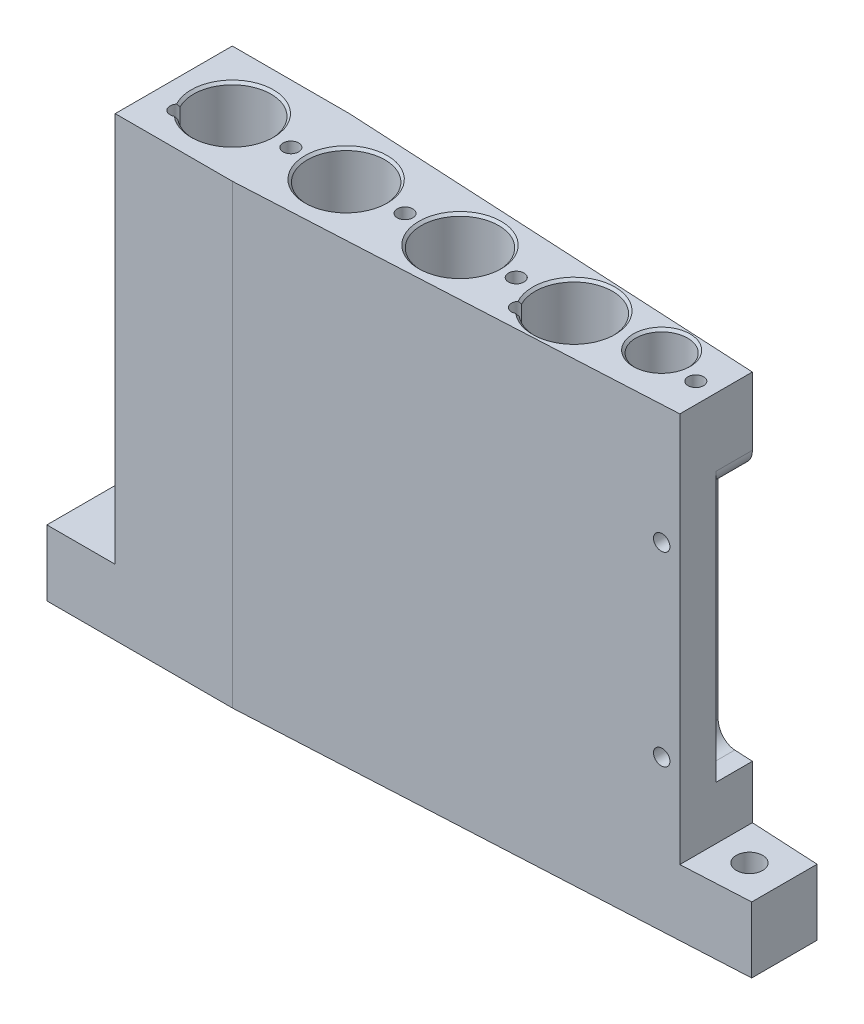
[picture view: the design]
ISO-10303-21;
HEADER;
FILE_DESCRIPTION(('STEP AP214'),'2;1');
FILE_NAME('part.step','',(''),(''),'','','');
FILE_SCHEMA(('AUTOMOTIVE_DESIGN { 1 0 10303 214 1 1 1 1 }'));
ENDSEC;
DATA;
#1=APPLICATION_CONTEXT('core data for automotive mechanical design processes');
#2=APPLICATION_PROTOCOL_DEFINITION('international standard','automotive_design',2000,#1);
#3=PRODUCT_CONTEXT('',#1,'mechanical');
#4=PRODUCT('Part','Part','',(#3));
#5=PRODUCT_RELATED_PRODUCT_CATEGORY('part','',(#4));
#6=PRODUCT_DEFINITION_FORMATION('','',#4);
#7=PRODUCT_DEFINITION_CONTEXT('part definition',#1,'design');
#8=PRODUCT_DEFINITION('design','',#6,#7);
#9=PRODUCT_DEFINITION_SHAPE('','',#8);
#10=(LENGTH_UNIT() NAMED_UNIT(*) SI_UNIT(.MILLI.,.METRE.));
#11=(NAMED_UNIT(*) PLANE_ANGLE_UNIT() SI_UNIT($,.RADIAN.));
#12=(NAMED_UNIT(*) SI_UNIT($,.STERADIAN.) SOLID_ANGLE_UNIT());
#13=UNCERTAINTY_MEASURE_WITH_UNIT(LENGTH_MEASURE(1.E-05),#10,'distance_accuracy_value','');
#14=(GEOMETRIC_REPRESENTATION_CONTEXT(3) GLOBAL_UNCERTAINTY_ASSIGNED_CONTEXT((#13)) GLOBAL_UNIT_ASSIGNED_CONTEXT((#10,
#11,#12)) REPRESENTATION_CONTEXT('',''));
#15=CARTESIAN_POINT('',(0.,0.,0.));
#16=DIRECTION('',(0.,0.,1.));
#17=DIRECTION('',(1.,0.,0.));
#18=AXIS2_PLACEMENT_3D('',#15,#16,#17);
#19=CARTESIAN_POINT('',(69.58,0.,-6.));
#20=DIRECTION('',(0.,-1.,0.));
#21=DIRECTION('',(0.,0.,-1.));
#22=AXIS2_PLACEMENT_3D('',#19,#20,#21);
#23=PLANE('',#22);
#24=CARTESIAN_POINT('',(26.67,0.,-1.5));
#25=DIRECTION('',(0.,-1.,0.));
#26=DIRECTION('',(0.,0.,-1.));
#27=AXIS2_PLACEMENT_3D('',#24,#25,#26);
#28=CIRCLE('',#27,1.3208);
#29=CARTESIAN_POINT('',(26.67,0.,-2.8208));
#30=VERTEX_POINT('',#29);
#31=EDGE_CURVE('E472',#30,#30,#28,.T.);
#32=ORIENTED_EDGE('',*,*,#31,.F.);
#33=EDGE_LOOP('',(#32));
#34=FACE_BOUND('',#33,.T.);
#35=CARTESIAN_POINT('',(26.67,0.,-1.5));
#36=DIRECTION('',(0.,-1.,0.));
#37=DIRECTION('',(0.,0.,-1.));
#38=AXIS2_PLACEMENT_3D('',#35,#36,#37);
#39=CIRCLE('',#38,1.55);
#40=CARTESIAN_POINT('',(26.67,0.,-3.04999999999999));
#41=VERTEX_POINT('',#40);
#42=EDGE_CURVE('E341',#41,#41,#39,.T.);
#43=ORIENTED_EDGE('',*,*,#42,.T.);
#44=EDGE_LOOP('',(#43));
#45=FACE_BOUND('',#44,.T.);
#46=ADVANCED_FACE('F38',(#34,#45),#23,.T.);
#47=CARTESIAN_POINT('',(38.33,0.,-1.5));
#48=DIRECTION('',(0.,-1.,0.));
#49=DIRECTION('',(0.,0.,-1.));
#50=AXIS2_PLACEMENT_3D('',#47,#48,#49);
#51=CIRCLE('',#50,1.3208);
#52=CARTESIAN_POINT('',(38.33,0.,-2.8208));
#53=VERTEX_POINT('',#52);
#54=EDGE_CURVE('E484',#53,#53,#51,.T.);
#55=ORIENTED_EDGE('',*,*,#54,.F.);
#56=EDGE_LOOP('',(#55));
#57=FACE_BOUND('',#56,.T.);
#58=CARTESIAN_POINT('',(34.33,0.,-1.5));
#59=DIRECTION('',(0.,-1.,0.));
#60=DIRECTION('',(0.,0.,-1.));
#61=AXIS2_PLACEMENT_3D('',#58,#59,#60);
#62=CIRCLE('',#61,1.3208);
#63=CARTESIAN_POINT('',(34.33,0.,-2.8208));
#64=VERTEX_POINT('',#63);
#65=EDGE_CURVE('E478',#64,#64,#62,.T.);
#66=ORIENTED_EDGE('',*,*,#65,.F.);
#67=EDGE_LOOP('',(#66));
#68=FACE_BOUND('',#67,.T.);
#69=DIRECTION('',(-1.,0.,0.));
#70=VECTOR('',#69,1.);
#71=CARTESIAN_POINT('',(34.33,0.,0.25));
#72=LINE('',#71,#70);
#73=CARTESIAN_POINT('',(38.33,0.,0.25));
#74=VERTEX_POINT('',#73);
#75=CARTESIAN_POINT('',(34.33,0.,0.25));
#76=VERTEX_POINT('',#75);
#77=EDGE_CURVE('E358',#74,#76,#72,.T.);
#78=ORIENTED_EDGE('',*,*,#77,.T.);
#79=CARTESIAN_POINT('',(34.33,0.,-1.5));
#80=DIRECTION('',(0.,-1.,0.));
#81=DIRECTION('',(0.,0.,-1.));
#82=AXIS2_PLACEMENT_3D('',#79,#80,#81);
#83=CIRCLE('',#82,1.75);
#84=CARTESIAN_POINT('',(34.33,0.,-3.25));
#85=VERTEX_POINT('',#84);
#86=EDGE_CURVE('E351',#76,#85,#83,.T.);
#87=ORIENTED_EDGE('',*,*,#86,.T.);
#88=DIRECTION('',(1.,0.,0.));
#89=VECTOR('',#88,1.);
#90=CARTESIAN_POINT('',(34.33,0.,-3.25));
#91=LINE('',#90,#89);
#92=CARTESIAN_POINT('',(38.33,0.,-3.25));
#93=VERTEX_POINT('',#92);
#94=EDGE_CURVE('E370',#85,#93,#91,.T.);
#95=ORIENTED_EDGE('',*,*,#94,.T.);
#96=CARTESIAN_POINT('',(38.33,0.,-1.5));
#97=DIRECTION('',(0.,-1.,0.));
#98=DIRECTION('',(0.,0.,-1.));
#99=AXIS2_PLACEMENT_3D('',#96,#97,#98);
#100=CIRCLE('',#99,1.75);
#101=EDGE_CURVE('E373',#93,#74,#100,.T.);
#102=ORIENTED_EDGE('',*,*,#101,.T.);
#103=EDGE_LOOP('',(#78,#87,#95,#102));
#104=FACE_BOUND('',#103,.T.);
#105=ADVANCED_FACE('F869',(#57,#68,#104),#23,.T.);
#106=CARTESIAN_POINT('',(13.,0.,0.));
#107=DIRECTION('',(0.,-1.,0.));
#108=DIRECTION('',(0.,0.,-1.));
#109=AXIS2_PLACEMENT_3D('',#106,#107,#108);
#110=CIRCLE('',#109,1.3208);
#111=CARTESIAN_POINT('',(13.,0.,-1.3208));
#112=VERTEX_POINT('',#111);
#113=EDGE_CURVE('E496',#112,#112,#110,.T.);
#114=ORIENTED_EDGE('',*,*,#113,.F.);
#115=EDGE_LOOP('',(#114));
#116=FACE_BOUND('',#115,.T.);
#117=CARTESIAN_POINT('',(13.,0.,0.));
#118=DIRECTION('',(0.,-1.,0.));
#119=DIRECTION('',(0.,0.,-1.));
#120=AXIS2_PLACEMENT_3D('',#117,#118,#119);
#121=CIRCLE('',#120,1.55);
#122=CARTESIAN_POINT('',(13.,0.,-1.55));
#123=VERTEX_POINT('',#122);
#124=EDGE_CURVE('E452',#123,#123,#121,.T.);
#125=ORIENTED_EDGE('',*,*,#124,.T.);
#126=EDGE_LOOP('',(#125));
#127=FACE_BOUND('',#126,.T.);
#128=ADVANCED_FACE('F876',(#116,#127),#23,.T.);
#129=CARTESIAN_POINT('',(69.58,46.75,-6.));
#130=DIRECTION('',(0.,-1.,0.));
#131=DIRECTION('',(0.,0.,-1.));
#132=AXIS2_PLACEMENT_3D('',#129,#130,#131);
#133=PLANE('',#132);
#134=CARTESIAN_POINT('',(56.,46.75,-1.));
#135=DIRECTION('',(0.,-1.,0.));
#136=DIRECTION('',(0.,0.,-1.));
#137=AXIS2_PLACEMENT_3D('',#134,#135,#136);
#138=CIRCLE('',#137,2.90429999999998);
#139=CARTESIAN_POINT('',(56.,46.75,-3.90429999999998));
#140=VERTEX_POINT('',#139);
#141=EDGE_CURVE('E1716',#140,#140,#138,.T.);
#142=ORIENTED_EDGE('',*,*,#141,.T.);
#143=EDGE_LOOP('',(#142));
#144=FACE_BOUND('',#143,.T.);
#145=CARTESIAN_POINT('',(36.3333333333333,46.75,0.));
#146=DIRECTION('',(0.,-1.,0.));
#147=DIRECTION('',(0.,0.,-1.));
#148=AXIS2_PLACEMENT_3D('',#145,#146,#147);
#149=CIRCLE('',#148,4.21874999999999);
#150=CARTESIAN_POINT('',(36.3333333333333,46.75,-4.21874999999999));
#151=VERTEX_POINT('',#150);
#152=EDGE_CURVE('E1717',#151,#151,#149,.T.);
#153=ORIENTED_EDGE('',*,*,#152,.T.);
#154=EDGE_LOOP('',(#153));
#155=FACE_BOUND('',#154,.T.);
#156=CARTESIAN_POINT('',(24.6666666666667,46.75,0.));
#157=DIRECTION('',(0.,-1.,0.));
#158=DIRECTION('',(0.,0.,-1.));
#159=AXIS2_PLACEMENT_3D('',#156,#157,#158);
#160=CIRCLE('',#159,4.21874999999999);
#161=CARTESIAN_POINT('',(24.6666666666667,46.75,-4.21874999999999));
#162=VERTEX_POINT('',#161);
#163=EDGE_CURVE('E1723',#162,#162,#160,.T.);
#164=ORIENTED_EDGE('',*,*,#163,.T.);
#165=EDGE_LOOP('',(#164));
#166=FACE_BOUND('',#165,.T.);
#167=CARTESIAN_POINT('',(19.,46.75,0.));
#168=DIRECTION('',(0.,1.,0.));
#169=DIRECTION('',(0.,0.,1.));
#170=AXIS2_PLACEMENT_3D('',#167,#168,#169);
#171=CIRCLE('',#170,0.799999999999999);
#172=CARTESIAN_POINT('',(19.,46.75,0.799999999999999));
#173=VERTEX_POINT('',#172);
#174=EDGE_CURVE('E503',#173,#173,#171,.T.);
#175=ORIENTED_EDGE('',*,*,#174,.F.);
#176=EDGE_LOOP('',(#175));
#177=FACE_BOUND('',#176,.T.);
#178=CARTESIAN_POINT('',(30.7,46.75,0.));
#179=DIRECTION('',(0.,1.,0.));
#180=DIRECTION('',(0.,0.,1.));
#181=AXIS2_PLACEMENT_3D('',#178,#179,#180);
#182=CIRCLE('',#181,0.800000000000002);
#183=CARTESIAN_POINT('',(30.7,46.75,0.800000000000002));
#184=VERTEX_POINT('',#183);
#185=EDGE_CURVE('E509',#184,#184,#182,.T.);
#186=ORIENTED_EDGE('',*,*,#185,.F.);
#187=EDGE_LOOP('',(#186));
#188=FACE_BOUND('',#187,.T.);
#189=CARTESIAN_POINT('',(42.1,46.75,0.));
#190=DIRECTION('',(0.,1.,0.));
#191=DIRECTION('',(0.,0.,1.));
#192=AXIS2_PLACEMENT_3D('',#189,#190,#191);
#193=CIRCLE('',#192,0.800000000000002);
#194=CARTESIAN_POINT('',(42.1,46.75,0.800000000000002));
#195=VERTEX_POINT('',#194);
#196=EDGE_CURVE('E515',#195,#195,#193,.T.);
#197=ORIENTED_EDGE('',*,*,#196,.F.);
#198=EDGE_LOOP('',(#197));
#199=FACE_BOUND('',#198,.T.);
#200=CARTESIAN_POINT('',(60.5,46.75,0.));
#201=DIRECTION('',(0.,1.,0.));
#202=DIRECTION('',(0.,0.,1.));
#203=AXIS2_PLACEMENT_3D('',#200,#201,#202);
#204=CIRCLE('',#203,0.800000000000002);
#205=CARTESIAN_POINT('',(60.5,46.75,0.800000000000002));
#206=VERTEX_POINT('',#205);
#207=EDGE_CURVE('E521',#206,#206,#204,.T.);
#208=ORIENTED_EDGE('',*,*,#207,.F.);
#209=EDGE_LOOP('',(#208));
#210=FACE_BOUND('',#209,.T.);
#211=DIRECTION('',(0.,0.,-1.));
#212=VECTOR('',#211,1.);
#213=CARTESIAN_POINT('',(62.58,46.75,-3.71685445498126));
#214=LINE('',#213,#212);
#215=CARTESIAN_POINT('',(62.58,46.75,3.71685445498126));
#216=VERTEX_POINT('',#215);
#217=CARTESIAN_POINT('',(62.58,46.75,-3.71685445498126));
#218=VERTEX_POINT('',#217);
#219=EDGE_CURVE('E563',#216,#218,#214,.T.);
#220=ORIENTED_EDGE('',*,*,#219,.T.);
#221=DIRECTION('',(-0.998629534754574,0.,-0.0523359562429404));
#222=VECTOR('',#221,1.);
#223=CARTESIAN_POINT('',(69.58,46.75,-3.35));
#224=LINE('',#223,#222);
#225=CARTESIAN_POINT('',(19.0149877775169,46.75,-6.));
#226=VERTEX_POINT('',#225);
#227=EDGE_CURVE('E614',#218,#226,#224,.T.);
#228=ORIENTED_EDGE('',*,*,#227,.T.);
#229=DIRECTION('',(-1.,0.,0.));
#230=VECTOR('',#229,1.);
#231=CARTESIAN_POINT('',(0.,46.75,-6.));
#232=LINE('',#231,#230);
#233=CARTESIAN_POINT('',(7.,46.75,-6.));
#234=VERTEX_POINT('',#233);
#235=EDGE_CURVE('E616',#226,#234,#232,.T.);
#236=ORIENTED_EDGE('',*,*,#235,.T.);
#237=DIRECTION('',(0.,0.,1.));
#238=VECTOR('',#237,1.);
#239=CARTESIAN_POINT('',(7.,46.75,-6.));
#240=LINE('',#239,#238);
#241=CARTESIAN_POINT('',(6.99999999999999,46.75,6.));
#242=VERTEX_POINT('',#241);
#243=EDGE_CURVE('E579',#234,#242,#240,.T.);
#244=ORIENTED_EDGE('',*,*,#243,.T.);
#245=DIRECTION('',(1.,0.,0.));
#246=VECTOR('',#245,1.);
#247=CARTESIAN_POINT('',(0.,46.75,6.));
#248=LINE('',#247,#246);
#249=CARTESIAN_POINT('',(19.0149877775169,46.75,6.));
#250=VERTEX_POINT('',#249);
#251=EDGE_CURVE('E620',#242,#250,#248,.T.);
#252=ORIENTED_EDGE('',*,*,#251,.T.);
#253=DIRECTION('',(0.998629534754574,0.,-0.0523359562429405));
#254=VECTOR('',#253,1.);
#255=CARTESIAN_POINT('',(19.0149877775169,46.75,6.));
#256=LINE('',#255,#254);
#257=EDGE_CURVE('E622',#250,#216,#256,.T.);
#258=ORIENTED_EDGE('',*,*,#257,.T.);
#259=EDGE_LOOP('',(#220,#228,#236,#244,#252,#258));
#260=FACE_BOUND('',#259,.T.);
#261=CARTESIAN_POINT('',(9.91763458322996,46.75,2.5));
#262=DIRECTION('',(0.,1.,0.));
#263=DIRECTION('',(0.,0.,1.));
#264=AXIS2_PLACEMENT_3D('',#261,#262,#263);
#265=CIRCLE('',#264,0.793749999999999);
#266=CARTESIAN_POINT('',(9.29180855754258,46.75,2.01175738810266));
#267=VERTEX_POINT('',#266);
#268=CARTESIAN_POINT('',(10.2661948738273,46.75,3.21312326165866));
#269=VERTEX_POINT('',#268);
#270=EDGE_CURVE('E527',#267,#269,#265,.T.);
#271=ORIENTED_EDGE('',*,*,#270,.F.);
#272=CARTESIAN_POINT('',(13.,46.75,0.));
#273=DIRECTION('',(0.,-1.,0.));
#274=DIRECTION('',(0.,0.,-1.));
#275=AXIS2_PLACEMENT_3D('',#272,#273,#274);
#276=CIRCLE('',#275,4.21875000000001);
#277=EDGE_CURVE('E820',#267,#269,#276,.T.);
#278=ORIENTED_EDGE('',*,*,#277,.T.);
#279=EDGE_LOOP('',(#271,#278));
#280=FACE_BOUND('',#279,.T.);
#281=CARTESIAN_POINT('',(44.91763458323,46.75,2.5));
#282=DIRECTION('',(0.,1.,0.));
#283=DIRECTION('',(0.,0.,1.));
#284=AXIS2_PLACEMENT_3D('',#281,#282,#283);
#285=CIRCLE('',#284,0.793749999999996);
#286=CARTESIAN_POINT('',(44.2918085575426,46.75,2.01175738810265));
#287=VERTEX_POINT('',#286);
#288=CARTESIAN_POINT('',(45.2661948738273,46.75,3.21312326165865));
#289=VERTEX_POINT('',#288);
#290=EDGE_CURVE('E533',#287,#289,#285,.T.);
#291=ORIENTED_EDGE('',*,*,#290,.F.);
#292=CARTESIAN_POINT('',(48.,46.75,0.));
#293=DIRECTION('',(0.,-1.,0.));
#294=DIRECTION('',(0.,0.,-1.));
#295=AXIS2_PLACEMENT_3D('',#292,#293,#294);
#296=CIRCLE('',#295,4.21874999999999);
#297=EDGE_CURVE('E1712',#287,#289,#296,.T.);
#298=ORIENTED_EDGE('',*,*,#297,.T.);
#299=EDGE_LOOP('',(#291,#298));
#300=FACE_BOUND('',#299,.T.);
#301=ADVANCED_FACE('F896',(#144,#155,#166,#177,#188,#199,#210,#260,#280,#300),#133,.F.);
#302=CARTESIAN_POINT('',(69.58,46.75,-3.35));
#303=DIRECTION('',(-0.0523359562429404,0.,0.998629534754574));
#304=DIRECTION('',(0.998629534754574,0.,0.0523359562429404));
#305=AXIS2_PLACEMENT_3D('',#302,#303,#304);
#306=PLANE('',#305);
#307=DIRECTION('',(0.,1.,0.));
#308=VECTOR('',#307,1.);
#309=CARTESIAN_POINT('',(62.58,6.75,-3.71685445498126));
#310=LINE('',#309,#308);
#311=CARTESIAN_POINT('',(62.58,39.8,-3.71685445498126));
#312=VERTEX_POINT('',#311);
#313=EDGE_CURVE('E569',#312,#218,#310,.T.);
#314=ORIENTED_EDGE('',*,*,#313,.F.);
#315=CARTESIAN_POINT('',(60.78,39.8,-3.81118845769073));
#316=DIRECTION('',(-0.0523359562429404,0.,0.998629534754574));
#317=DIRECTION('',(-0.998629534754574,0.,-0.0523359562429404));
#318=AXIS2_PLACEMENT_3D('',#315,#316,#317);
#319=ELLIPSE('',#318,1.80247022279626,1.8);
#320=CARTESIAN_POINT('',(60.78,38.,-3.81118845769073));
#321=VERTEX_POINT('',#320);
#322=EDGE_CURVE('E305',#312,#321,#319,.F.);
#323=ORIENTED_EDGE('',*,*,#322,.T.);
#324=DIRECTION('',(-0.998629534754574,0.,-0.0523359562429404));
#325=VECTOR('',#324,1.);
#326=CARTESIAN_POINT('',(69.58,38.,-3.35));
#327=LINE('',#326,#325);
#328=CARTESIAN_POINT('',(60.68,38.,-3.81642923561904));
#329=VERTEX_POINT('',#328);
#330=EDGE_CURVE('E266',#321,#329,#327,.T.);
#331=ORIENTED_EDGE('',*,*,#330,.T.);
#332=CARTESIAN_POINT('',(60.68,36.2,-3.81642923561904));
#333=DIRECTION('',(-0.0523359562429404,0.,0.998629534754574));
#334=DIRECTION('',(-0.998629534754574,0.,-0.0523359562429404));
#335=AXIS2_PLACEMENT_3D('',#332,#333,#334);
#336=ELLIPSE('',#335,1.80247022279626,1.8);
#337=CARTESIAN_POINT('',(58.88,36.2,-3.9107632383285));
#338=VERTEX_POINT('',#337);
#339=EDGE_CURVE('E46',#329,#338,#336,.T.);
#340=ORIENTED_EDGE('',*,*,#339,.T.);
#341=DIRECTION('',(0.,-1.,0.));
#342=VECTOR('',#341,1.);
#343=CARTESIAN_POINT('',(58.88,46.75,-3.9107632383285));
#344=LINE('',#343,#342);
#345=CARTESIAN_POINT('',(58.88,14.,-3.9107632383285));
#346=VERTEX_POINT('',#345);
#347=EDGE_CURVE('E283',#338,#346,#344,.T.);
#348=ORIENTED_EDGE('',*,*,#347,.T.);
#349=CARTESIAN_POINT('',(60.68,14.,-3.81642923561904));
#350=DIRECTION('',(-0.0523359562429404,0.,0.998629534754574));
#351=DIRECTION('',(-0.998629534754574,0.,-0.0523359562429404));
#352=AXIS2_PLACEMENT_3D('',#349,#350,#351);
#353=ELLIPSE('',#352,1.80247022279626,1.8);
#354=CARTESIAN_POINT('',(60.68,12.2,-3.81642923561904));
#355=VERTEX_POINT('',#354);
#356=EDGE_CURVE('E11',#346,#355,#353,.T.);
#357=ORIENTED_EDGE('',*,*,#356,.T.);
#358=DIRECTION('',(0.998629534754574,0.,0.0523359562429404));
#359=VECTOR('',#358,1.);
#360=CARTESIAN_POINT('',(69.58,12.2,-3.35));
#361=LINE('',#360,#359);
#362=CARTESIAN_POINT('',(62.58,12.2,-3.71685445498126));
#363=VERTEX_POINT('',#362);
#364=EDGE_CURVE('E339',#355,#363,#361,.T.);
#365=ORIENTED_EDGE('',*,*,#364,.T.);
#366=CARTESIAN_POINT('',(62.58,6.75,-3.71685445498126));
#367=VERTEX_POINT('',#366);
#368=EDGE_CURVE('E282',#367,#363,#310,.T.);
#369=ORIENTED_EDGE('',*,*,#368,.F.);
#370=DIRECTION('',(0.998629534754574,0.,0.0523359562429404));
#371=VECTOR('',#370,1.);
#372=CARTESIAN_POINT('',(69.58,6.75,-3.35));
#373=LINE('',#372,#371);
#374=CARTESIAN_POINT('',(69.58,6.75,-3.35));
#375=VERTEX_POINT('',#374);
#376=EDGE_CURVE('E576',#367,#375,#373,.T.);
#377=ORIENTED_EDGE('',*,*,#376,.T.);
#378=DIRECTION('',(0.,-1.,0.));
#379=VECTOR('',#378,1.);
#380=CARTESIAN_POINT('',(69.58,46.75,-3.35));
#381=LINE('',#380,#379);
#382=CARTESIAN_POINT('',(69.58,0.,-3.35));
#383=VERTEX_POINT('',#382);
#384=EDGE_CURVE('E651',#375,#383,#381,.T.);
#385=ORIENTED_EDGE('',*,*,#384,.T.);
#386=DIRECTION('',(-0.998629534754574,0.,-0.0523359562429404));
#387=VECTOR('',#386,1.);
#388=CARTESIAN_POINT('',(69.58,0.,-3.35));
#389=LINE('',#388,#387);
#390=CARTESIAN_POINT('',(19.0149877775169,0.,-6.));
#391=VERTEX_POINT('',#390);
#392=EDGE_CURVE('E628',#383,#391,#389,.T.);
#393=ORIENTED_EDGE('',*,*,#392,.T.);
#394=DIRECTION('',(0.,-1.,0.));
#395=VECTOR('',#394,1.);
#396=CARTESIAN_POINT('',(19.0149877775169,46.75,-6.));
#397=LINE('',#396,#395);
#398=EDGE_CURVE('E648',#226,#391,#397,.T.);
#399=ORIENTED_EDGE('',*,*,#398,.F.);
#400=ORIENTED_EDGE('',*,*,#227,.F.);
#401=EDGE_LOOP('',(#314,#323,#331,#340,#348,#357,#365,#369,#377,#385,#393,#399,#400));
#402=FACE_BOUND('',#401,.T.);
#403=ADVANCED_FACE('F321',(#402),#306,.F.);
#404=CARTESIAN_POINT('',(19.0149877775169,46.75,6.));
#405=DIRECTION('',(-0.0523359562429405,0.,-0.998629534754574));
#406=DIRECTION('',(-0.998629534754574,0.,0.0523359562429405));
#407=AXIS2_PLACEMENT_3D('',#404,#405,#406);
#408=PLANE('',#407);
#409=CARTESIAN_POINT('',(60.815,34.505,3.80935418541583));
#410=DIRECTION('',(-0.0523359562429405,0.,-0.998629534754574));
#411=DIRECTION('',(0.998629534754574,0.,-0.0523359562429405));
#412=AXIS2_PLACEMENT_3D('',#409,#410,#411);
#413=ELLIPSE('',#412,0.801097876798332,0.799999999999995);
#414=CARTESIAN_POINT('',(61.615,34.505,3.7674279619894));
#415=VERTEX_POINT('',#414);
#416=EDGE_CURVE('E1593',#415,#415,#413,.T.);
#417=ORIENTED_EDGE('',*,*,#416,.T.);
#418=EDGE_LOOP('',(#417));
#419=FACE_BOUND('',#418,.T.);
#420=CARTESIAN_POINT('',(60.815,15.455,3.80935418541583));
#421=DIRECTION('',(-0.0523359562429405,0.,-0.998629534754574));
#422=DIRECTION('',(0.998629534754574,0.,-0.0523359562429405));
#423=AXIS2_PLACEMENT_3D('',#420,#421,#422);
#424=ELLIPSE('',#423,0.801097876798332,0.799999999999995);
#425=CARTESIAN_POINT('',(61.615,15.455,3.7674279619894));
#426=VERTEX_POINT('',#425);
#427=EDGE_CURVE('E277',#426,#426,#424,.T.);
#428=ORIENTED_EDGE('',*,*,#427,.T.);
#429=EDGE_LOOP('',(#428));
#430=FACE_BOUND('',#429,.T.);
#431=DIRECTION('',(0.,1.,0.));
#432=VECTOR('',#431,1.);
#433=CARTESIAN_POINT('',(62.58,6.75,3.71685445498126));
#434=LINE('',#433,#432);
#435=CARTESIAN_POINT('',(62.58,6.75,3.71685445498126));
#436=VERTEX_POINT('',#435);
#437=EDGE_CURVE('E573',#436,#216,#434,.T.);
#438=ORIENTED_EDGE('',*,*,#437,.T.);
#439=ORIENTED_EDGE('',*,*,#257,.F.);
#440=DIRECTION('',(0.,-1.,0.));
#441=VECTOR('',#440,1.);
#442=CARTESIAN_POINT('',(19.0149877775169,46.75,6.));
#443=LINE('',#442,#441);
#444=CARTESIAN_POINT('',(19.0149877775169,0.,6.));
#445=VERTEX_POINT('',#444);
#446=EDGE_CURVE('E641',#250,#445,#443,.T.);
#447=ORIENTED_EDGE('',*,*,#446,.T.);
#448=DIRECTION('',(0.998629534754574,0.,-0.0523359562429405));
#449=VECTOR('',#448,1.);
#450=CARTESIAN_POINT('',(19.0149877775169,0.,6.));
#451=LINE('',#450,#449);
#452=CARTESIAN_POINT('',(69.58,0.,3.35));
#453=VERTEX_POINT('',#452);
#454=EDGE_CURVE('E617',#445,#453,#451,.T.);
#455=ORIENTED_EDGE('',*,*,#454,.T.);
#456=DIRECTION('',(0.,-1.,0.));
#457=VECTOR('',#456,1.);
#458=CARTESIAN_POINT('',(69.58,46.75,3.35));
#459=LINE('',#458,#457);
#460=CARTESIAN_POINT('',(69.58,6.75,3.35));
#461=VERTEX_POINT('',#460);
#462=EDGE_CURVE('E625',#461,#453,#459,.T.);
#463=ORIENTED_EDGE('',*,*,#462,.F.);
#464=DIRECTION('',(-0.998629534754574,0.,0.0523359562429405));
#465=VECTOR('',#464,1.);
#466=CARTESIAN_POINT('',(19.0149877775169,6.75,6.));
#467=LINE('',#466,#465);
#468=EDGE_CURVE('E653',#461,#436,#467,.T.);
#469=ORIENTED_EDGE('',*,*,#468,.T.);
#470=EDGE_LOOP('',(#438,#439,#447,#455,#463,#469));
#471=FACE_BOUND('',#470,.T.);
#472=ADVANCED_FACE('F1565',(#419,#430,#471),#408,.F.);
#473=CARTESIAN_POINT('',(0.,46.75,-6.));
#474=DIRECTION('',(0.,0.,1.));
#475=DIRECTION('',(1.,0.,0.));
#476=AXIS2_PLACEMENT_3D('',#473,#474,#475);
#477=PLANE('',#476);
#478=DIRECTION('',(0.,1.,0.));
#479=VECTOR('',#478,1.);
#480=CARTESIAN_POINT('',(7.,6.75,-6.));
#481=LINE('',#480,#479);
#482=CARTESIAN_POINT('',(7.,6.75,-6.));
#483=VERTEX_POINT('',#482);
#484=EDGE_CURVE('E595',#483,#234,#481,.T.);
#485=ORIENTED_EDGE('',*,*,#484,.T.);
#486=ORIENTED_EDGE('',*,*,#235,.F.);
#487=ORIENTED_EDGE('',*,*,#398,.T.);
#488=DIRECTION('',(-1.,0.,0.));
#489=VECTOR('',#488,1.);
#490=CARTESIAN_POINT('',(0.,0.,-6.));
#491=LINE('',#490,#489);
#492=CARTESIAN_POINT('',(0.,0.,-6.));
#493=VERTEX_POINT('',#492);
#494=EDGE_CURVE('E630',#391,#493,#491,.T.);
#495=ORIENTED_EDGE('',*,*,#494,.T.);
#496=DIRECTION('',(0.,-1.,0.));
#497=VECTOR('',#496,1.);
#498=CARTESIAN_POINT('',(0.,46.75,-6.));
#499=LINE('',#498,#497);
#500=CARTESIAN_POINT('',(0.,6.75,-6.));
#501=VERTEX_POINT('',#500);
#502=EDGE_CURVE('E646',#501,#493,#499,.T.);
#503=ORIENTED_EDGE('',*,*,#502,.F.);
#504=DIRECTION('',(1.,0.,0.));
#505=VECTOR('',#504,1.);
#506=CARTESIAN_POINT('',(0.,6.75,-6.));
#507=LINE('',#506,#505);
#508=EDGE_CURVE('E580',#501,#483,#507,.T.);
#509=ORIENTED_EDGE('',*,*,#508,.T.);
#510=EDGE_LOOP('',(#485,#486,#487,#495,#503,#509));
#511=FACE_BOUND('',#510,.T.);
#512=ADVANCED_FACE('F1556',(#511),#477,.F.);
#513=CARTESIAN_POINT('',(0.,46.75,6.));
#514=DIRECTION('',(0.,0.,-1.));
#515=DIRECTION('',(-1.,0.,0.));
#516=AXIS2_PLACEMENT_3D('',#513,#514,#515);
#517=PLANE('',#516);
#518=DIRECTION('',(0.,1.,0.));
#519=VECTOR('',#518,1.);
#520=CARTESIAN_POINT('',(7.,6.75,6.));
#521=LINE('',#520,#519);
#522=CARTESIAN_POINT('',(7.,6.75,6.));
#523=VERTEX_POINT('',#522);
#524=EDGE_CURVE('E591',#523,#242,#521,.T.);
#525=ORIENTED_EDGE('',*,*,#524,.F.);
#526=DIRECTION('',(-1.,0.,0.));
#527=VECTOR('',#526,1.);
#528=CARTESIAN_POINT('',(0.,6.75,6.));
#529=LINE('',#528,#527);
#530=CARTESIAN_POINT('',(0.,6.75,6.));
#531=VERTEX_POINT('',#530);
#532=EDGE_CURVE('E585',#523,#531,#529,.T.);
#533=ORIENTED_EDGE('',*,*,#532,.T.);
#534=DIRECTION('',(0.,-1.,0.));
#535=VECTOR('',#534,1.);
#536=CARTESIAN_POINT('',(0.,46.75,6.));
#537=LINE('',#536,#535);
#538=CARTESIAN_POINT('',(0.,0.,6.));
#539=VERTEX_POINT('',#538);
#540=EDGE_CURVE('E644',#531,#539,#537,.T.);
#541=ORIENTED_EDGE('',*,*,#540,.T.);
#542=DIRECTION('',(1.,0.,0.));
#543=VECTOR('',#542,1.);
#544=CARTESIAN_POINT('',(0.,0.,6.));
#545=LINE('',#544,#543);
#546=EDGE_CURVE('E636',#539,#445,#545,.T.);
#547=ORIENTED_EDGE('',*,*,#546,.T.);
#548=ORIENTED_EDGE('',*,*,#446,.F.);
#549=ORIENTED_EDGE('',*,*,#251,.F.);
#550=EDGE_LOOP('',(#525,#533,#541,#547,#548,#549));
#551=FACE_BOUND('',#550,.T.);
#552=ADVANCED_FACE('F1548',(#551),#517,.F.);
#553=CARTESIAN_POINT('',(69.58,46.75,3.35));
#554=DIRECTION('',(-1.,0.,0.));
#555=DIRECTION('',(0.,0.,1.));
#556=AXIS2_PLACEMENT_3D('',#553,#554,#555);
#557=PLANE('',#556);
#558=ORIENTED_EDGE('',*,*,#384,.F.);
#559=DIRECTION('',(0.,0.,1.));
#560=VECTOR('',#559,1.);
#561=CARTESIAN_POINT('',(69.58,6.75,-3.71685445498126));
#562=LINE('',#561,#560);
#563=EDGE_CURVE('E564',#375,#461,#562,.T.);
#564=ORIENTED_EDGE('',*,*,#563,.T.);
#565=ORIENTED_EDGE('',*,*,#462,.T.);
#566=DIRECTION('',(0.,0.,-1.));
#567=VECTOR('',#566,1.);
#568=CARTESIAN_POINT('',(69.58,0.,3.35));
#569=LINE('',#568,#567);
#570=EDGE_CURVE('E613',#453,#383,#569,.T.);
#571=ORIENTED_EDGE('',*,*,#570,.T.);
#572=EDGE_LOOP('',(#558,#564,#565,#571));
#573=FACE_BOUND('',#572,.T.);
#574=ADVANCED_FACE('F890',(#573),#557,.F.);
#575=CARTESIAN_POINT('',(0.,46.75,-6.));
#576=DIRECTION('',(1.,0.,0.));
#577=DIRECTION('',(0.,0.,-1.));
#578=AXIS2_PLACEMENT_3D('',#575,#576,#577);
#579=PLANE('',#578);
#580=ORIENTED_EDGE('',*,*,#540,.F.);
#581=DIRECTION('',(0.,0.,-1.));
#582=VECTOR('',#581,1.);
#583=CARTESIAN_POINT('',(0.,6.75,-6.));
#584=LINE('',#583,#582);
#585=EDGE_CURVE('E588',#531,#501,#584,.T.);
#586=ORIENTED_EDGE('',*,*,#585,.T.);
#587=ORIENTED_EDGE('',*,*,#502,.T.);
#588=DIRECTION('',(0.,0.,1.));
#589=VECTOR('',#588,1.);
#590=CARTESIAN_POINT('',(0.,0.,-6.));
#591=LINE('',#590,#589);
#592=EDGE_CURVE('E633',#493,#539,#591,.T.);
#593=ORIENTED_EDGE('',*,*,#592,.T.);
#594=EDGE_LOOP('',(#580,#586,#587,#593));
#595=FACE_BOUND('',#594,.T.);
#596=ADVANCED_FACE('F883',(#595),#579,.F.);
#597=CARTESIAN_POINT('',(26.67,0.,-1.5));
#598=DIRECTION('',(0.,-1.,0.));
#599=DIRECTION('',(0.,0.,-1.));
#600=AXIS2_PLACEMENT_3D('',#597,#598,#599);
#601=CIRCLE('',#600,2.95);
#602=CARTESIAN_POINT('',(26.67,0.,-4.45));
#603=VERTEX_POINT('',#602);
#604=EDGE_CURVE('E345',#603,#603,#601,.T.);
#605=ORIENTED_EDGE('',*,*,#604,.F.);
#606=EDGE_LOOP('',(#605));
#607=FACE_BOUND('',#606,.T.);
#608=CARTESIAN_POINT('',(34.33,0.,-1.5));
#609=DIRECTION('',(0.,-1.,0.));
#610=DIRECTION('',(0.,0.,-1.));
#611=AXIS2_PLACEMENT_3D('',#608,#609,#610);
#612=CIRCLE('',#611,3.05);
#613=CARTESIAN_POINT('',(34.33,0.,1.55));
#614=VERTEX_POINT('',#613);
#615=CARTESIAN_POINT('',(34.33,0.,-4.55));
#616=VERTEX_POINT('',#615);
#617=EDGE_CURVE('E380',#614,#616,#612,.T.);
#618=ORIENTED_EDGE('',*,*,#617,.F.);
#619=DIRECTION('',(-1.,0.,0.));
#620=VECTOR('',#619,1.);
#621=CARTESIAN_POINT('',(34.33,0.,1.55));
#622=LINE('',#621,#620);
#623=CARTESIAN_POINT('',(38.33,0.,1.55));
#624=VERTEX_POINT('',#623);
#625=EDGE_CURVE('E391',#624,#614,#622,.T.);
#626=ORIENTED_EDGE('',*,*,#625,.F.);
#627=CARTESIAN_POINT('',(38.33,0.,-1.5));
#628=DIRECTION('',(0.,-1.,0.));
#629=DIRECTION('',(0.,0.,-1.));
#630=AXIS2_PLACEMENT_3D('',#627,#628,#629);
#631=CIRCLE('',#630,3.05);
#632=CARTESIAN_POINT('',(38.33,0.,-4.55));
#633=VERTEX_POINT('',#632);
#634=EDGE_CURVE('E405',#633,#624,#631,.T.);
#635=ORIENTED_EDGE('',*,*,#634,.F.);
#636=DIRECTION('',(1.,0.,0.));
#637=VECTOR('',#636,1.);
#638=CARTESIAN_POINT('',(34.33,0.,-4.55));
#639=LINE('',#638,#637);
#640=EDGE_CURVE('E402',#616,#633,#639,.T.);
#641=ORIENTED_EDGE('',*,*,#640,.F.);
#642=EDGE_LOOP('',(#618,#626,#635,#641));
#643=FACE_BOUND('',#642,.T.);
#644=CARTESIAN_POINT('',(48.7,0.,-0.8));
#645=DIRECTION('',(0.,-1.,0.));
#646=DIRECTION('',(0.,0.,-1.));
#647=AXIS2_PLACEMENT_3D('',#644,#645,#646);
#648=CIRCLE('',#647,2.95);
#649=CARTESIAN_POINT('',(48.7,0.,-3.75));
#650=VERTEX_POINT('',#649);
#651=EDGE_CURVE('E446',#650,#650,#648,.T.);
#652=ORIENTED_EDGE('',*,*,#651,.F.);
#653=EDGE_LOOP('',(#652));
#654=FACE_BOUND('',#653,.T.);
#655=CARTESIAN_POINT('',(13.,0.,0.));
#656=DIRECTION('',(0.,-1.,0.));
#657=DIRECTION('',(0.,0.,-1.));
#658=AXIS2_PLACEMENT_3D('',#655,#656,#657);
#659=CIRCLE('',#658,2.95);
#660=CARTESIAN_POINT('',(13.,0.,-2.95));
#661=VERTEX_POINT('',#660);
#662=EDGE_CURVE('E458',#661,#661,#659,.T.);
#663=ORIENTED_EDGE('',*,*,#662,.F.);
#664=EDGE_LOOP('',(#663));
#665=FACE_BOUND('',#664,.T.);
#666=CARTESIAN_POINT('',(8.,0.,0.));
#667=DIRECTION('',(0.,-1.,0.));
#668=DIRECTION('',(0.,0.,-1.));
#669=AXIS2_PLACEMENT_3D('',#666,#667,#668);
#670=CIRCLE('',#669,0.793749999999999);
#671=CARTESIAN_POINT('',(8.,0.,-0.793749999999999));
#672=VERTEX_POINT('',#671);
#673=EDGE_CURVE('E539',#672,#672,#670,.T.);
#674=ORIENTED_EDGE('',*,*,#673,.F.);
#675=EDGE_LOOP('',(#674));
#676=FACE_BOUND('',#675,.T.);
#677=CARTESIAN_POINT('',(62.,0.,0.));
#678=DIRECTION('',(0.,-1.,0.));
#679=DIRECTION('',(0.,0.,-1.));
#680=AXIS2_PLACEMENT_3D('',#677,#678,#679);
#681=CIRCLE('',#680,0.793749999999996);
#682=CARTESIAN_POINT('',(62.,0.,-0.793749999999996));
#683=VERTEX_POINT('',#682);
#684=EDGE_CURVE('E545',#683,#683,#681,.T.);
#685=ORIENTED_EDGE('',*,*,#684,.F.);
#686=EDGE_LOOP('',(#685));
#687=FACE_BOUND('',#686,.T.);
#688=CARTESIAN_POINT('',(3.5,0.,0.));
#689=DIRECTION('',(0.,1.,0.));
#690=DIRECTION('',(0.,0.,1.));
#691=AXIS2_PLACEMENT_3D('',#688,#689,#690);
#692=CIRCLE('',#691,1.35);
#693=CARTESIAN_POINT('',(3.5,0.,1.35));
#694=VERTEX_POINT('',#693);
#695=EDGE_CURVE('E554',#694,#694,#692,.T.);
#696=ORIENTED_EDGE('',*,*,#695,.T.);
#697=EDGE_LOOP('',(#696));
#698=FACE_BOUND('',#697,.T.);
#699=CARTESIAN_POINT('',(66.,0.,0.));
#700=DIRECTION('',(0.,1.,0.));
#701=DIRECTION('',(0.,0.,1.));
#702=AXIS2_PLACEMENT_3D('',#699,#700,#701);
#703=CIRCLE('',#702,1.35);
#704=CARTESIAN_POINT('',(66.,0.,1.35000000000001));
#705=VERTEX_POINT('',#704);
#706=EDGE_CURVE('E560',#705,#705,#703,.T.);
#707=ORIENTED_EDGE('',*,*,#706,.T.);
#708=EDGE_LOOP('',(#707));
#709=FACE_BOUND('',#708,.T.);
#710=CARTESIAN_POINT('',(56.,0.,-1.));
#711=DIRECTION('',(0.,1.,0.));
#712=DIRECTION('',(0.,0.,1.));
#713=AXIS2_PLACEMENT_3D('',#710,#711,#712);
#714=CIRCLE('',#713,2.65429999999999);
#715=CARTESIAN_POINT('',(56.,0.,1.65429999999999));
#716=VERTEX_POINT('',#715);
#717=EDGE_CURVE('E598',#716,#716,#714,.T.);
#718=ORIENTED_EDGE('',*,*,#717,.T.);
#719=EDGE_LOOP('',(#718));
#720=FACE_BOUND('',#719,.T.);
#721=ORIENTED_EDGE('',*,*,#570,.F.);
#722=ORIENTED_EDGE('',*,*,#454,.F.);
#723=ORIENTED_EDGE('',*,*,#546,.F.);
#724=ORIENTED_EDGE('',*,*,#592,.F.);
#725=ORIENTED_EDGE('',*,*,#494,.F.);
#726=ORIENTED_EDGE('',*,*,#392,.F.);
#727=EDGE_LOOP('',(#721,#722,#723,#724,#725,#726));
#728=FACE_BOUND('',#727,.T.);
#729=ADVANCED_FACE('F872',(#607,#643,#654,#665,#676,#687,#698,#709,#720,#728),#23,.T.);
#730=CARTESIAN_POINT('',(13.,5.75,0.));
#731=DIRECTION('',(0.,-1.,0.));
#732=DIRECTION('',(0.,0.,-1.));
#733=AXIS2_PLACEMENT_3D('',#730,#731,#732);
#734=PLANE('',#733);
#735=CARTESIAN_POINT('',(13.,5.75,0.));
#736=DIRECTION('',(0.,-1.,0.));
#737=DIRECTION('',(0.,0.,-1.));
#738=AXIS2_PLACEMENT_3D('',#735,#736,#737);
#739=CIRCLE('',#738,0.793749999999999);
#740=CARTESIAN_POINT('',(13.,5.75,-0.793749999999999));
#741=VERTEX_POINT('',#740);
#742=EDGE_CURVE('E464',#741,#741,#739,.T.);
#743=ORIENTED_EDGE('',*,*,#742,.T.);
#744=EDGE_LOOP('',(#743));
#745=FACE_BOUND('',#744,.T.);
#746=CARTESIAN_POINT('',(13.,5.75,0.));
#747=DIRECTION('',(0.,1.,0.));
#748=DIRECTION('',(0.,0.,1.));
#749=AXIS2_PLACEMENT_3D('',#746,#747,#748);
#750=CIRCLE('',#749,3.96874999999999);
#751=CARTESIAN_POINT('',(13.,5.75,3.96874999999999));
#752=VERTEX_POINT('',#751);
#753=EDGE_CURVE('E610',#752,#752,#750,.T.);
#754=ORIENTED_EDGE('',*,*,#753,.T.);
#755=EDGE_LOOP('',(#754));
#756=FACE_BOUND('',#755,.T.);
#757=ADVANCED_FACE('F708',(#745,#756),#734,.F.);
#758=CARTESIAN_POINT('',(13.,46.75,0.));
#759=DIRECTION('',(0.,1.,0.));
#760=DIRECTION('',(0.,0.,1.));
#761=AXIS2_PLACEMENT_3D('',#758,#759,#760);
#762=CYLINDRICAL_SURFACE('',#761,3.96874999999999);
#763=CARTESIAN_POINT('',(9.39720394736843,8.2,1.66458318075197));
#764=CARTESIAN_POINT('',(9.39720015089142,8.25151575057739,1.66457766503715));
#765=CARTESIAN_POINT('',(9.3950788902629,8.30306918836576,1.66000721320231));
#766=CARTESIAN_POINT('',(9.38689600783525,8.40432438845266,1.64211632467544));
#767=CARTESIAN_POINT('',(9.3808289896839,8.4540235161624,1.62878390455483));
#768=CARTESIAN_POINT('',(9.3656158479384,8.54973081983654,1.5945441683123));
#769=CARTESIAN_POINT('',(9.35649439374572,8.59576502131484,1.57369744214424));
#770=CARTESIAN_POINT('',(9.33611399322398,8.68382366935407,1.52564669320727));
#771=CARTESIAN_POINT('',(9.32485412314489,8.72584637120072,1.49843992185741));
#772=CARTESIAN_POINT('',(9.29592501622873,8.82301668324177,1.42580194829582));
#773=CARTESIAN_POINT('',(9.27760225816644,8.8758949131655,1.37759760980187));
#774=CARTESIAN_POINT('',(9.24060805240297,8.9729327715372,1.27320026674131));
#775=CARTESIAN_POINT('',(9.22193591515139,9.01707259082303,1.21698959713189));
#776=CARTESIAN_POINT('',(9.17966040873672,9.11080587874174,1.07835317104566));
#777=CARTESIAN_POINT('',(9.15655709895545,9.15709360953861,0.993540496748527));
#778=CARTESIAN_POINT('',(9.11514381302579,9.23603785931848,0.816790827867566));
#779=CARTESIAN_POINT('',(9.09683703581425,9.26868528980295,0.724849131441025));
#780=CARTESIAN_POINT('',(9.06623219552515,9.32178817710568,0.534684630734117));
#781=CARTESIAN_POINT('',(9.05405211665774,9.34200579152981,0.436376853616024));
#782=CARTESIAN_POINT('',(9.03709875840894,9.36986647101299,0.237427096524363));
#783=CARTESIAN_POINT('',(9.03232405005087,9.37751196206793,0.13678557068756));
#784=CARTESIAN_POINT('',(9.03037198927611,9.38066814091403,-0.0792286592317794));
#785=CARTESIAN_POINT('',(9.03438036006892,9.37428455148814,-0.194647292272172));
#786=CARTESIAN_POINT('',(9.05217122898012,9.34513518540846,-0.422799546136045));
#787=CARTESIAN_POINT('',(9.06596912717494,9.32234359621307,-0.535528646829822));
#788=CARTESIAN_POINT('',(9.10225905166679,9.25916192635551,-0.755694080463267));
#789=CARTESIAN_POINT('',(9.12482059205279,9.21863079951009,-0.863080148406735));
#790=CARTESIAN_POINT('',(9.16307756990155,9.14354831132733,-1.01577012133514));
#791=CARTESIAN_POINT('',(9.17655438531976,9.11616469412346,-1.06523598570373));
#792=CARTESIAN_POINT('',(9.20445302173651,9.05635997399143,-1.16071507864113));
#793=CARTESIAN_POINT('',(9.21887401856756,9.02394323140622,-1.20673124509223));
#794=CARTESIAN_POINT('',(9.24976278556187,8.94954927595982,-1.29976143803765));
#795=CARTESIAN_POINT('',(9.26626744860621,8.9068903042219,-1.34622509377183));
#796=CARTESIAN_POINT('',(9.29833968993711,8.81465642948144,-1.43205481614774));
#797=CARTESIAN_POINT('',(9.313908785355,8.765093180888,-1.47143259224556));
#798=CARTESIAN_POINT('',(9.33963113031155,8.66965708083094,-1.53414262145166));
#799=CARTESIAN_POINT('',(9.35024664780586,8.62499015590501,-1.55910793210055));
#800=CARTESIAN_POINT('',(9.36880331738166,8.53179268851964,-1.60185281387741));
#801=CARTESIAN_POINT('',(9.37674617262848,8.48326463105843,-1.61963696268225));
#802=CARTESIAN_POINT('',(9.38905485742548,8.3830102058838,-1.64690120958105));
#803=CARTESIAN_POINT('',(9.39339081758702,8.33126087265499,-1.65631201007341));
#804=CARTESIAN_POINT('',(9.39773227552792,8.22674071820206,-1.66573554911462));
#805=CARTESIAN_POINT('',(9.39774078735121,8.17397063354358,-1.66575482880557));
#806=CARTESIAN_POINT('',(9.39372431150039,8.07633282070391,-1.65703515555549));
#807=CARTESIAN_POINT('',(9.39022685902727,8.03133443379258,-1.64944166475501));
#808=CARTESIAN_POINT('',(9.38037237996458,7.94328833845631,-1.62770204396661));
#809=CARTESIAN_POINT('',(9.37401426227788,7.90024138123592,-1.61355341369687));
#810=CARTESIAN_POINT('',(9.35701049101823,7.8056113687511,-1.57485187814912));
#811=CARTESIAN_POINT('',(9.34566940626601,7.75488449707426,-1.54851702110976));
#812=CARTESIAN_POINT('',(9.32072722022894,7.65876582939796,-1.48828521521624));
#813=CARTESIAN_POINT('',(9.30712225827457,7.61338337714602,-1.45437531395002));
#814=CARTESIAN_POINT('',(9.27388589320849,7.51301047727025,-1.36744187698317));
#815=CARTESIAN_POINT('',(9.25383159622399,7.46034050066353,-1.31190913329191));
#816=CARTESIAN_POINT('',(9.21423270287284,7.36479083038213,-1.19285651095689));
#817=CARTESIAN_POINT('',(9.19468901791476,7.32192770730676,-1.12932339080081));
#818=CARTESIAN_POINT('',(9.15191662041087,7.23322770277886,-0.97541357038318));
#819=CARTESIAN_POINT('',(9.12947302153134,7.19072576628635,-0.882895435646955));
#820=CARTESIAN_POINT('',(9.09070596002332,7.12022188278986,-0.691363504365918));
#821=CARTESIAN_POINT('',(9.07438571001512,7.0922275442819,-0.592346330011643));
#822=CARTESIAN_POINT('',(9.0490320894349,7.04955971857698,-0.389163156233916));
#823=CARTESIAN_POINT('',(9.04010124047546,7.03507330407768,-0.284945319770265));
#824=CARTESIAN_POINT('',(9.03057042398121,7.01963452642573,-0.0751357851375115));
#825=CARTESIAN_POINT('',(9.02997230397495,7.01868516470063,0.0304562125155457));
#826=CARTESIAN_POINT('',(9.03754816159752,7.03092192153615,0.252035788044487));
#827=CARTESIAN_POINT('',(9.04667978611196,7.04565103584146,0.367909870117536));
#828=CARTESIAN_POINT('',(9.07444728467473,7.09228480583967,0.595037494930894));
#829=CARTESIAN_POINT('',(9.09308123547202,7.12418598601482,0.706291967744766));
#830=CARTESIAN_POINT('',(9.13279794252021,7.19713342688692,0.89606114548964));
#831=CARTESIAN_POINT('',(9.15238604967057,7.23450634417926,0.97630952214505));
#832=CARTESIAN_POINT('',(9.19447351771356,7.32121405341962,1.12924216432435));
#833=CARTESIAN_POINT('',(9.21696809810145,7.37052931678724,1.20193850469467));
#834=CARTESIAN_POINT('',(9.25605616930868,7.46653586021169,1.31776693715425));
#835=CARTESIAN_POINT('',(9.27254891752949,7.51013491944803,1.36349506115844));
#836=CARTESIAN_POINT('',(9.30440780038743,7.60431890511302,1.44761409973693));
#837=CARTESIAN_POINT('',(9.31977537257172,7.65489467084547,1.48601448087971));
#838=CARTESIAN_POINT('',(9.34469428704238,7.75129289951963,1.54613929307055));
#839=CARTESIAN_POINT('',(9.35478762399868,7.79584134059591,1.56967335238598));
#840=CARTESIAN_POINT('',(9.37223403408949,7.88852226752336,1.60958635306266));
#841=CARTESIAN_POINT('',(9.37959209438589,7.93664803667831,1.62597832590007));
#842=CARTESIAN_POINT('',(9.38907517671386,8.02081811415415,1.64690259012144));
#843=CARTESIAN_POINT('',(9.39210273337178,8.05625416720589,1.65350482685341));
#844=CARTESIAN_POINT('',(9.39616856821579,8.12778725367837,1.66234731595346));
#845=CARTESIAN_POINT('',(9.39720660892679,8.16388436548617,1.66458704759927));
#846=CARTESIAN_POINT('',(9.39720394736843,8.2,1.66458318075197));
#847=B_SPLINE_CURVE_WITH_KNOTS('',3,(#763,#764,#765,#766,#767,#768,#769,#770,#771,#772,#773,
#774,#775,#776,#777,#778,#779,#780,#781,#782,#783,#784,#785,#786,#787,#788,#789,#790,#791,#792,
#793,#794,#795,#796,#797,#798,#799,#800,#801,#802,#803,#804,#805,#806,#807,#808,#809,#810,#811,
#812,#813,#814,#815,#816,#817,#818,#819,#820,#821,#822,#823,#824,#825,#826,#827,#828,#829,#830,
#831,#832,#833,#834,#835,#836,#837,#838,#839,#840,#841,#842,#843,#844,#845,#846),.UNSPECIFIED.,
.T.,.F.,(4,2,2,2,2,2,2,2,2,2,2,2,2,2,2,2,2,2,2,2,2,2,2,2,2,2,2,2,2,2,2,2,2,2,2,2,2,2,2,2,2,4),
(0.,0.154380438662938,0.308972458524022,0.462344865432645,0.615783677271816,0.836144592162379,
1.05699946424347,1.35345911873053,1.6501159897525,1.95228574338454,2.25439718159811,
2.59976661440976,2.94568056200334,3.29439628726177,3.46850360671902,3.64246092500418,
3.83742222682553,4.03205833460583,4.18823539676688,4.34431274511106,4.50167008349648,
4.65891782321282,4.79559369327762,4.93232173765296,5.10617739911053,5.28033263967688,
5.5164051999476,5.75287375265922,6.06401253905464,6.37531433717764,6.69086600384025,
7.0064876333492,7.35631283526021,7.70606726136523,7.9771164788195,8.2477254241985,
8.44299159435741,8.63800377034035,8.79157251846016,8.94485987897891,9.05307692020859,
9.16130687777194),.UNSPECIFIED.);
#848=CARTESIAN_POINT('',(9.39720394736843,8.2,1.66458318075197));
#849=VERTEX_POINT('',#848);
#850=EDGE_CURVE('E502',#849,#849,#847,.T.);
#851=ORIENTED_EDGE('',*,*,#850,.T.);
#852=EDGE_LOOP('',(#851));
#853=FACE_BOUND('',#852,.T.);
#854=ORIENTED_EDGE('',*,*,#753,.F.);
#855=EDGE_LOOP('',(#854));
#856=FACE_BOUND('',#855,.T.);
#857=DIRECTION('',(0.,1.,0.));
#858=VECTOR('',#857,1.);
#859=CARTESIAN_POINT('',(10.4767756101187,43.5,3.06338297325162));
#860=LINE('',#859,#858);
#861=CARTESIAN_POINT('',(10.4767756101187,40.25,3.06338297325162));
#862=VERTEX_POINT('',#861);
#863=CARTESIAN_POINT('',(10.4767756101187,46.5,3.06338297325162));
#864=VERTEX_POINT('',#863);
#865=EDGE_CURVE('E813',#862,#864,#860,.T.);
#866=ORIENTED_EDGE('',*,*,#865,.T.);
#867=CARTESIAN_POINT('',(13.,46.5,0.));
#868=DIRECTION('',(0.,-1.,0.));
#869=DIRECTION('',(0.,0.,-1.));
#870=AXIS2_PLACEMENT_3D('',#867,#868,#869);
#871=CIRCLE('',#870,3.96874999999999);
#872=CARTESIAN_POINT('',(9.48178817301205,46.5,1.83661702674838));
#873=VERTEX_POINT('',#872);
#874=EDGE_CURVE('E792',#864,#873,#871,.F.);
#875=ORIENTED_EDGE('',*,*,#874,.T.);
#876=DIRECTION('',(0.,1.,0.));
#877=VECTOR('',#876,1.);
#878=CARTESIAN_POINT('',(9.48178817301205,43.5,1.83661702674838));
#879=LINE('',#878,#877);
#880=CARTESIAN_POINT('',(9.48178817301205,40.25,1.83661702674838));
#881=VERTEX_POINT('',#880);
#882=EDGE_CURVE('E730',#873,#881,#879,.F.);
#883=ORIENTED_EDGE('',*,*,#882,.T.);
#884=CARTESIAN_POINT('',(9.91763458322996,39.7730668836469,2.5));
#885=CARTESIAN_POINT('',(9.91763064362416,39.7730706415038,2.49999514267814));
#886=CARTESIAN_POINT('',(9.91762670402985,39.7730743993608,2.49999028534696));
#887=CARTESIAN_POINT('',(9.91758676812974,39.7731124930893,2.49994104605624));
#888=CARTESIAN_POINT('',(9.91755077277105,39.773146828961,2.49989666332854));
#889=CARTESIAN_POINT('',(9.91737080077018,39.7733185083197,2.49967474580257));
#890=CARTESIAN_POINT('',(9.91722683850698,39.773455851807,2.49949719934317));
#891=CARTESIAN_POINT('',(9.91650710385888,39.774142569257,2.49860940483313));
#892=CARTESIAN_POINT('',(9.9159315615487,39.7746919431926,2.49789897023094));
#893=CARTESIAN_POINT('',(9.91305507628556,39.777438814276,2.49434580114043));
#894=CARTESIAN_POINT('',(9.9107578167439,39.7796363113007,2.49150008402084));
#895=CARTESIAN_POINT('',(9.89929110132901,39.7906238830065,2.4772555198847));
#896=CARTESIAN_POINT('',(9.89018068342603,39.7994139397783,2.46580909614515));
#897=CARTESIAN_POINT('',(9.84493988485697,39.8433697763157,2.40831835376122));
#898=CARTESIAN_POINT('',(9.80976202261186,39.8785344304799,2.36152115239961));
#899=CARTESIAN_POINT('',(9.63872683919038,40.0547175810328,2.12319684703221));
#900=CARTESIAN_POINT('',(9.51864161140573,40.1956633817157,1.9201462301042));
#901=CARTESIAN_POINT('',(9.41726955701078,40.3362982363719,1.70734271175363));
#902=B_SPLINE_CURVE_WITH_KNOTS('',3,(#884,#885,#886,#887,#888,#889,#890,#891,#892,#893,#894,
#895,#896,#897,#898,#899,#900,#901),.UNSPECIFIED.,.F.,.F.,(4,2,2,2,2,2,2,2,4),(0.,
2.18888104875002E-05,0.000221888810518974,0.00102188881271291,0.00422188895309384,
0.0170218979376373,0.0682224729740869,0.273059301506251,1.09464358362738),.UNSPECIFIED.);
#903=CARTESIAN_POINT('',(9.91763458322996,39.7730668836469,2.5));
#904=VERTEX_POINT('',#903);
#905=EDGE_CURVE('E714',#881,#904,#902,.F.);
#906=ORIENTED_EDGE('',*,*,#905,.T.);
#907=CARTESIAN_POINT('',(9.91763458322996,39.7730668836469,2.5));
#908=CARTESIAN_POINT('',(9.91763852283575,39.7730706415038,2.50000485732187));
#909=CARTESIAN_POINT('',(9.91764246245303,39.7730743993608,2.50000971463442));
#910=CARTESIAN_POINT('',(9.91768239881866,39.7731124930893,2.50005895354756));
#911=CARTESIAN_POINT('',(9.91771839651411,39.773146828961,2.50010333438));
#912=CARTESIAN_POINT('',(9.91789838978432,39.7733185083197,2.50032523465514));
#913=CARTESIAN_POINT('',(9.91804239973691,39.773455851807,2.50050274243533));
#914=CARTESIAN_POINT('',(9.91876252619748,39.7741425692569,2.50139021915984));
#915=CARTESIAN_POINT('',(9.91933887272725,39.7746919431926,2.50210000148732));
#916=CARTESIAN_POINT('',(9.92222183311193,39.777438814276,2.50564791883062));
#917=CARTESIAN_POINT('',(9.92453212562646,39.7796363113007,2.50848306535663));
#918=CARTESIAN_POINT('',(9.93610326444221,39.7906238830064,2.52264293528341));
#919=CARTESIAN_POINT('',(9.94542284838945,39.7994139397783,2.53391971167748));
#920=CARTESIAN_POINT('',(9.99233807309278,39.8433697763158,2.59005238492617));
#921=CARTESIAN_POINT('',(10.0308669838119,39.87853443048,2.63413166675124));
#922=CARTESIAN_POINT('',(10.2287583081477,40.0547175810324,2.85067388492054));
#923=CARTESIAN_POINT('',(10.4026514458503,40.1956633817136,3.01008276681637));
#924=CARTESIAN_POINT('',(10.5899498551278,40.3362982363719,3.15319439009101));
#925=B_SPLINE_CURVE_WITH_KNOTS('',3,(#907,#908,#909,#910,#911,#912,#913,#914,#915,#916,#917,
#918,#919,#920,#921,#922,#923,#924),.UNSPECIFIED.,.F.,.F.,(4,2,2,2,2,2,2,2,4),(0.,
2.18888104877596E-05,0.000221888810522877,0.00102188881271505,0.00422188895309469,
0.0170218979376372,0.06822247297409,0.273059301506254,1.09464358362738),.UNSPECIFIED.);
#926=EDGE_CURVE('E723',#904,#862,#925,.T.);
#927=ORIENTED_EDGE('',*,*,#926,.T.);
#928=EDGE_LOOP('',(#866,#875,#883,#906,#927));
#929=FACE_BOUND('',#928,.T.);
#930=ADVANCED_FACE('F703',(#853,#856,#929),#762,.F.);
#931=CARTESIAN_POINT('',(24.6666666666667,5.75,0.));
#932=DIRECTION('',(0.,-1.,0.));
#933=DIRECTION('',(0.,0.,-1.));
#934=AXIS2_PLACEMENT_3D('',#931,#932,#933);
#935=PLANE('',#934);
#936=CARTESIAN_POINT('',(26.67,5.75,-1.5));
#937=DIRECTION('',(0.,-1.,0.));
#938=DIRECTION('',(0.,0.,-1.));
#939=AXIS2_PLACEMENT_3D('',#936,#937,#938);
#940=CIRCLE('',#939,0.396874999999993);
#941=CARTESIAN_POINT('',(26.67,5.75,-1.89687499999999));
#942=VERTEX_POINT('',#941);
#943=EDGE_CURVE('E430',#942,#942,#940,.T.);
#944=ORIENTED_EDGE('',*,*,#943,.T.);
#945=EDGE_LOOP('',(#944));
#946=FACE_BOUND('',#945,.T.);
#947=CARTESIAN_POINT('',(24.6666666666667,5.75,0.));
#948=DIRECTION('',(0.,1.,0.));
#949=DIRECTION('',(0.,0.,1.));
#950=AXIS2_PLACEMENT_3D('',#947,#948,#949);
#951=CIRCLE('',#950,3.96874999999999);
#952=CARTESIAN_POINT('',(24.6666666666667,5.75,3.96874999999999));
#953=VERTEX_POINT('',#952);
#954=EDGE_CURVE('E607',#953,#953,#951,.T.);
#955=ORIENTED_EDGE('',*,*,#954,.T.);
#956=EDGE_LOOP('',(#955));
#957=FACE_BOUND('',#956,.T.);
#958=ADVANCED_FACE('F699',(#946,#957),#935,.F.);
#959=CARTESIAN_POINT('',(24.6666666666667,46.75,0.));
#960=DIRECTION('',(0.,1.,0.));
#961=DIRECTION('',(0.,0.,1.));
#962=AXIS2_PLACEMENT_3D('',#959,#960,#961);
#963=CYLINDRICAL_SURFACE('',#962,3.96874999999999);
#964=CARTESIAN_POINT('',(24.6666666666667,46.5,0.));
#965=DIRECTION('',(0.,-1.,0.));
#966=DIRECTION('',(0.,0.,-1.));
#967=AXIS2_PLACEMENT_3D('',#964,#965,#966);
#968=CIRCLE('',#967,3.96874999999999);
#969=CARTESIAN_POINT('',(24.6666666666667,46.5,-3.96874999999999));
#970=VERTEX_POINT('',#969);
#971=EDGE_CURVE('E794',#970,#970,#968,.F.);
#972=ORIENTED_EDGE('',*,*,#971,.T.);
#973=EDGE_LOOP('',(#972));
#974=FACE_BOUND('',#973,.T.);
#975=ORIENTED_EDGE('',*,*,#954,.F.);
#976=EDGE_LOOP('',(#975));
#977=FACE_BOUND('',#976,.T.);
#978=ADVANCED_FACE('F695',(#974,#977),#963,.F.);
#979=CARTESIAN_POINT('',(36.3333333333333,5.75,0.));
#980=DIRECTION('',(0.,-1.,0.));
#981=DIRECTION('',(0.,0.,-1.));
#982=AXIS2_PLACEMENT_3D('',#979,#980,#981);
#983=PLANE('',#982);
#984=CARTESIAN_POINT('',(38.33,5.75,-1.5));
#985=DIRECTION('',(0.,-1.,0.));
#986=DIRECTION('',(0.,0.,-1.));
#987=AXIS2_PLACEMENT_3D('',#984,#985,#986);
#988=CIRCLE('',#987,0.396874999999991);
#989=CARTESIAN_POINT('',(38.33,5.75,-1.89687499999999));
#990=VERTEX_POINT('',#989);
#991=EDGE_CURVE('E412',#990,#990,#988,.T.);
#992=ORIENTED_EDGE('',*,*,#991,.T.);
#993=EDGE_LOOP('',(#992));
#994=FACE_BOUND('',#993,.T.);
#995=CARTESIAN_POINT('',(34.33,5.75,-1.5));
#996=DIRECTION('',(0.,-1.,0.));
#997=DIRECTION('',(0.,0.,-1.));
#998=AXIS2_PLACEMENT_3D('',#995,#996,#997);
#999=CIRCLE('',#998,0.396874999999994);
#1000=CARTESIAN_POINT('',(34.33,5.75,-1.89687499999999));
#1001=VERTEX_POINT('',#1000);
#1002=EDGE_CURVE('E424',#1001,#1001,#999,.T.);
#1003=ORIENTED_EDGE('',*,*,#1002,.T.);
#1004=EDGE_LOOP('',(#1003));
#1005=FACE_BOUND('',#1004,.T.);
#1006=CARTESIAN_POINT('',(36.3333333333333,5.75,0.));
#1007=DIRECTION('',(0.,1.,0.));
#1008=DIRECTION('',(0.,0.,1.));
#1009=AXIS2_PLACEMENT_3D('',#1006,#1007,#1008);
#1010=CIRCLE('',#1009,3.96874999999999);
#1011=CARTESIAN_POINT('',(36.3333333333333,5.75,3.96874999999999));
#1012=VERTEX_POINT('',#1011);
#1013=EDGE_CURVE('E604',#1012,#1012,#1010,.T.);
#1014=ORIENTED_EDGE('',*,*,#1013,.T.);
#1015=EDGE_LOOP('',(#1014));
#1016=FACE_BOUND('',#1015,.T.);
#1017=ADVANCED_FACE('F691',(#994,#1005,#1016),#983,.F.);
#1018=CARTESIAN_POINT('',(36.3333333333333,46.75,0.));
#1019=DIRECTION('',(0.,1.,0.));
#1020=DIRECTION('',(0.,0.,1.));
#1021=AXIS2_PLACEMENT_3D('',#1018,#1019,#1020);
#1022=CYLINDRICAL_SURFACE('',#1021,3.96874999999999);
#1023=CARTESIAN_POINT('',(36.3333333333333,46.5,0.));
#1024=DIRECTION('',(0.,-1.,0.));
#1025=DIRECTION('',(0.,0.,-1.));
#1026=AXIS2_PLACEMENT_3D('',#1023,#1024,#1025);
#1027=CIRCLE('',#1026,3.96874999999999);
#1028=CARTESIAN_POINT('',(36.3333333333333,46.5,-3.96874999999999));
#1029=VERTEX_POINT('',#1028);
#1030=EDGE_CURVE('E762',#1029,#1029,#1027,.F.);
#1031=ORIENTED_EDGE('',*,*,#1030,.T.);
#1032=EDGE_LOOP('',(#1031));
#1033=FACE_BOUND('',#1032,.T.);
#1034=ORIENTED_EDGE('',*,*,#1013,.F.);
#1035=EDGE_LOOP('',(#1034));
#1036=FACE_BOUND('',#1035,.T.);
#1037=ADVANCED_FACE('F687',(#1033,#1036),#1022,.F.);
#1038=CARTESIAN_POINT('',(48.,5.75,0.));
#1039=DIRECTION('',(0.,-1.,0.));
#1040=DIRECTION('',(0.,0.,-1.));
#1041=AXIS2_PLACEMENT_3D('',#1038,#1039,#1040);
#1042=PLANE('',#1041);
#1043=CARTESIAN_POINT('',(48.7,5.75,-0.8));
#1044=DIRECTION('',(0.,-1.,0.));
#1045=DIRECTION('',(0.,0.,-1.));
#1046=AXIS2_PLACEMENT_3D('',#1043,#1044,#1045);
#1047=CIRCLE('',#1046,0.396874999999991);
#1048=CARTESIAN_POINT('',(48.7,5.75,-1.19687499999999));
#1049=VERTEX_POINT('',#1048);
#1050=EDGE_CURVE('E436',#1049,#1049,#1047,.T.);
#1051=ORIENTED_EDGE('',*,*,#1050,.T.);
#1052=EDGE_LOOP('',(#1051));
#1053=FACE_BOUND('',#1052,.T.);
#1054=CARTESIAN_POINT('',(48.,5.75,0.));
#1055=DIRECTION('',(0.,1.,0.));
#1056=DIRECTION('',(0.,0.,1.));
#1057=AXIS2_PLACEMENT_3D('',#1054,#1055,#1056);
#1058=CIRCLE('',#1057,3.96874999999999);
#1059=CARTESIAN_POINT('',(48.,5.75,3.96874999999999));
#1060=VERTEX_POINT('',#1059);
#1061=EDGE_CURVE('E601',#1060,#1060,#1058,.T.);
#1062=ORIENTED_EDGE('',*,*,#1061,.T.);
#1063=EDGE_LOOP('',(#1062));
#1064=FACE_BOUND('',#1063,.T.);
#1065=ADVANCED_FACE('F681',(#1053,#1064),#1042,.F.);
#1066=CARTESIAN_POINT('',(48.,46.75,0.));
#1067=DIRECTION('',(0.,1.,0.));
#1068=DIRECTION('',(0.,0.,1.));
#1069=AXIS2_PLACEMENT_3D('',#1066,#1067,#1068);
#1070=CYLINDRICAL_SURFACE('',#1069,3.96874999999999);
#1071=ORIENTED_EDGE('',*,*,#1061,.F.);
#1072=EDGE_LOOP('',(#1071));
#1073=FACE_BOUND('',#1072,.T.);
#1074=DIRECTION('',(0.,1.,0.));
#1075=VECTOR('',#1074,1.);
#1076=CARTESIAN_POINT('',(45.4767756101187,43.5,3.06338297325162));
#1077=LINE('',#1076,#1075);
#1078=CARTESIAN_POINT('',(45.4767756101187,40.25,3.06338297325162));
#1079=VERTEX_POINT('',#1078);
#1080=CARTESIAN_POINT('',(45.4767756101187,46.5,3.06338297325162));
#1081=VERTEX_POINT('',#1080);
#1082=EDGE_CURVE('E1730',#1079,#1081,#1077,.T.);
#1083=ORIENTED_EDGE('',*,*,#1082,.T.);
#1084=CARTESIAN_POINT('',(48.,46.5,0.));
#1085=DIRECTION('',(0.,-1.,0.));
#1086=DIRECTION('',(0.,0.,-1.));
#1087=AXIS2_PLACEMENT_3D('',#1084,#1085,#1086);
#1088=CIRCLE('',#1087,3.96874999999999);
#1089=CARTESIAN_POINT('',(44.481788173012,46.5,1.83661702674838));
#1090=VERTEX_POINT('',#1089);
#1091=EDGE_CURVE('E1720',#1081,#1090,#1088,.F.);
#1092=ORIENTED_EDGE('',*,*,#1091,.T.);
#1093=DIRECTION('',(0.,1.,0.));
#1094=VECTOR('',#1093,1.);
#1095=CARTESIAN_POINT('',(44.481788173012,43.5,1.83661702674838));
#1096=LINE('',#1095,#1094);
#1097=CARTESIAN_POINT('',(44.481788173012,40.25,1.83661702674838));
#1098=VERTEX_POINT('',#1097);
#1099=EDGE_CURVE('E1732',#1090,#1098,#1096,.F.);
#1100=ORIENTED_EDGE('',*,*,#1099,.T.);
#1101=CARTESIAN_POINT('',(44.91763458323,39.7730668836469,2.5));
#1102=CARTESIAN_POINT('',(44.9176306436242,39.7730706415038,2.49999514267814));
#1103=CARTESIAN_POINT('',(44.9176267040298,39.7730743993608,2.49999028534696));
#1104=CARTESIAN_POINT('',(44.9175867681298,39.7731124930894,2.49994104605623));
#1105=CARTESIAN_POINT('',(44.9175507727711,39.773146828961,2.49989666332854));
#1106=CARTESIAN_POINT('',(44.9173708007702,39.7733185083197,2.49967474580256));
#1107=CARTESIAN_POINT('',(44.917226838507,39.773455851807,2.49949719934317));
#1108=CARTESIAN_POINT('',(44.9165071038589,39.774142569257,2.49860940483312));
#1109=CARTESIAN_POINT('',(44.9159315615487,39.7746919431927,2.49789897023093));
#1110=CARTESIAN_POINT('',(44.9130550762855,39.7774388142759,2.49434580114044));
#1111=CARTESIAN_POINT('',(44.9107578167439,39.7796363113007,2.49150008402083));
#1112=CARTESIAN_POINT('',(44.8992911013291,39.7906238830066,2.47725551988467));
#1113=CARTESIAN_POINT('',(44.8901806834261,39.7994139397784,2.46580909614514));
#1114=CARTESIAN_POINT('',(44.8449398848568,39.8433697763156,2.40831835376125));
#1115=CARTESIAN_POINT('',(44.8097620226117,39.8785344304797,2.36152115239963));
#1116=CARTESIAN_POINT('',(44.638726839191,40.0547175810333,2.12319684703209));
#1117=CARTESIAN_POINT('',(44.5186416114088,40.1956633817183,1.92014623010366));
#1118=CARTESIAN_POINT('',(44.4172695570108,40.3362982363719,1.70734271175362));
#1119=B_SPLINE_CURVE_WITH_KNOTS('',3,(#1101,#1102,#1103,#1104,#1105,#1106,#1107,#1108,#1109,
#1110,#1111,#1112,#1113,#1114,#1115,#1116,#1117,#1118),.UNSPECIFIED.,.F.,.F.,(4,2,2,2,2,2,2,2,
4),(0.,2.18888104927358E-05,0.000221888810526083,0.0010218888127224,0.00422188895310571,
0.0170218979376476,0.068222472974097,0.273059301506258,1.09464358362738),.UNSPECIFIED.);
#1120=CARTESIAN_POINT('',(44.91763458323,39.7730668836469,2.5));
#1121=VERTEX_POINT('',#1120);
#1122=EDGE_CURVE('E656',#1098,#1121,#1119,.F.);
#1123=ORIENTED_EDGE('',*,*,#1122,.T.);
#1124=CARTESIAN_POINT('',(44.91763458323,39.7730668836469,2.5));
#1125=CARTESIAN_POINT('',(44.9176385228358,39.7730706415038,2.50000485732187));
#1126=CARTESIAN_POINT('',(44.917642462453,39.7730743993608,2.50000971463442));
#1127=CARTESIAN_POINT('',(44.9176823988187,39.7731124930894,2.50005895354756));
#1128=CARTESIAN_POINT('',(44.9177183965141,39.773146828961,2.50010333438));
#1129=CARTESIAN_POINT('',(44.9178983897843,39.7733185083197,2.50032523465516));
#1130=CARTESIAN_POINT('',(44.9180423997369,39.773455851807,2.50050274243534));
#1131=CARTESIAN_POINT('',(44.9187625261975,39.774142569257,2.50139021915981));
#1132=CARTESIAN_POINT('',(44.9193388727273,39.7746919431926,2.50210000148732));
#1133=CARTESIAN_POINT('',(44.9222218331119,39.777438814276,2.50564791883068));
#1134=CARTESIAN_POINT('',(44.9245321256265,39.7796363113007,2.50848306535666));
#1135=CARTESIAN_POINT('',(44.9361032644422,39.7906238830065,2.52264293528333));
#1136=CARTESIAN_POINT('',(44.9454228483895,39.7994139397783,2.53391971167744));
#1137=CARTESIAN_POINT('',(44.9923380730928,39.8433697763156,2.59005238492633));
#1138=CARTESIAN_POINT('',(45.0308669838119,39.8785344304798,2.63413166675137));
#1139=CARTESIAN_POINT('',(45.2287583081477,40.054717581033,2.85067388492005));
#1140=CARTESIAN_POINT('',(45.4026514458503,40.1956633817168,3.01008276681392));
#1141=CARTESIAN_POINT('',(45.5899498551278,40.3362982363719,3.15319439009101));
#1142=B_SPLINE_CURVE_WITH_KNOTS('',3,(#1124,#1125,#1126,#1127,#1128,#1129,#1130,#1131,#1132,
#1133,#1134,#1135,#1136,#1137,#1138,#1139,#1140,#1141),.UNSPECIFIED.,.F.,.F.,(4,2,2,2,2,2,2,2,
4),(0.,2.18888104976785E-05,0.000221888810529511,0.00102188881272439,0.00422188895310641,
0.0170218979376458,0.0682224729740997,0.273059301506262,1.09464358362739),.UNSPECIFIED.);
#1143=EDGE_CURVE('E665',#1121,#1079,#1142,.T.);
#1144=ORIENTED_EDGE('',*,*,#1143,.T.);
#1145=EDGE_LOOP('',(#1083,#1092,#1100,#1123,#1144));
#1146=FACE_BOUND('',#1145,.T.);
#1147=ADVANCED_FACE('F675',(#1073,#1146),#1070,.F.);
#1148=CARTESIAN_POINT('',(56.,46.75,-1.));
#1149=DIRECTION('',(0.,1.,0.));
#1150=DIRECTION('',(0.,0.,1.));
#1151=AXIS2_PLACEMENT_3D('',#1148,#1149,#1150);
#1152=CYLINDRICAL_SURFACE('',#1151,2.65429999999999);
#1153=CARTESIAN_POINT('',(56.,46.5,-1.));
#1154=DIRECTION('',(0.,-1.,0.));
#1155=DIRECTION('',(0.,0.,-1.));
#1156=AXIS2_PLACEMENT_3D('',#1153,#1154,#1155);
#1157=CIRCLE('',#1156,2.65429999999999);
#1158=CARTESIAN_POINT('',(56.,46.5,-3.65429999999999));
#1159=VERTEX_POINT('',#1158);
#1160=EDGE_CURVE('E818',#1159,#1159,#1157,.F.);
#1161=ORIENTED_EDGE('',*,*,#1160,.T.);
#1162=EDGE_LOOP('',(#1161));
#1163=FACE_BOUND('',#1162,.T.);
#1164=ORIENTED_EDGE('',*,*,#717,.F.);
#1165=EDGE_LOOP('',(#1164));
#1166=FACE_BOUND('',#1165,.T.);
#1167=ADVANCED_FACE('F680',(#1163,#1166),#1152,.F.);
#1168=CARTESIAN_POINT('',(7.,6.75,-6.));
#1169=DIRECTION('',(-1.,0.,0.));
#1170=DIRECTION('',(0.,0.,1.));
#1171=AXIS2_PLACEMENT_3D('',#1168,#1169,#1170);
#1172=PLANE('',#1171);
#1173=ORIENTED_EDGE('',*,*,#243,.F.);
#1174=ORIENTED_EDGE('',*,*,#484,.F.);
#1175=DIRECTION('',(0.,0.,1.));
#1176=VECTOR('',#1175,1.);
#1177=CARTESIAN_POINT('',(7.,6.75,-6.));
#1178=LINE('',#1177,#1176);
#1179=EDGE_CURVE('E583',#483,#523,#1178,.T.);
#1180=ORIENTED_EDGE('',*,*,#1179,.T.);
#1181=ORIENTED_EDGE('',*,*,#524,.T.);
#1182=EDGE_LOOP('',(#1173,#1174,#1180,#1181));
#1183=FACE_BOUND('',#1182,.T.);
#1184=ADVANCED_FACE('F1381',(#1183),#1172,.T.);
#1185=CARTESIAN_POINT('',(7.,6.75,-6.));
#1186=DIRECTION('',(0.,-1.,0.));
#1187=DIRECTION('',(0.,0.,-1.));
#1188=AXIS2_PLACEMENT_3D('',#1185,#1186,#1187);
#1189=PLANE('',#1188);
#1190=CARTESIAN_POINT('',(3.5,6.75,0.));
#1191=DIRECTION('',(0.,1.,0.));
#1192=DIRECTION('',(0.,0.,1.));
#1193=AXIS2_PLACEMENT_3D('',#1190,#1191,#1192);
#1194=CIRCLE('',#1193,1.35);
#1195=CARTESIAN_POINT('',(3.5,6.75,1.35));
#1196=VERTEX_POINT('',#1195);
#1197=EDGE_CURVE('E551',#1196,#1196,#1194,.T.);
#1198=ORIENTED_EDGE('',*,*,#1197,.F.);
#1199=EDGE_LOOP('',(#1198));
#1200=FACE_BOUND('',#1199,.T.);
#1201=ORIENTED_EDGE('',*,*,#508,.F.);
#1202=ORIENTED_EDGE('',*,*,#585,.F.);
#1203=ORIENTED_EDGE('',*,*,#532,.F.);
#1204=ORIENTED_EDGE('',*,*,#1179,.F.);
#1205=EDGE_LOOP('',(#1201,#1202,#1203,#1204));
#1206=FACE_BOUND('',#1205,.T.);
#1207=ADVANCED_FACE('F1515',(#1200,#1206),#1189,.F.);
#1208=CARTESIAN_POINT('',(69.58,6.75,-3.71685445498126));
#1209=DIRECTION('',(0.,-1.,0.));
#1210=DIRECTION('',(0.,0.,-1.));
#1211=AXIS2_PLACEMENT_3D('',#1208,#1209,#1210);
#1212=PLANE('',#1211);
#1213=CARTESIAN_POINT('',(66.,6.75,0.));
#1214=DIRECTION('',(0.,1.,0.));
#1215=DIRECTION('',(0.,0.,1.));
#1216=AXIS2_PLACEMENT_3D('',#1213,#1214,#1215);
#1217=CIRCLE('',#1216,1.35);
#1218=CARTESIAN_POINT('',(66.,6.75,1.35000000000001));
#1219=VERTEX_POINT('',#1218);
#1220=EDGE_CURVE('E557',#1219,#1219,#1217,.T.);
#1221=ORIENTED_EDGE('',*,*,#1220,.F.);
#1222=EDGE_LOOP('',(#1221));
#1223=FACE_BOUND('',#1222,.T.);
#1224=DIRECTION('',(0.,0.,-1.));
#1225=VECTOR('',#1224,1.);
#1226=CARTESIAN_POINT('',(62.58,6.75,-3.71685445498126));
#1227=LINE('',#1226,#1225);
#1228=EDGE_CURVE('E567',#436,#367,#1227,.T.);
#1229=ORIENTED_EDGE('',*,*,#1228,.F.);
#1230=ORIENTED_EDGE('',*,*,#468,.F.);
#1231=ORIENTED_EDGE('',*,*,#563,.F.);
#1232=ORIENTED_EDGE('',*,*,#376,.F.);
#1233=EDGE_LOOP('',(#1229,#1230,#1231,#1232));
#1234=FACE_BOUND('',#1233,.T.);
#1235=ADVANCED_FACE('F1510',(#1223,#1234),#1212,.F.);
#1236=CARTESIAN_POINT('',(62.58,6.75,-3.71685445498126));
#1237=DIRECTION('',(1.,0.,0.));
#1238=DIRECTION('',(0.,0.,-1.));
#1239=AXIS2_PLACEMENT_3D('',#1236,#1237,#1238);
#1240=PLANE('',#1239);
#1241=DIRECTION('',(0.,1.,0.));
#1242=VECTOR('',#1241,1.);
#1243=CARTESIAN_POINT('',(62.58,38.,0.));
#1244=LINE('',#1243,#1242);
#1245=CARTESIAN_POINT('',(62.58,12.2,0.));
#1246=VERTEX_POINT('',#1245);
#1247=CARTESIAN_POINT('',(62.58,39.8,0.));
#1248=VERTEX_POINT('',#1247);
#1249=EDGE_CURVE('E270',#1246,#1248,#1244,.T.);
#1250=ORIENTED_EDGE('',*,*,#1249,.T.);
#1251=DIRECTION('',(0.,0.,1.));
#1252=VECTOR('',#1251,1.);
#1253=CARTESIAN_POINT('',(62.58,39.8,-3.71685445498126));
#1254=LINE('',#1253,#1252);
#1255=EDGE_CURVE('E303',#1248,#312,#1254,.F.);
#1256=ORIENTED_EDGE('',*,*,#1255,.T.);
#1257=ORIENTED_EDGE('',*,*,#313,.T.);
#1258=ORIENTED_EDGE('',*,*,#219,.F.);
#1259=ORIENTED_EDGE('',*,*,#437,.F.);
#1260=ORIENTED_EDGE('',*,*,#1228,.T.);
#1261=ORIENTED_EDGE('',*,*,#368,.T.);
#1262=DIRECTION('',(0.,0.,-1.));
#1263=VECTOR('',#1262,1.);
#1264=CARTESIAN_POINT('',(62.58,12.2,-3.71685445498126));
#1265=LINE('',#1264,#1263);
#1266=EDGE_CURVE('E263',#1246,#363,#1265,.T.);
#1267=ORIENTED_EDGE('',*,*,#1266,.F.);
#1268=EDGE_LOOP('',(#1250,#1256,#1257,#1258,#1259,#1260,#1261,#1267));
#1269=FACE_BOUND('',#1268,.T.);
#1270=ADVANCED_FACE('F279',(#1269),#1240,.T.);
#1271=CARTESIAN_POINT('',(66.,6.75,0.));
#1272=DIRECTION('',(0.,1.,0.));
#1273=DIRECTION('',(0.,0.,1.));
#1274=AXIS2_PLACEMENT_3D('',#1271,#1272,#1273);
#1275=CYLINDRICAL_SURFACE('',#1274,1.35);
#1276=ORIENTED_EDGE('',*,*,#706,.F.);
#1277=EDGE_LOOP('',(#1276));
#1278=FACE_BOUND('',#1277,.T.);
#1279=ORIENTED_EDGE('',*,*,#1220,.T.);
#1280=EDGE_LOOP('',(#1279));
#1281=FACE_BOUND('',#1280,.T.);
#1282=ADVANCED_FACE('F1493',(#1278,#1281),#1275,.F.);
#1283=CARTESIAN_POINT('',(3.5,6.75,0.));
#1284=DIRECTION('',(0.,1.,0.));
#1285=DIRECTION('',(0.,0.,1.));
#1286=AXIS2_PLACEMENT_3D('',#1283,#1284,#1285);
#1287=CYLINDRICAL_SURFACE('',#1286,1.35);
#1288=ORIENTED_EDGE('',*,*,#695,.F.);
#1289=EDGE_LOOP('',(#1288));
#1290=FACE_BOUND('',#1289,.T.);
#1291=ORIENTED_EDGE('',*,*,#1197,.T.);
#1292=EDGE_LOOP('',(#1291));
#1293=FACE_BOUND('',#1292,.T.);
#1294=ADVANCED_FACE('F1483',(#1290,#1293),#1287,.F.);
#1295=CARTESIAN_POINT('',(62.,4.5,0.));
#1296=DIRECTION('',(0.,1.,0.));
#1297=DIRECTION('',(0.,0.,1.));
#1298=AXIS2_PLACEMENT_3D('',#1295,#1296,#1297);
#1299=PLANE('',#1298);
#1300=CARTESIAN_POINT('',(62.,4.5,0.));
#1301=DIRECTION('',(0.,-1.,0.));
#1302=DIRECTION('',(0.,0.,-1.));
#1303=AXIS2_PLACEMENT_3D('',#1300,#1301,#1302);
#1304=CIRCLE('',#1303,0.793749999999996);
#1305=CARTESIAN_POINT('',(62.,4.5,-0.793749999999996));
#1306=VERTEX_POINT('',#1305);
#1307=EDGE_CURVE('E548',#1306,#1306,#1304,.T.);
#1308=ORIENTED_EDGE('',*,*,#1307,.T.);
#1309=EDGE_LOOP('',(#1308));
#1310=FACE_BOUND('',#1309,.T.);
#1311=ADVANCED_FACE('F1473',(#1310),#1299,.F.);
#1312=CARTESIAN_POINT('',(62.,0.,0.));
#1313=DIRECTION('',(0.,-1.,0.));
#1314=DIRECTION('',(0.,0.,-1.));
#1315=AXIS2_PLACEMENT_3D('',#1312,#1313,#1314);
#1316=CYLINDRICAL_SURFACE('',#1315,0.793749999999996);
#1317=ORIENTED_EDGE('',*,*,#1307,.F.);
#1318=EDGE_LOOP('',(#1317));
#1319=FACE_BOUND('',#1318,.T.);
#1320=ORIENTED_EDGE('',*,*,#684,.T.);
#1321=EDGE_LOOP('',(#1320));
#1322=FACE_BOUND('',#1321,.T.);
#1323=ADVANCED_FACE('F1463',(#1319,#1322),#1316,.F.);
#1324=CARTESIAN_POINT('',(8.,4.5,0.));
#1325=DIRECTION('',(0.,1.,0.));
#1326=DIRECTION('',(0.,0.,1.));
#1327=AXIS2_PLACEMENT_3D('',#1324,#1325,#1326);
#1328=PLANE('',#1327);
#1329=CARTESIAN_POINT('',(8.,4.5,0.));
#1330=DIRECTION('',(0.,-1.,0.));
#1331=DIRECTION('',(0.,0.,-1.));
#1332=AXIS2_PLACEMENT_3D('',#1329,#1330,#1331);
#1333=CIRCLE('',#1332,0.793749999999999);
#1334=CARTESIAN_POINT('',(8.,4.5,-0.793749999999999));
#1335=VERTEX_POINT('',#1334);
#1336=EDGE_CURVE('E542',#1335,#1335,#1333,.T.);
#1337=ORIENTED_EDGE('',*,*,#1336,.T.);
#1338=EDGE_LOOP('',(#1337));
#1339=FACE_BOUND('',#1338,.T.);
#1340=ADVANCED_FACE('F1454',(#1339),#1328,.F.);
#1341=CARTESIAN_POINT('',(8.,0.,0.));
#1342=DIRECTION('',(0.,-1.,0.));
#1343=DIRECTION('',(0.,0.,-1.));
#1344=AXIS2_PLACEMENT_3D('',#1341,#1342,#1343);
#1345=CYLINDRICAL_SURFACE('',#1344,0.793749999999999);
#1346=ORIENTED_EDGE('',*,*,#1336,.F.);
#1347=EDGE_LOOP('',(#1346));
#1348=FACE_BOUND('',#1347,.T.);
#1349=ORIENTED_EDGE('',*,*,#673,.T.);
#1350=EDGE_LOOP('',(#1349));
#1351=FACE_BOUND('',#1350,.T.);
#1352=ADVANCED_FACE('F744',(#1348,#1351),#1345,.F.);
#1353=CARTESIAN_POINT('',(44.91763458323,46.75,2.5));
#1354=DIRECTION('',(0.,1.,0.));
#1355=DIRECTION('',(0.,0.,1.));
#1356=AXIS2_PLACEMENT_3D('',#1353,#1354,#1355);
#1357=CYLINDRICAL_SURFACE('',#1356,0.793749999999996);
#1358=ORIENTED_EDGE('',*,*,#1099,.F.);
#1359=CARTESIAN_POINT('',(44.481788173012,46.5,1.83661702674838));
#1360=CARTESIAN_POINT('',(44.4639660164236,46.5212195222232,1.84832814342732));
#1361=CARTESIAN_POINT('',(44.4465770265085,46.5423972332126,1.86077936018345));
#1362=CARTESIAN_POINT('',(44.4128107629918,46.5845262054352,1.88709772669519));
#1363=CARTESIAN_POINT('',(44.3964301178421,46.6054780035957,1.90095969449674));
#1364=CARTESIAN_POINT('',(44.364697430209,46.647164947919,1.93011942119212));
#1365=CARTESIAN_POINT('',(44.3493454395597,46.6679000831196,1.94541725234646));
#1366=CARTESIAN_POINT('',(44.3197215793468,46.7091521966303,1.97748999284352));
#1367=CARTESIAN_POINT('',(44.3054537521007,46.7296681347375,1.99426996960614));
#1368=CARTESIAN_POINT('',(44.2918085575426,46.75,2.01175738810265));
#1369=B_SPLINE_CURVE_WITH_KNOTS('',3,(#1359,#1360,#1361,#1362,#1363,#1364,#1365,#1366,#1367,
#1368),.UNSPECIFIED.,.F.,.F.,(4,2,2,2,4),(0.,0.0902426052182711,0.180164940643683,
0.270091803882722,0.360338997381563),.UNSPECIFIED.);
#1370=EDGE_CURVE('E756',#1090,#287,#1369,.T.);
#1371=ORIENTED_EDGE('',*,*,#1370,.T.);
#1372=ORIENTED_EDGE('',*,*,#290,.T.);
#1373=CARTESIAN_POINT('',(45.2661948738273,46.75,3.21312326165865));
#1374=CARTESIAN_POINT('',(45.286122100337,46.7296681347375,3.20338125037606));
#1375=CARTESIAN_POINT('',(45.3054856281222,46.7091521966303,3.1928839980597));
#1376=CARTESIAN_POINT('',(45.342982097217,46.6679000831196,3.17051776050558));
#1377=CARTESIAN_POINT('',(45.3611191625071,46.647164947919,3.15865377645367));
#1378=CARTESIAN_POINT('',(45.3962005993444,46.6054780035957,3.13362287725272));
#1379=CARTESIAN_POINT('',(45.4131450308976,46.5845262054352,3.1204560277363));
#1380=CARTESIAN_POINT('',(45.4458660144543,46.5423972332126,3.09284888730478));
#1381=CARTESIAN_POINT('',(45.4616381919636,46.5212195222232,3.07840422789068));
#1382=CARTESIAN_POINT('',(45.4767756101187,46.5,3.06338297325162));
#1383=B_SPLINE_CURVE_WITH_KNOTS('',3,(#1373,#1374,#1375,#1376,#1377,#1378,#1379,#1380,#1381,
#1382),.UNSPECIFIED.,.F.,.F.,(4,2,2,2,4),(0.,0.0902471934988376,0.180174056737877,
0.270096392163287,0.360338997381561),.UNSPECIFIED.);
#1384=EDGE_CURVE('E748',#289,#1081,#1383,.T.);
#1385=ORIENTED_EDGE('',*,*,#1384,.T.);
#1386=ORIENTED_EDGE('',*,*,#1082,.F.);
#1387=CARTESIAN_POINT('',(44.91763458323,40.25,2.5));
#1388=DIRECTION('',(0.,1.,0.));
#1389=DIRECTION('',(0.,0.,1.));
#1390=AXIS2_PLACEMENT_3D('',#1387,#1388,#1389);
#1391=CIRCLE('',#1390,0.793749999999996);
#1392=EDGE_CURVE('E536',#1098,#1079,#1391,.T.);
#1393=ORIENTED_EDGE('',*,*,#1392,.F.);
#1394=EDGE_LOOP('',(#1358,#1371,#1372,#1385,#1386,#1393));
#1395=FACE_BOUND('',#1394,.T.);
#1396=ADVANCED_FACE('F740',(#1395),#1357,.F.);
#1397=CARTESIAN_POINT('',(44.91763458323,40.25,2.5));
#1398=DIRECTION('',(0.,1.,0.));
#1399=DIRECTION('',(0.,0.,1.));
#1400=AXIS2_PLACEMENT_3D('',#1397,#1398,#1399);
#1401=CONICAL_SURFACE('',#1400,0.793749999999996,1.02974425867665);
#1402=ORIENTED_EDGE('',*,*,#1122,.F.);
#1403=ORIENTED_EDGE('',*,*,#1392,.T.);
#1404=ORIENTED_EDGE('',*,*,#1143,.F.);
#1405=EDGE_LOOP('',(#1402,#1403,#1404));
#1406=FACE_BOUND('',#1405,.T.);
#1407=ADVANCED_FACE('F671',(#1406),#1401,.F.);
#1408=CARTESIAN_POINT('',(9.91763458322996,46.75,2.5));
#1409=DIRECTION('',(0.,1.,0.));
#1410=DIRECTION('',(0.,0.,1.));
#1411=AXIS2_PLACEMENT_3D('',#1408,#1409,#1410);
#1412=CYLINDRICAL_SURFACE('',#1411,0.793749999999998);
#1413=ORIENTED_EDGE('',*,*,#882,.F.);
#1414=CARTESIAN_POINT('',(9.48178817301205,46.5,1.83661702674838));
#1415=CARTESIAN_POINT('',(9.46396601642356,46.5212195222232,1.84832814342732));
#1416=CARTESIAN_POINT('',(9.44657702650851,46.5423972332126,1.86077936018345));
#1417=CARTESIAN_POINT('',(9.41281076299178,46.5845262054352,1.88709772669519));
#1418=CARTESIAN_POINT('',(9.39643011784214,46.6054780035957,1.90095969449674));
#1419=CARTESIAN_POINT('',(9.36469743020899,46.647164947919,1.93011942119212));
#1420=CARTESIAN_POINT('',(9.34934543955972,46.6679000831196,1.94541725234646));
#1421=CARTESIAN_POINT('',(9.31972157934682,46.7091521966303,1.97748999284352));
#1422=CARTESIAN_POINT('',(9.30545375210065,46.7296681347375,1.99426996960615));
#1423=CARTESIAN_POINT('',(9.29180855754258,46.75,2.01175738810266));
#1424=B_SPLINE_CURVE_WITH_KNOTS('',3,(#1414,#1415,#1416,#1417,#1418,#1419,#1420,#1421,#1422,
#1423),.UNSPECIFIED.,.F.,.F.,(4,2,2,2,4),(0.,0.0902426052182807,0.180164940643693,
0.270091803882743,0.360338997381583),.UNSPECIFIED.);
#1425=EDGE_CURVE('E284',#873,#267,#1424,.T.);
#1426=ORIENTED_EDGE('',*,*,#1425,.T.);
#1427=ORIENTED_EDGE('',*,*,#270,.T.);
#1428=CARTESIAN_POINT('',(10.2661948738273,46.75,3.21312326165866));
#1429=CARTESIAN_POINT('',(10.286122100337,46.7296681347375,3.20338125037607));
#1430=CARTESIAN_POINT('',(10.3054856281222,46.7091521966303,3.19288399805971));
#1431=CARTESIAN_POINT('',(10.342982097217,46.6679000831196,3.17051776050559));
#1432=CARTESIAN_POINT('',(10.3611191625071,46.647164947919,3.15865377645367));
#1433=CARTESIAN_POINT('',(10.3962005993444,46.6054780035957,3.13362287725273));
#1434=CARTESIAN_POINT('',(10.4131450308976,46.5845262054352,3.12045602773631));
#1435=CARTESIAN_POINT('',(10.4458660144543,46.5423972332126,3.09284888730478));
#1436=CARTESIAN_POINT('',(10.4616381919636,46.5212195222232,3.07840422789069));
#1437=CARTESIAN_POINT('',(10.4767756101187,46.5,3.06338297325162));
#1438=B_SPLINE_CURVE_WITH_KNOTS('',3,(#1428,#1429,#1430,#1431,#1432,#1433,#1434,#1435,#1436,
#1437),.UNSPECIFIED.,.F.,.F.,(4,2,2,2,4),(0.,0.0902471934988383,0.180174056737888,
0.270096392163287,0.360338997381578),.UNSPECIFIED.);
#1439=EDGE_CURVE('E289',#269,#864,#1438,.T.);
#1440=ORIENTED_EDGE('',*,*,#1439,.T.);
#1441=ORIENTED_EDGE('',*,*,#865,.F.);
#1442=CARTESIAN_POINT('',(9.91763458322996,40.25,2.5));
#1443=DIRECTION('',(0.,1.,0.));
#1444=DIRECTION('',(0.,0.,1.));
#1445=AXIS2_PLACEMENT_3D('',#1442,#1443,#1444);
#1446=CIRCLE('',#1445,0.793749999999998);
#1447=EDGE_CURVE('E530',#881,#862,#1446,.T.);
#1448=ORIENTED_EDGE('',*,*,#1447,.F.);
#1449=EDGE_LOOP('',(#1413,#1426,#1427,#1440,#1441,#1448));
#1450=FACE_BOUND('',#1449,.T.);
#1451=ADVANCED_FACE('F736',(#1450),#1412,.F.);
#1452=CARTESIAN_POINT('',(9.91763458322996,40.25,2.5));
#1453=DIRECTION('',(0.,1.,0.));
#1454=DIRECTION('',(0.,0.,1.));
#1455=AXIS2_PLACEMENT_3D('',#1452,#1453,#1454);
#1456=CONICAL_SURFACE('',#1455,0.793749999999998,1.02974425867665);
#1457=ORIENTED_EDGE('',*,*,#905,.F.);
#1458=ORIENTED_EDGE('',*,*,#1447,.T.);
#1459=ORIENTED_EDGE('',*,*,#926,.F.);
#1460=EDGE_LOOP('',(#1457,#1458,#1459));
#1461=FACE_BOUND('',#1460,.T.);
#1462=ADVANCED_FACE('F732',(#1461),#1456,.F.);
#1463=CARTESIAN_POINT('',(60.5,41.55,0.));
#1464=DIRECTION('',(0.,1.,0.));
#1465=DIRECTION('',(0.,0.,1.));
#1466=AXIS2_PLACEMENT_3D('',#1463,#1464,#1465);
#1467=CONICAL_SURFACE('',#1466,0.799999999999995,1.02974425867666);
#1468=CARTESIAN_POINT('',(60.5,41.069311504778,0.));
#1469=VERTEX_POINT('',#1468);
#1470=VERTEX_LOOP('',#1469);
#1471=FACE_BOUND('',#1470,.T.);
#1472=CARTESIAN_POINT('',(60.5,41.55,0.));
#1473=DIRECTION('',(0.,1.,0.));
#1474=DIRECTION('',(0.,0.,1.));
#1475=AXIS2_PLACEMENT_3D('',#1472,#1473,#1474);
#1476=CIRCLE('',#1475,0.799999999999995);
#1477=CARTESIAN_POINT('',(60.5,41.55,0.799999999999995));
#1478=VERTEX_POINT('',#1477);
#1479=EDGE_CURVE('E524',#1478,#1478,#1476,.T.);
#1480=ORIENTED_EDGE('',*,*,#1479,.T.);
#1481=EDGE_LOOP('',(#1480));
#1482=FACE_BOUND('',#1481,.T.);
#1483=ADVANCED_FACE('F735',(#1471,#1482),#1467,.F.);
#1484=CARTESIAN_POINT('',(60.5,46.75,0.));
#1485=DIRECTION('',(0.,1.,0.));
#1486=DIRECTION('',(0.,0.,1.));
#1487=AXIS2_PLACEMENT_3D('',#1484,#1485,#1486);
#1488=CYLINDRICAL_SURFACE('',#1487,0.799999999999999);
#1489=ORIENTED_EDGE('',*,*,#1479,.F.);
#1490=EDGE_LOOP('',(#1489));
#1491=FACE_BOUND('',#1490,.T.);
#1492=ORIENTED_EDGE('',*,*,#207,.T.);
#1493=EDGE_LOOP('',(#1492));
#1494=FACE_BOUND('',#1493,.T.);
#1495=ADVANCED_FACE('F859',(#1491,#1494),#1488,.F.);
#1496=CARTESIAN_POINT('',(42.1,41.55,0.));
#1497=DIRECTION('',(0.,1.,0.));
#1498=DIRECTION('',(0.,0.,1.));
#1499=AXIS2_PLACEMENT_3D('',#1496,#1497,#1498);
#1500=CONICAL_SURFACE('',#1499,0.799999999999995,1.02974425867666);
#1501=CARTESIAN_POINT('',(42.1,41.069311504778,0.));
#1502=VERTEX_POINT('',#1501);
#1503=VERTEX_LOOP('',#1502);
#1504=FACE_BOUND('',#1503,.T.);
#1505=CARTESIAN_POINT('',(42.1,41.55,0.));
#1506=DIRECTION('',(0.,1.,0.));
#1507=DIRECTION('',(0.,0.,1.));
#1508=AXIS2_PLACEMENT_3D('',#1505,#1506,#1507);
#1509=CIRCLE('',#1508,0.799999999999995);
#1510=CARTESIAN_POINT('',(42.1,41.55,0.799999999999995));
#1511=VERTEX_POINT('',#1510);
#1512=EDGE_CURVE('E518',#1511,#1511,#1509,.T.);
#1513=ORIENTED_EDGE('',*,*,#1512,.T.);
#1514=EDGE_LOOP('',(#1513));
#1515=FACE_BOUND('',#1514,.T.);
#1516=ADVANCED_FACE('F855',(#1504,#1515),#1500,.F.);
#1517=CARTESIAN_POINT('',(42.1,46.75,0.));
#1518=DIRECTION('',(0.,1.,0.));
#1519=DIRECTION('',(0.,0.,1.));
#1520=AXIS2_PLACEMENT_3D('',#1517,#1518,#1519);
#1521=CYLINDRICAL_SURFACE('',#1520,0.799999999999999);
#1522=ORIENTED_EDGE('',*,*,#1512,.F.);
#1523=EDGE_LOOP('',(#1522));
#1524=FACE_BOUND('',#1523,.T.);
#1525=ORIENTED_EDGE('',*,*,#196,.T.);
#1526=EDGE_LOOP('',(#1525));
#1527=FACE_BOUND('',#1526,.T.);
#1528=ADVANCED_FACE('F851',(#1524,#1527),#1521,.F.);
#1529=CARTESIAN_POINT('',(30.7,41.55,0.));
#1530=DIRECTION('',(0.,1.,0.));
#1531=DIRECTION('',(0.,0.,1.));
#1532=AXIS2_PLACEMENT_3D('',#1529,#1530,#1531);
#1533=CONICAL_SURFACE('',#1532,0.800000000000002,1.02974425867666);
#1534=CARTESIAN_POINT('',(30.7,41.069311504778,0.));
#1535=VERTEX_POINT('',#1534);
#1536=VERTEX_LOOP('',#1535);
#1537=FACE_BOUND('',#1536,.T.);
#1538=CARTESIAN_POINT('',(30.7,41.55,0.));
#1539=DIRECTION('',(0.,1.,0.));
#1540=DIRECTION('',(0.,0.,1.));
#1541=AXIS2_PLACEMENT_3D('',#1538,#1539,#1540);
#1542=CIRCLE('',#1541,0.800000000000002);
#1543=CARTESIAN_POINT('',(30.7,41.55,0.800000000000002));
#1544=VERTEX_POINT('',#1543);
#1545=EDGE_CURVE('E512',#1544,#1544,#1542,.T.);
#1546=ORIENTED_EDGE('',*,*,#1545,.T.);
#1547=EDGE_LOOP('',(#1546));
#1548=FACE_BOUND('',#1547,.T.);
#1549=ADVANCED_FACE('F847',(#1537,#1548),#1533,.F.);
#1550=CARTESIAN_POINT('',(30.7,46.75,0.));
#1551=DIRECTION('',(0.,1.,0.));
#1552=DIRECTION('',(0.,0.,1.));
#1553=AXIS2_PLACEMENT_3D('',#1550,#1551,#1552);
#1554=CYLINDRICAL_SURFACE('',#1553,0.800000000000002);
#1555=ORIENTED_EDGE('',*,*,#1545,.F.);
#1556=EDGE_LOOP('',(#1555));
#1557=FACE_BOUND('',#1556,.T.);
#1558=ORIENTED_EDGE('',*,*,#185,.T.);
#1559=EDGE_LOOP('',(#1558));
#1560=FACE_BOUND('',#1559,.T.);
#1561=ADVANCED_FACE('F843',(#1557,#1560),#1554,.F.);
#1562=CARTESIAN_POINT('',(19.,41.55,0.));
#1563=DIRECTION('',(0.,1.,0.));
#1564=DIRECTION('',(0.,0.,1.));
#1565=AXIS2_PLACEMENT_3D('',#1562,#1563,#1564);
#1566=CONICAL_SURFACE('',#1565,0.799999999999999,1.02974425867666);
#1567=CARTESIAN_POINT('',(19.,41.069311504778,0.));
#1568=VERTEX_POINT('',#1567);
#1569=VERTEX_LOOP('',#1568);
#1570=FACE_BOUND('',#1569,.T.);
#1571=CARTESIAN_POINT('',(19.,41.55,0.));
#1572=DIRECTION('',(0.,1.,0.));
#1573=DIRECTION('',(0.,0.,1.));
#1574=AXIS2_PLACEMENT_3D('',#1571,#1572,#1573);
#1575=CIRCLE('',#1574,0.799999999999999);
#1576=CARTESIAN_POINT('',(19.,41.55,0.799999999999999));
#1577=VERTEX_POINT('',#1576);
#1578=EDGE_CURVE('E506',#1577,#1577,#1575,.T.);
#1579=ORIENTED_EDGE('',*,*,#1578,.T.);
#1580=EDGE_LOOP('',(#1579));
#1581=FACE_BOUND('',#1580,.T.);
#1582=ADVANCED_FACE('F839',(#1570,#1581),#1566,.F.);
#1583=CARTESIAN_POINT('',(19.,46.75,0.));
#1584=DIRECTION('',(0.,1.,0.));
#1585=DIRECTION('',(0.,0.,1.));
#1586=AXIS2_PLACEMENT_3D('',#1583,#1584,#1585);
#1587=CYLINDRICAL_SURFACE('',#1586,0.799999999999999);
#1588=ORIENTED_EDGE('',*,*,#1578,.F.);
#1589=EDGE_LOOP('',(#1588));
#1590=FACE_BOUND('',#1589,.T.);
#1591=ORIENTED_EDGE('',*,*,#174,.T.);
#1592=EDGE_LOOP('',(#1591));
#1593=FACE_BOUND('',#1592,.T.);
#1594=ADVANCED_FACE('F834',(#1590,#1593),#1587,.F.);
#1595=CARTESIAN_POINT('',(11.1,8.2,0.));
#1596=DIRECTION('',(0.,1.,0.));
#1597=DIRECTION('',(-1.,0.,0.));
#1598=AXIS2_PLACEMENT_3D('',#1595,#1596,#1597);
#1599=SPHERICAL_SURFACE('',#1598,2.38125);
#1600=ORIENTED_EDGE('',*,*,#850,.F.);
#1601=EDGE_LOOP('',(#1600));
#1602=FACE_BOUND('',#1601,.T.);
#1603=ADVANCED_FACE('F828',(#1602),#1599,.F.);
#1604=CARTESIAN_POINT('',(13.,4.,0.));
#1605=DIRECTION('',(0.,-1.,0.));
#1606=DIRECTION('',(0.,0.,-1.));
#1607=AXIS2_PLACEMENT_3D('',#1604,#1605,#1606);
#1608=CONICAL_SURFACE('',#1607,1.3208,1.0471975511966);
#1609=CARTESIAN_POINT('',(13.,4.30429245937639,0.));
#1610=DIRECTION('',(0.,-1.,0.));
#1611=DIRECTION('',(0.,0.,-1.));
#1612=AXIS2_PLACEMENT_3D('',#1609,#1610,#1611);
#1613=CIRCLE('',#1612,0.793749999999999);
#1614=CARTESIAN_POINT('',(13.,4.30429245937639,-0.793749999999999));
#1615=VERTEX_POINT('',#1614);
#1616=EDGE_CURVE('E469',#1615,#1615,#1613,.F.);
#1617=ORIENTED_EDGE('',*,*,#1616,.T.);
#1618=EDGE_LOOP('',(#1617));
#1619=FACE_BOUND('',#1618,.T.);
#1620=CARTESIAN_POINT('',(13.,4.,0.));
#1621=DIRECTION('',(0.,-1.,0.));
#1622=DIRECTION('',(0.,0.,-1.));
#1623=AXIS2_PLACEMENT_3D('',#1620,#1621,#1622);
#1624=CIRCLE('',#1623,1.3208);
#1625=CARTESIAN_POINT('',(13.,4.,-1.3208));
#1626=VERTEX_POINT('',#1625);
#1627=EDGE_CURVE('E499',#1626,#1626,#1624,.T.);
#1628=ORIENTED_EDGE('',*,*,#1627,.T.);
#1629=EDGE_LOOP('',(#1628));
#1630=FACE_BOUND('',#1629,.T.);
#1631=ADVANCED_FACE('F833',(#1619,#1630),#1608,.F.);
#1632=CARTESIAN_POINT('',(13.,0.,0.));
#1633=DIRECTION('',(0.,-1.,0.));
#1634=DIRECTION('',(0.,0.,-1.));
#1635=AXIS2_PLACEMENT_3D('',#1632,#1633,#1634);
#1636=CYLINDRICAL_SURFACE('',#1635,1.3208);
#1637=ORIENTED_EDGE('',*,*,#1627,.F.);
#1638=EDGE_LOOP('',(#1637));
#1639=FACE_BOUND('',#1638,.T.);
#1640=ORIENTED_EDGE('',*,*,#113,.T.);
#1641=EDGE_LOOP('',(#1640));
#1642=FACE_BOUND('',#1641,.T.);
#1643=ADVANCED_FACE('F979',(#1639,#1642),#1636,.F.);
#1644=CARTESIAN_POINT('',(38.33,4.,-1.5));
#1645=DIRECTION('',(0.,-1.,0.));
#1646=DIRECTION('',(0.,0.,-1.));
#1647=AXIS2_PLACEMENT_3D('',#1644,#1645,#1646);
#1648=CONICAL_SURFACE('',#1647,1.3208,1.0471975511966);
#1649=CARTESIAN_POINT('',(38.33,4.53342834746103,-1.5));
#1650=DIRECTION('',(0.,-1.,0.));
#1651=DIRECTION('',(0.,0.,-1.));
#1652=AXIS2_PLACEMENT_3D('',#1649,#1650,#1651);
#1653=CIRCLE('',#1652,0.396874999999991);
#1654=CARTESIAN_POINT('',(38.33,4.53342834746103,-1.89687499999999));
#1655=VERTEX_POINT('',#1654);
#1656=EDGE_CURVE('E421',#1655,#1655,#1653,.F.);
#1657=CARTESIAN_POINT('',(38.33,4.,-1.5));
#1658=DIRECTION('',(0.,-1.,0.));
#1659=DIRECTION('',(0.,0.,-1.));
#1660=AXIS2_PLACEMENT_3D('',#1657,#1658,#1659);
#1661=CIRCLE('',#1660,1.3208);
#1662=CARTESIAN_POINT('',(38.33,4.,-2.8208));
#1663=VERTEX_POINT('',#1662);
#1664=EDGE_CURVE('E487',#1663,#1663,#1661,.T.);
#1665=CARTESIAN_POINT('',(38.33,4.53342834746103,-1.89687499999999));
#1666=CARTESIAN_POINT('',(38.33,4.52787180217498,-1.90649921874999));
#1667=CARTESIAN_POINT('',(38.33,4.52231525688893,-1.91612343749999));
#1668=CARTESIAN_POINT('',(38.33,4.51120216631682,-1.93537187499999));
#1669=CARTESIAN_POINT('',(38.33,4.50564562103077,-1.94499609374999));
#1670=CARTESIAN_POINT('',(38.33,4.49453253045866,-1.96424453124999));
#1671=CARTESIAN_POINT('',(38.33,4.48897598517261,-1.97386874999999));
#1672=CARTESIAN_POINT('',(38.33,4.47786289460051,-1.99311718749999));
#1673=CARTESIAN_POINT('',(38.33,4.47230634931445,-2.00274140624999));
#1674=CARTESIAN_POINT('',(38.33,4.46119325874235,-2.02198984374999));
#1675=CARTESIAN_POINT('',(38.33,4.4556367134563,-2.03161406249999));
#1676=CARTESIAN_POINT('',(38.33,4.44452362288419,-2.05086249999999));
#1677=CARTESIAN_POINT('',(38.33,4.43896707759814,-2.06048671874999));
#1678=CARTESIAN_POINT('',(38.33,4.42785398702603,-2.07973515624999));
#1679=CARTESIAN_POINT('',(38.33,4.42229744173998,-2.08935937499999));
#1680=CARTESIAN_POINT('',(38.33,4.41118435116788,-2.10860781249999));
#1681=CARTESIAN_POINT('',(38.33,4.40562780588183,-2.11823203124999));
#1682=CARTESIAN_POINT('',(38.33,4.39451471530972,-2.13748046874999));
#1683=CARTESIAN_POINT('',(38.33,4.38895817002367,-2.14710468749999));
#1684=CARTESIAN_POINT('',(38.33,4.37784507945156,-2.16635312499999));
#1685=CARTESIAN_POINT('',(38.33,4.37228853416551,-2.17597734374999));
#1686=CARTESIAN_POINT('',(38.33,4.36117544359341,-2.19522578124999));
#1687=CARTESIAN_POINT('',(38.33,4.35561889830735,-2.20484999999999));
#1688=CARTESIAN_POINT('',(38.33,4.34450580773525,-2.22409843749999));
#1689=CARTESIAN_POINT('',(38.33,4.3389492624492,-2.23372265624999));
#1690=CARTESIAN_POINT('',(38.33,4.32783617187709,-2.25297109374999));
#1691=CARTESIAN_POINT('',(38.33,4.32227962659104,-2.26259531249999));
#1692=CARTESIAN_POINT('',(38.33,4.31116653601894,-2.28184374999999));
#1693=CARTESIAN_POINT('',(38.33,4.30560999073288,-2.29146796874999));
#1694=CARTESIAN_POINT('',(38.33,4.29449690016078,-2.31071640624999));
#1695=CARTESIAN_POINT('',(38.33,4.28894035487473,-2.32034062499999));
#1696=CARTESIAN_POINT('',(38.33,4.27782726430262,-2.33958906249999));
#1697=CARTESIAN_POINT('',(38.33,4.27227071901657,-2.34921328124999));
#1698=CARTESIAN_POINT('',(38.33,4.26115762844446,-2.36846171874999));
#1699=CARTESIAN_POINT('',(38.33,4.25560108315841,-2.37808593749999));
#1700=CARTESIAN_POINT('',(38.33,4.24448799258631,-2.39733437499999));
#1701=CARTESIAN_POINT('',(38.33,4.23893144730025,-2.40695859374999));
#1702=CARTESIAN_POINT('',(38.33,4.22781835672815,-2.42620703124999));
#1703=CARTESIAN_POINT('',(38.33,4.2222618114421,-2.43583124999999));
#1704=CARTESIAN_POINT('',(38.33,4.21114872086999,-2.45507968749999));
#1705=CARTESIAN_POINT('',(38.33,4.20559217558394,-2.46470390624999));
#1706=CARTESIAN_POINT('',(38.33,4.19447908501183,-2.48395234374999));
#1707=CARTESIAN_POINT('',(38.33,4.18892253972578,-2.49357656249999));
#1708=CARTESIAN_POINT('',(38.33,4.17780944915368,-2.51282499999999));
#1709=CARTESIAN_POINT('',(38.33,4.17225290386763,-2.52244921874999));
#1710=CARTESIAN_POINT('',(38.33,4.16113981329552,-2.54169765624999));
#1711=CARTESIAN_POINT('',(38.33,4.15558326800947,-2.55132187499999));
#1712=CARTESIAN_POINT('',(38.33,4.14447017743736,-2.57057031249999));
#1713=CARTESIAN_POINT('',(38.33,4.13891363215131,-2.58019453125));
#1714=CARTESIAN_POINT('',(38.33,4.12780054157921,-2.59944296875));
#1715=CARTESIAN_POINT('',(38.33,4.12224399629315,-2.60906718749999));
#1716=CARTESIAN_POINT('',(38.33,4.11113090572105,-2.628315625));
#1717=CARTESIAN_POINT('',(38.33,4.105574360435,-2.63793984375));
#1718=CARTESIAN_POINT('',(38.33,4.09446126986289,-2.65718828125));
#1719=CARTESIAN_POINT('',(38.33,4.08890472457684,-2.66681249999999));
#1720=CARTESIAN_POINT('',(38.33,4.07779163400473,-2.6860609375));
#1721=CARTESIAN_POINT('',(38.33,4.07223508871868,-2.69568515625));
#1722=CARTESIAN_POINT('',(38.33,4.06112199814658,-2.71493359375));
#1723=CARTESIAN_POINT('',(38.33,4.05556545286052,-2.7245578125));
#1724=CARTESIAN_POINT('',(38.33,4.04445236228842,-2.74380625));
#1725=CARTESIAN_POINT('',(38.33,4.03889581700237,-2.75343046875));
#1726=CARTESIAN_POINT('',(38.33,4.02778272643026,-2.77267890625));
#1727=CARTESIAN_POINT('',(38.33,4.02222618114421,-2.782303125));
#1728=CARTESIAN_POINT('',(38.33,4.0111130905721,-2.8015515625));
#1729=CARTESIAN_POINT('',(38.33,4.00555654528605,-2.81117578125));
#1730=CARTESIAN_POINT('',(38.33,4.,-2.8208));
#1731=B_SPLINE_CURVE_WITH_KNOTS('',3,(#1665,#1666,#1667,#1668,#1669,#1670,#1671,#1672,#1673,
#1674,#1675,#1676,#1677,#1678,#1679,#1680,#1681,#1682,#1683,#1684,#1685,#1686,#1687,#1688,#1689,
#1690,#1691,#1692,#1693,#1694,#1695,#1696,#1697,#1698,#1699,#1700,#1701,#1702,#1703,#1704,#1705,
#1706,#1707,#1708,#1709,#1710,#1711,#1712,#1713,#1714,#1715,#1716,#1717,#1718,#1719,#1720,#1721,
#1722,#1723,#1724,#1725,#1726,#1727,#1728,#1729,#1730),.UNSPECIFIED.,.F.,.F.,(4,2,2,2,2,2,2,2,2,
2,2,2,2,2,2,2,2,2,2,2,2,2,2,2,2,2,2,2,2,2,2,2,4),(0.,0.0333392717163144,0.0666785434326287,
0.100017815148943,0.133357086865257,0.166696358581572,0.200035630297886,0.2333749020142,
0.266714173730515,0.300053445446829,0.333392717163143,0.366731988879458,0.400071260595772,
0.433410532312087,0.4667498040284,0.500089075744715,0.533428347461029,0.566767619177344,
0.600106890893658,0.633446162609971,0.666785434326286,0.700124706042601,0.733463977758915,
0.766803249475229,0.800142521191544,0.833481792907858,0.866821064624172,0.900160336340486,
0.933499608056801,0.966838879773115,1.00017815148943,1.03351742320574,1.06685669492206),.UNSPECIFIED.);
#1732=EDGE_CURVE('BSEAM976',#1655,#1663,#1731,.T.);
#1733=ORIENTED_EDGE('',*,*,#1656,.T.);
#1734=ORIENTED_EDGE('',*,*,#1664,.T.);
#1735=ORIENTED_EDGE('',*,*,#1732,.T.);
#1736=ORIENTED_EDGE('',*,*,#1732,.F.);
#1737=EDGE_LOOP('',(#1733,#1735,#1734,#1736));
#1738=FACE_BOUND('',#1737,.T.);
#1739=ADVANCED_FACE('F976',(#1738),#1648,.F.);
#1740=CARTESIAN_POINT('',(38.33,0.,-1.5));
#1741=DIRECTION('',(0.,-1.,0.));
#1742=DIRECTION('',(0.,0.,-1.));
#1743=AXIS2_PLACEMENT_3D('',#1740,#1741,#1742);
#1744=CYLINDRICAL_SURFACE('',#1743,1.3208);
#1745=ORIENTED_EDGE('',*,*,#1664,.F.);
#1746=EDGE_LOOP('',(#1745));
#1747=FACE_BOUND('',#1746,.T.);
#1748=ORIENTED_EDGE('',*,*,#54,.T.);
#1749=EDGE_LOOP('',(#1748));
#1750=FACE_BOUND('',#1749,.T.);
#1751=ADVANCED_FACE('F972',(#1747,#1750),#1744,.F.);
#1752=CARTESIAN_POINT('',(34.33,4.,-1.5));
#1753=DIRECTION('',(0.,-1.,0.));
#1754=DIRECTION('',(0.,0.,-1.));
#1755=AXIS2_PLACEMENT_3D('',#1752,#1753,#1754);
#1756=CONICAL_SURFACE('',#1755,1.3208,1.0471975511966);
#1757=CARTESIAN_POINT('',(34.33,4.53342834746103,-1.5));
#1758=DIRECTION('',(0.,-1.,0.));
#1759=DIRECTION('',(0.,0.,-1.));
#1760=AXIS2_PLACEMENT_3D('',#1757,#1758,#1759);
#1761=CIRCLE('',#1760,0.396874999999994);
#1762=CARTESIAN_POINT('',(34.33,4.53342834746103,-1.89687499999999));
#1763=VERTEX_POINT('',#1762);
#1764=EDGE_CURVE('E427',#1763,#1763,#1761,.F.);
#1765=CARTESIAN_POINT('',(34.33,4.,-1.5));
#1766=DIRECTION('',(0.,-1.,0.));
#1767=DIRECTION('',(0.,0.,-1.));
#1768=AXIS2_PLACEMENT_3D('',#1765,#1766,#1767);
#1769=CIRCLE('',#1768,1.3208);
#1770=CARTESIAN_POINT('',(34.33,4.,-2.8208));
#1771=VERTEX_POINT('',#1770);
#1772=EDGE_CURVE('E481',#1771,#1771,#1769,.T.);
#1773=CARTESIAN_POINT('',(34.33,4.53342834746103,-1.89687499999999));
#1774=CARTESIAN_POINT('',(34.33,4.52787180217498,-1.90649921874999));
#1775=CARTESIAN_POINT('',(34.33,4.52231525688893,-1.91612343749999));
#1776=CARTESIAN_POINT('',(34.33,4.51120216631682,-1.93537187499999));
#1777=CARTESIAN_POINT('',(34.33,4.50564562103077,-1.94499609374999));
#1778=CARTESIAN_POINT('',(34.33,4.49453253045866,-1.96424453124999));
#1779=CARTESIAN_POINT('',(34.33,4.48897598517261,-1.97386874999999));
#1780=CARTESIAN_POINT('',(34.33,4.4778628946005,-1.99311718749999));
#1781=CARTESIAN_POINT('',(34.33,4.47230634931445,-2.00274140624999));
#1782=CARTESIAN_POINT('',(34.33,4.46119325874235,-2.02198984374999));
#1783=CARTESIAN_POINT('',(34.33,4.4556367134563,-2.03161406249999));
#1784=CARTESIAN_POINT('',(34.33,4.44452362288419,-2.05086249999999));
#1785=CARTESIAN_POINT('',(34.33,4.43896707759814,-2.06048671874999));
#1786=CARTESIAN_POINT('',(34.33,4.42785398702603,-2.07973515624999));
#1787=CARTESIAN_POINT('',(34.33,4.42229744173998,-2.08935937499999));
#1788=CARTESIAN_POINT('',(34.33,4.41118435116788,-2.10860781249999));
#1789=CARTESIAN_POINT('',(34.33,4.40562780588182,-2.11823203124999));
#1790=CARTESIAN_POINT('',(34.33,4.39451471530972,-2.13748046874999));
#1791=CARTESIAN_POINT('',(34.33,4.38895817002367,-2.14710468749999));
#1792=CARTESIAN_POINT('',(34.33,4.37784507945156,-2.16635312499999));
#1793=CARTESIAN_POINT('',(34.33,4.37228853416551,-2.17597734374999));
#1794=CARTESIAN_POINT('',(34.33,4.3611754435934,-2.19522578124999));
#1795=CARTESIAN_POINT('',(34.33,4.35561889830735,-2.20484999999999));
#1796=CARTESIAN_POINT('',(34.33,4.34450580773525,-2.22409843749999));
#1797=CARTESIAN_POINT('',(34.33,4.3389492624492,-2.23372265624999));
#1798=CARTESIAN_POINT('',(34.33,4.32783617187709,-2.25297109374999));
#1799=CARTESIAN_POINT('',(34.33,4.32227962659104,-2.26259531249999));
#1800=CARTESIAN_POINT('',(34.33,4.31116653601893,-2.28184374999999));
#1801=CARTESIAN_POINT('',(34.33,4.30560999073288,-2.29146796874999));
#1802=CARTESIAN_POINT('',(34.33,4.29449690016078,-2.31071640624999));
#1803=CARTESIAN_POINT('',(34.33,4.28894035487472,-2.32034062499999));
#1804=CARTESIAN_POINT('',(34.33,4.27782726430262,-2.33958906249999));
#1805=CARTESIAN_POINT('',(34.33,4.27227071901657,-2.34921328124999));
#1806=CARTESIAN_POINT('',(34.33,4.26115762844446,-2.36846171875));
#1807=CARTESIAN_POINT('',(34.33,4.25560108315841,-2.37808593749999));
#1808=CARTESIAN_POINT('',(34.33,4.24448799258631,-2.39733437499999));
#1809=CARTESIAN_POINT('',(34.33,4.23893144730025,-2.40695859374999));
#1810=CARTESIAN_POINT('',(34.33,4.22781835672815,-2.42620703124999));
#1811=CARTESIAN_POINT('',(34.33,4.2222618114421,-2.43583124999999));
#1812=CARTESIAN_POINT('',(34.33,4.21114872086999,-2.4550796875));
#1813=CARTESIAN_POINT('',(34.33,4.20559217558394,-2.46470390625));
#1814=CARTESIAN_POINT('',(34.33,4.19447908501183,-2.48395234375));
#1815=CARTESIAN_POINT('',(34.33,4.18892253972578,-2.4935765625));
#1816=CARTESIAN_POINT('',(34.33,4.17780944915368,-2.51282499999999));
#1817=CARTESIAN_POINT('',(34.33,4.17225290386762,-2.52244921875));
#1818=CARTESIAN_POINT('',(34.33,4.16113981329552,-2.54169765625));
#1819=CARTESIAN_POINT('',(34.33,4.15558326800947,-2.551321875));
#1820=CARTESIAN_POINT('',(34.33,4.14447017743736,-2.5705703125));
#1821=CARTESIAN_POINT('',(34.33,4.13891363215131,-2.58019453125));
#1822=CARTESIAN_POINT('',(34.33,4.12780054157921,-2.59944296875));
#1823=CARTESIAN_POINT('',(34.33,4.12224399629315,-2.6090671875));
#1824=CARTESIAN_POINT('',(34.33,4.11113090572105,-2.628315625));
#1825=CARTESIAN_POINT('',(34.33,4.105574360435,-2.63793984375));
#1826=CARTESIAN_POINT('',(34.33,4.09446126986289,-2.65718828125));
#1827=CARTESIAN_POINT('',(34.33,4.08890472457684,-2.6668125));
#1828=CARTESIAN_POINT('',(34.33,4.07779163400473,-2.6860609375));
#1829=CARTESIAN_POINT('',(34.33,4.07223508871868,-2.69568515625));
#1830=CARTESIAN_POINT('',(34.33,4.06112199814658,-2.71493359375));
#1831=CARTESIAN_POINT('',(34.33,4.05556545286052,-2.7245578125));
#1832=CARTESIAN_POINT('',(34.33,4.04445236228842,-2.74380625));
#1833=CARTESIAN_POINT('',(34.33,4.03889581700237,-2.75343046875));
#1834=CARTESIAN_POINT('',(34.33,4.02778272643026,-2.77267890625));
#1835=CARTESIAN_POINT('',(34.33,4.02222618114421,-2.782303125));
#1836=CARTESIAN_POINT('',(34.33,4.0111130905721,-2.8015515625));
#1837=CARTESIAN_POINT('',(34.33,4.00555654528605,-2.81117578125));
#1838=CARTESIAN_POINT('',(34.33,4.,-2.8208));
#1839=B_SPLINE_CURVE_WITH_KNOTS('',3,(#1773,#1774,#1775,#1776,#1777,#1778,#1779,#1780,#1781,
#1782,#1783,#1784,#1785,#1786,#1787,#1788,#1789,#1790,#1791,#1792,#1793,#1794,#1795,#1796,#1797,
#1798,#1799,#1800,#1801,#1802,#1803,#1804,#1805,#1806,#1807,#1808,#1809,#1810,#1811,#1812,#1813,
#1814,#1815,#1816,#1817,#1818,#1819,#1820,#1821,#1822,#1823,#1824,#1825,#1826,#1827,#1828,#1829,
#1830,#1831,#1832,#1833,#1834,#1835,#1836,#1837,#1838),.UNSPECIFIED.,.F.,.F.,(4,2,2,2,2,2,2,2,2,
2,2,2,2,2,2,2,2,2,2,2,2,2,2,2,2,2,2,2,2,2,2,2,4),(0.,0.033339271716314,0.0666785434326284,
0.100017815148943,0.133357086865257,0.166696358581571,0.200035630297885,0.233374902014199,
0.266714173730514,0.300053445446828,0.333392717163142,0.366731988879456,0.400071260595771,
0.433410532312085,0.466749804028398,0.500089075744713,0.533428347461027,0.566767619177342,
0.600106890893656,0.63344616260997,0.666785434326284,0.700124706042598,0.733463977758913,
0.766803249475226,0.80014252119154,0.833481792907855,0.866821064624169,0.900160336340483,
0.933499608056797,0.966838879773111,1.00017815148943,1.03351742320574,1.06685669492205),.UNSPECIFIED.);
#1840=EDGE_CURVE('BSEAM968',#1763,#1771,#1839,.T.);
#1841=ORIENTED_EDGE('',*,*,#1764,.T.);
#1842=ORIENTED_EDGE('',*,*,#1772,.T.);
#1843=ORIENTED_EDGE('',*,*,#1840,.T.);
#1844=ORIENTED_EDGE('',*,*,#1840,.F.);
#1845=EDGE_LOOP('',(#1841,#1843,#1842,#1844));
#1846=FACE_BOUND('',#1845,.T.);
#1847=ADVANCED_FACE('F968',(#1846),#1756,.F.);
#1848=CARTESIAN_POINT('',(34.33,0.,-1.5));
#1849=DIRECTION('',(0.,-1.,0.));
#1850=DIRECTION('',(0.,0.,-1.));
#1851=AXIS2_PLACEMENT_3D('',#1848,#1849,#1850);
#1852=CYLINDRICAL_SURFACE('',#1851,1.3208);
#1853=ORIENTED_EDGE('',*,*,#1772,.F.);
#1854=EDGE_LOOP('',(#1853));
#1855=FACE_BOUND('',#1854,.T.);
#1856=ORIENTED_EDGE('',*,*,#65,.T.);
#1857=EDGE_LOOP('',(#1856));
#1858=FACE_BOUND('',#1857,.T.);
#1859=ADVANCED_FACE('F964',(#1855,#1858),#1852,.F.);
#1860=CARTESIAN_POINT('',(26.67,4.,-1.5));
#1861=DIRECTION('',(0.,-1.,0.));
#1862=DIRECTION('',(0.,0.,-1.));
#1863=AXIS2_PLACEMENT_3D('',#1860,#1861,#1862);
#1864=CONICAL_SURFACE('',#1863,1.3208,1.0471975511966);
#1865=CARTESIAN_POINT('',(26.67,4.53342834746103,-1.5));
#1866=DIRECTION('',(0.,-1.,0.));
#1867=DIRECTION('',(0.,0.,-1.));
#1868=AXIS2_PLACEMENT_3D('',#1865,#1866,#1867);
#1869=CIRCLE('',#1868,0.396874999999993);
#1870=CARTESIAN_POINT('',(26.67,4.53342834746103,-1.89687499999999));
#1871=VERTEX_POINT('',#1870);
#1872=EDGE_CURVE('E433',#1871,#1871,#1869,.F.);
#1873=CARTESIAN_POINT('',(26.67,4.,-1.5));
#1874=DIRECTION('',(0.,-1.,0.));
#1875=DIRECTION('',(0.,0.,-1.));
#1876=AXIS2_PLACEMENT_3D('',#1873,#1874,#1875);
#1877=CIRCLE('',#1876,1.3208);
#1878=CARTESIAN_POINT('',(26.67,4.,-2.8208));
#1879=VERTEX_POINT('',#1878);
#1880=EDGE_CURVE('E475',#1879,#1879,#1877,.T.);
#1881=CARTESIAN_POINT('',(26.67,4.53342834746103,-1.89687499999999));
#1882=CARTESIAN_POINT('',(26.67,4.52787180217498,-1.90649921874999));
#1883=CARTESIAN_POINT('',(26.67,4.52231525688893,-1.91612343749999));
#1884=CARTESIAN_POINT('',(26.67,4.51120216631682,-1.93537187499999));
#1885=CARTESIAN_POINT('',(26.67,4.50564562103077,-1.94499609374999));
#1886=CARTESIAN_POINT('',(26.67,4.49453253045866,-1.96424453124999));
#1887=CARTESIAN_POINT('',(26.67,4.48897598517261,-1.97386874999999));
#1888=CARTESIAN_POINT('',(26.67,4.47786289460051,-1.99311718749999));
#1889=CARTESIAN_POINT('',(26.67,4.47230634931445,-2.00274140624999));
#1890=CARTESIAN_POINT('',(26.67,4.46119325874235,-2.02198984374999));
#1891=CARTESIAN_POINT('',(26.67,4.4556367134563,-2.03161406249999));
#1892=CARTESIAN_POINT('',(26.67,4.44452362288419,-2.05086249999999));
#1893=CARTESIAN_POINT('',(26.67,4.43896707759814,-2.06048671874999));
#1894=CARTESIAN_POINT('',(26.67,4.42785398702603,-2.07973515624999));
#1895=CARTESIAN_POINT('',(26.67,4.42229744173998,-2.08935937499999));
#1896=CARTESIAN_POINT('',(26.67,4.41118435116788,-2.10860781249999));
#1897=CARTESIAN_POINT('',(26.67,4.40562780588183,-2.11823203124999));
#1898=CARTESIAN_POINT('',(26.67,4.39451471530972,-2.13748046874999));
#1899=CARTESIAN_POINT('',(26.67,4.38895817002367,-2.14710468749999));
#1900=CARTESIAN_POINT('',(26.67,4.37784507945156,-2.16635312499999));
#1901=CARTESIAN_POINT('',(26.67,4.37228853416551,-2.17597734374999));
#1902=CARTESIAN_POINT('',(26.67,4.36117544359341,-2.19522578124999));
#1903=CARTESIAN_POINT('',(26.67,4.35561889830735,-2.20484999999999));
#1904=CARTESIAN_POINT('',(26.67,4.34450580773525,-2.22409843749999));
#1905=CARTESIAN_POINT('',(26.67,4.3389492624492,-2.23372265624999));
#1906=CARTESIAN_POINT('',(26.67,4.32783617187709,-2.25297109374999));
#1907=CARTESIAN_POINT('',(26.67,4.32227962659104,-2.26259531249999));
#1908=CARTESIAN_POINT('',(26.67,4.31116653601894,-2.28184374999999));
#1909=CARTESIAN_POINT('',(26.67,4.30560999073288,-2.29146796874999));
#1910=CARTESIAN_POINT('',(26.67,4.29449690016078,-2.31071640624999));
#1911=CARTESIAN_POINT('',(26.67,4.28894035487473,-2.32034062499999));
#1912=CARTESIAN_POINT('',(26.67,4.27782726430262,-2.33958906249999));
#1913=CARTESIAN_POINT('',(26.67,4.27227071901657,-2.34921328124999));
#1914=CARTESIAN_POINT('',(26.67,4.26115762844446,-2.36846171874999));
#1915=CARTESIAN_POINT('',(26.67,4.25560108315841,-2.37808593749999));
#1916=CARTESIAN_POINT('',(26.67,4.24448799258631,-2.39733437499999));
#1917=CARTESIAN_POINT('',(26.67,4.23893144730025,-2.40695859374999));
#1918=CARTESIAN_POINT('',(26.67,4.22781835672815,-2.42620703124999));
#1919=CARTESIAN_POINT('',(26.67,4.2222618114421,-2.43583124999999));
#1920=CARTESIAN_POINT('',(26.67,4.21114872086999,-2.45507968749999));
#1921=CARTESIAN_POINT('',(26.67,4.20559217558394,-2.46470390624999));
#1922=CARTESIAN_POINT('',(26.67,4.19447908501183,-2.48395234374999));
#1923=CARTESIAN_POINT('',(26.67,4.18892253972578,-2.49357656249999));
#1924=CARTESIAN_POINT('',(26.67,4.17780944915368,-2.51282499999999));
#1925=CARTESIAN_POINT('',(26.67,4.17225290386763,-2.52244921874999));
#1926=CARTESIAN_POINT('',(26.67,4.16113981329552,-2.54169765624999));
#1927=CARTESIAN_POINT('',(26.67,4.15558326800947,-2.55132187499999));
#1928=CARTESIAN_POINT('',(26.67,4.14447017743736,-2.57057031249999));
#1929=CARTESIAN_POINT('',(26.67,4.13891363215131,-2.58019453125));
#1930=CARTESIAN_POINT('',(26.67,4.12780054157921,-2.59944296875));
#1931=CARTESIAN_POINT('',(26.67,4.12224399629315,-2.6090671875));
#1932=CARTESIAN_POINT('',(26.67,4.11113090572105,-2.628315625));
#1933=CARTESIAN_POINT('',(26.67,4.105574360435,-2.63793984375));
#1934=CARTESIAN_POINT('',(26.67,4.09446126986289,-2.65718828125));
#1935=CARTESIAN_POINT('',(26.67,4.08890472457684,-2.6668125));
#1936=CARTESIAN_POINT('',(26.67,4.07779163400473,-2.6860609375));
#1937=CARTESIAN_POINT('',(26.67,4.07223508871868,-2.69568515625));
#1938=CARTESIAN_POINT('',(26.67,4.06112199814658,-2.71493359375));
#1939=CARTESIAN_POINT('',(26.67,4.05556545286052,-2.7245578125));
#1940=CARTESIAN_POINT('',(26.67,4.04445236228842,-2.74380625));
#1941=CARTESIAN_POINT('',(26.67,4.03889581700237,-2.75343046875));
#1942=CARTESIAN_POINT('',(26.67,4.02778272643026,-2.77267890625));
#1943=CARTESIAN_POINT('',(26.67,4.02222618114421,-2.782303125));
#1944=CARTESIAN_POINT('',(26.67,4.0111130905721,-2.8015515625));
#1945=CARTESIAN_POINT('',(26.67,4.00555654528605,-2.81117578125));
#1946=CARTESIAN_POINT('',(26.67,4.,-2.8208));
#1947=B_SPLINE_CURVE_WITH_KNOTS('',3,(#1881,#1882,#1883,#1884,#1885,#1886,#1887,#1888,#1889,
#1890,#1891,#1892,#1893,#1894,#1895,#1896,#1897,#1898,#1899,#1900,#1901,#1902,#1903,#1904,#1905,
#1906,#1907,#1908,#1909,#1910,#1911,#1912,#1913,#1914,#1915,#1916,#1917,#1918,#1919,#1920,#1921,
#1922,#1923,#1924,#1925,#1926,#1927,#1928,#1929,#1930,#1931,#1932,#1933,#1934,#1935,#1936,#1937,
#1938,#1939,#1940,#1941,#1942,#1943,#1944,#1945,#1946),.UNSPECIFIED.,.F.,.F.,(4,2,2,2,2,2,2,2,2,
2,2,2,2,2,2,2,2,2,2,2,2,2,2,2,2,2,2,2,2,2,2,2,4),(0.,0.0333392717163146,0.0666785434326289,
0.100017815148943,0.133357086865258,0.166696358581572,0.200035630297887,0.2333749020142,
0.266714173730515,0.30005344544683,0.333392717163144,0.366731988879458,0.400071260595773,
0.433410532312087,0.466749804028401,0.500089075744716,0.53342834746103,0.566767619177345,
0.600106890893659,0.633446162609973,0.666785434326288,0.700124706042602,0.733463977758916,
0.766803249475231,0.800142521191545,0.83348179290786,0.866821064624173,0.900160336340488,
0.933499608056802,0.966838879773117,1.00017815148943,1.03351742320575,1.06685669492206),.UNSPECIFIED.);
#1948=EDGE_CURVE('BSEAM960',#1871,#1879,#1947,.T.);
#1949=ORIENTED_EDGE('',*,*,#1872,.T.);
#1950=ORIENTED_EDGE('',*,*,#1880,.T.);
#1951=ORIENTED_EDGE('',*,*,#1948,.T.);
#1952=ORIENTED_EDGE('',*,*,#1948,.F.);
#1953=EDGE_LOOP('',(#1949,#1951,#1950,#1952));
#1954=FACE_BOUND('',#1953,.T.);
#1955=ADVANCED_FACE('F960',(#1954),#1864,.F.);
#1956=CARTESIAN_POINT('',(26.67,0.,-1.5));
#1957=DIRECTION('',(0.,-1.,0.));
#1958=DIRECTION('',(0.,0.,-1.));
#1959=AXIS2_PLACEMENT_3D('',#1956,#1957,#1958);
#1960=CYLINDRICAL_SURFACE('',#1959,1.3208);
#1961=ORIENTED_EDGE('',*,*,#1880,.F.);
#1962=EDGE_LOOP('',(#1961));
#1963=FACE_BOUND('',#1962,.T.);
#1964=ORIENTED_EDGE('',*,*,#31,.T.);
#1965=EDGE_LOOP('',(#1964));
#1966=FACE_BOUND('',#1965,.T.);
#1967=ADVANCED_FACE('F956',(#1963,#1966),#1960,.F.);
#1968=CARTESIAN_POINT('',(13.,0.,0.));
#1969=DIRECTION('',(0.,-1.,0.));
#1970=DIRECTION('',(0.,0.,-1.));
#1971=AXIS2_PLACEMENT_3D('',#1968,#1969,#1970);
#1972=CYLINDRICAL_SURFACE('',#1971,0.793749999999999);
#1973=ORIENTED_EDGE('',*,*,#742,.F.);
#1974=EDGE_LOOP('',(#1973));
#1975=FACE_BOUND('',#1974,.T.);
#1976=ORIENTED_EDGE('',*,*,#1616,.F.);
#1977=EDGE_LOOP('',(#1976));
#1978=FACE_BOUND('',#1977,.T.);
#1979=ADVANCED_FACE('F952',(#1975,#1978),#1972,.F.);
#1980=CARTESIAN_POINT('',(13.,0.75,0.));
#1981=DIRECTION('',(0.,-1.,0.));
#1982=DIRECTION('',(0.,0.,-1.));
#1983=AXIS2_PLACEMENT_3D('',#1980,#1981,#1982);
#1984=CYLINDRICAL_SURFACE('',#1983,2.95);
#1985=CARTESIAN_POINT('',(13.,0.75,0.));
#1986=DIRECTION('',(0.,-1.,0.));
#1987=DIRECTION('',(0.,0.,-1.));
#1988=AXIS2_PLACEMENT_3D('',#1985,#1986,#1987);
#1989=CIRCLE('',#1988,2.95);
#1990=CARTESIAN_POINT('',(13.,0.75,-2.95));
#1991=VERTEX_POINT('',#1990);
#1992=EDGE_CURVE('E461',#1991,#1991,#1989,.T.);
#1993=ORIENTED_EDGE('',*,*,#1992,.F.);
#1994=EDGE_LOOP('',(#1993));
#1995=FACE_BOUND('',#1994,.T.);
#1996=ORIENTED_EDGE('',*,*,#662,.T.);
#1997=EDGE_LOOP('',(#1996));
#1998=FACE_BOUND('',#1997,.T.);
#1999=ADVANCED_FACE('F948',(#1995,#1998),#1984,.F.);
#2000=CARTESIAN_POINT('',(13.,0.75,0.));
#2001=DIRECTION('',(0.,-1.,0.));
#2002=DIRECTION('',(0.,0.,-1.));
#2003=AXIS2_PLACEMENT_3D('',#2000,#2001,#2002);
#2004=PLANE('',#2003);
#2005=CARTESIAN_POINT('',(13.,0.75,0.));
#2006=DIRECTION('',(0.,-1.,0.));
#2007=DIRECTION('',(0.,0.,-1.));
#2008=AXIS2_PLACEMENT_3D('',#2005,#2006,#2007);
#2009=CIRCLE('',#2008,1.55);
#2010=CARTESIAN_POINT('',(13.,0.75,-1.55));
#2011=VERTEX_POINT('',#2010);
#2012=EDGE_CURVE('E455',#2011,#2011,#2009,.T.);
#2013=ORIENTED_EDGE('',*,*,#2012,.F.);
#2014=EDGE_LOOP('',(#2013));
#2015=FACE_BOUND('',#2014,.T.);
#2016=ORIENTED_EDGE('',*,*,#1992,.T.);
#2017=EDGE_LOOP('',(#2016));
#2018=FACE_BOUND('',#2017,.T.);
#2019=ADVANCED_FACE('F944',(#2015,#2018),#2004,.T.);
#2020=CARTESIAN_POINT('',(13.,0.75,0.));
#2021=DIRECTION('',(0.,-1.,0.));
#2022=DIRECTION('',(0.,0.,-1.));
#2023=AXIS2_PLACEMENT_3D('',#2020,#2021,#2022);
#2024=CYLINDRICAL_SURFACE('',#2023,1.55);
#2025=ORIENTED_EDGE('',*,*,#2012,.T.);
#2026=EDGE_LOOP('',(#2025));
#2027=FACE_BOUND('',#2026,.T.);
#2028=ORIENTED_EDGE('',*,*,#124,.F.);
#2029=EDGE_LOOP('',(#2028));
#2030=FACE_BOUND('',#2029,.T.);
#2031=ADVANCED_FACE('F940',(#2027,#2030),#2024,.T.);
#2032=CARTESIAN_POINT('',(48.7,0.75,-0.8));
#2033=DIRECTION('',(0.,-1.,0.));
#2034=DIRECTION('',(0.,0.,-1.));
#2035=AXIS2_PLACEMENT_3D('',#2032,#2033,#2034);
#2036=CYLINDRICAL_SURFACE('',#2035,2.95);
#2037=CARTESIAN_POINT('',(48.7,0.75,-0.8));
#2038=DIRECTION('',(0.,-1.,0.));
#2039=DIRECTION('',(0.,0.,-1.));
#2040=AXIS2_PLACEMENT_3D('',#2037,#2038,#2039);
#2041=CIRCLE('',#2040,2.95);
#2042=CARTESIAN_POINT('',(48.7,0.75,-3.75));
#2043=VERTEX_POINT('',#2042);
#2044=EDGE_CURVE('E449',#2043,#2043,#2041,.T.);
#2045=ORIENTED_EDGE('',*,*,#2044,.F.);
#2046=EDGE_LOOP('',(#2045));
#2047=FACE_BOUND('',#2046,.T.);
#2048=ORIENTED_EDGE('',*,*,#651,.T.);
#2049=EDGE_LOOP('',(#2048));
#2050=FACE_BOUND('',#2049,.T.);
#2051=ADVANCED_FACE('F933',(#2047,#2050),#2036,.F.);
#2052=CARTESIAN_POINT('',(48.7,0.75,-0.8));
#2053=DIRECTION('',(0.,-1.,0.));
#2054=DIRECTION('',(0.,0.,-1.));
#2055=AXIS2_PLACEMENT_3D('',#2052,#2053,#2054);
#2056=PLANE('',#2055);
#2057=CARTESIAN_POINT('',(48.7,0.75,-0.8));
#2058=DIRECTION('',(0.,-1.,0.));
#2059=DIRECTION('',(0.,0.,-1.));
#2060=AXIS2_PLACEMENT_3D('',#2057,#2058,#2059);
#2061=CIRCLE('',#2060,1.55);
#2062=CARTESIAN_POINT('',(48.7,0.75,-2.35));
#2063=VERTEX_POINT('',#2062);
#2064=EDGE_CURVE('E443',#2063,#2063,#2061,.T.);
#2065=ORIENTED_EDGE('',*,*,#2064,.F.);
#2066=EDGE_LOOP('',(#2065));
#2067=FACE_BOUND('',#2066,.T.);
#2068=ORIENTED_EDGE('',*,*,#2044,.T.);
#2069=EDGE_LOOP('',(#2068));
#2070=FACE_BOUND('',#2069,.T.);
#2071=ADVANCED_FACE('F924',(#2067,#2070),#2056,.T.);
#2072=CARTESIAN_POINT('',(48.7,0.75,-0.8));
#2073=DIRECTION('',(0.,-1.,0.));
#2074=DIRECTION('',(0.,0.,-1.));
#2075=AXIS2_PLACEMENT_3D('',#2072,#2073,#2074);
#2076=CYLINDRICAL_SURFACE('',#2075,1.55);
#2077=ORIENTED_EDGE('',*,*,#2064,.T.);
#2078=EDGE_LOOP('',(#2077));
#2079=FACE_BOUND('',#2078,.T.);
#2080=CARTESIAN_POINT('',(48.7,0.,-0.8));
#2081=DIRECTION('',(0.,-1.,0.));
#2082=DIRECTION('',(0.,0.,-1.));
#2083=AXIS2_PLACEMENT_3D('',#2080,#2081,#2082);
#2084=CIRCLE('',#2083,1.55);
#2085=CARTESIAN_POINT('',(48.7,0.,-2.35));
#2086=VERTEX_POINT('',#2085);
#2087=EDGE_CURVE('E442',#2086,#2086,#2084,.T.);
#2088=ORIENTED_EDGE('',*,*,#2087,.F.);
#2089=EDGE_LOOP('',(#2088));
#2090=FACE_BOUND('',#2089,.T.);
#2091=ADVANCED_FACE('F922',(#2079,#2090),#2076,.T.);
#2092=CARTESIAN_POINT('',(48.7,4.,-0.8));
#2093=DIRECTION('',(0.,-1.,0.));
#2094=DIRECTION('',(0.,0.,-1.));
#2095=AXIS2_PLACEMENT_3D('',#2092,#2093,#2094);
#2096=CONICAL_SURFACE('',#2095,1.3208,1.0471975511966);
#2097=CARTESIAN_POINT('',(48.7,4.53342834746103,-0.8));
#2098=DIRECTION('',(0.,-1.,0.));
#2099=DIRECTION('',(0.,0.,-1.));
#2100=AXIS2_PLACEMENT_3D('',#2097,#2098,#2099);
#2101=CIRCLE('',#2100,0.396874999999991);
#2102=CARTESIAN_POINT('',(48.7,4.53342834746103,-1.19687499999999));
#2103=VERTEX_POINT('',#2102);
#2104=EDGE_CURVE('E439',#2103,#2103,#2101,.F.);
#2105=CARTESIAN_POINT('',(48.7,4.,-0.8));
#2106=DIRECTION('',(0.,-1.,0.));
#2107=DIRECTION('',(0.,0.,-1.));
#2108=AXIS2_PLACEMENT_3D('',#2105,#2106,#2107);
#2109=CIRCLE('',#2108,1.3208);
#2110=CARTESIAN_POINT('',(48.7,4.,-2.1208));
#2111=VERTEX_POINT('',#2110);
#2112=EDGE_CURVE('E493',#2111,#2111,#2109,.T.);
#2113=CARTESIAN_POINT('',(48.7,4.53342834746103,-1.19687499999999));
#2114=CARTESIAN_POINT('',(48.7,4.52787180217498,-1.20649921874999));
#2115=CARTESIAN_POINT('',(48.7,4.52231525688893,-1.21612343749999));
#2116=CARTESIAN_POINT('',(48.7,4.51120216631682,-1.23537187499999));
#2117=CARTESIAN_POINT('',(48.7,4.50564562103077,-1.24499609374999));
#2118=CARTESIAN_POINT('',(48.7,4.49453253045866,-1.26424453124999));
#2119=CARTESIAN_POINT('',(48.7,4.48897598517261,-1.27386874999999));
#2120=CARTESIAN_POINT('',(48.7,4.47786289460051,-1.29311718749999));
#2121=CARTESIAN_POINT('',(48.7,4.47230634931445,-1.30274140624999));
#2122=CARTESIAN_POINT('',(48.7,4.46119325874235,-1.32198984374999));
#2123=CARTESIAN_POINT('',(48.7,4.4556367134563,-1.33161406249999));
#2124=CARTESIAN_POINT('',(48.7,4.44452362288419,-1.35086249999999));
#2125=CARTESIAN_POINT('',(48.7,4.43896707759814,-1.36048671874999));
#2126=CARTESIAN_POINT('',(48.7,4.42785398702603,-1.37973515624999));
#2127=CARTESIAN_POINT('',(48.7,4.42229744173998,-1.38935937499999));
#2128=CARTESIAN_POINT('',(48.7,4.41118435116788,-1.40860781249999));
#2129=CARTESIAN_POINT('',(48.7,4.40562780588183,-1.41823203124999));
#2130=CARTESIAN_POINT('',(48.7,4.39451471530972,-1.43748046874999));
#2131=CARTESIAN_POINT('',(48.7,4.38895817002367,-1.44710468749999));
#2132=CARTESIAN_POINT('',(48.7,4.37784507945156,-1.46635312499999));
#2133=CARTESIAN_POINT('',(48.7,4.37228853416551,-1.47597734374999));
#2134=CARTESIAN_POINT('',(48.7,4.36117544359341,-1.49522578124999));
#2135=CARTESIAN_POINT('',(48.7,4.35561889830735,-1.50484999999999));
#2136=CARTESIAN_POINT('',(48.7,4.34450580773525,-1.52409843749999));
#2137=CARTESIAN_POINT('',(48.7,4.3389492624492,-1.53372265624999));
#2138=CARTESIAN_POINT('',(48.7,4.32783617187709,-1.55297109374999));
#2139=CARTESIAN_POINT('',(48.7,4.32227962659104,-1.56259531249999));
#2140=CARTESIAN_POINT('',(48.7,4.31116653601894,-1.58184374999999));
#2141=CARTESIAN_POINT('',(48.7,4.30560999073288,-1.59146796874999));
#2142=CARTESIAN_POINT('',(48.7,4.29449690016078,-1.61071640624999));
#2143=CARTESIAN_POINT('',(48.7,4.28894035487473,-1.62034062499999));
#2144=CARTESIAN_POINT('',(48.7,4.27782726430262,-1.63958906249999));
#2145=CARTESIAN_POINT('',(48.7,4.27227071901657,-1.64921328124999));
#2146=CARTESIAN_POINT('',(48.7,4.26115762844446,-1.66846171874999));
#2147=CARTESIAN_POINT('',(48.7,4.25560108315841,-1.67808593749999));
#2148=CARTESIAN_POINT('',(48.7,4.24448799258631,-1.69733437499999));
#2149=CARTESIAN_POINT('',(48.7,4.23893144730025,-1.70695859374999));
#2150=CARTESIAN_POINT('',(48.7,4.22781835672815,-1.72620703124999));
#2151=CARTESIAN_POINT('',(48.7,4.2222618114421,-1.73583124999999));
#2152=CARTESIAN_POINT('',(48.7,4.21114872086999,-1.75507968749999));
#2153=CARTESIAN_POINT('',(48.7,4.20559217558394,-1.76470390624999));
#2154=CARTESIAN_POINT('',(48.7,4.19447908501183,-1.78395234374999));
#2155=CARTESIAN_POINT('',(48.7,4.18892253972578,-1.79357656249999));
#2156=CARTESIAN_POINT('',(48.7,4.17780944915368,-1.81282499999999));
#2157=CARTESIAN_POINT('',(48.7,4.17225290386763,-1.82244921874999));
#2158=CARTESIAN_POINT('',(48.7,4.16113981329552,-1.84169765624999));
#2159=CARTESIAN_POINT('',(48.7,4.15558326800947,-1.85132187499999));
#2160=CARTESIAN_POINT('',(48.7,4.14447017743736,-1.87057031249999));
#2161=CARTESIAN_POINT('',(48.7,4.13891363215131,-1.88019453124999));
#2162=CARTESIAN_POINT('',(48.7,4.12780054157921,-1.89944296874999));
#2163=CARTESIAN_POINT('',(48.7,4.12224399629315,-1.9090671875));
#2164=CARTESIAN_POINT('',(48.7,4.11113090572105,-1.928315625));
#2165=CARTESIAN_POINT('',(48.7,4.105574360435,-1.93793984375));
#2166=CARTESIAN_POINT('',(48.7,4.09446126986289,-1.95718828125));
#2167=CARTESIAN_POINT('',(48.7,4.08890472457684,-1.9668125));
#2168=CARTESIAN_POINT('',(48.7,4.07779163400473,-1.9860609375));
#2169=CARTESIAN_POINT('',(48.7,4.07223508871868,-1.99568515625));
#2170=CARTESIAN_POINT('',(48.7,4.06112199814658,-2.01493359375));
#2171=CARTESIAN_POINT('',(48.7,4.05556545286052,-2.0245578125));
#2172=CARTESIAN_POINT('',(48.7,4.04445236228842,-2.04380625));
#2173=CARTESIAN_POINT('',(48.7,4.03889581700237,-2.05343046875));
#2174=CARTESIAN_POINT('',(48.7,4.02778272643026,-2.07267890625));
#2175=CARTESIAN_POINT('',(48.7,4.02222618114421,-2.082303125));
#2176=CARTESIAN_POINT('',(48.7,4.0111130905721,-2.1015515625));
#2177=CARTESIAN_POINT('',(48.7,4.00555654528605,-2.11117578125));
#2178=CARTESIAN_POINT('',(48.7,4.,-2.1208));
#2179=B_SPLINE_CURVE_WITH_KNOTS('',3,(#2113,#2114,#2115,#2116,#2117,#2118,#2119,#2120,#2121,
#2122,#2123,#2124,#2125,#2126,#2127,#2128,#2129,#2130,#2131,#2132,#2133,#2134,#2135,#2136,#2137,
#2138,#2139,#2140,#2141,#2142,#2143,#2144,#2145,#2146,#2147,#2148,#2149,#2150,#2151,#2152,#2153,
#2154,#2155,#2156,#2157,#2158,#2159,#2160,#2161,#2162,#2163,#2164,#2165,#2166,#2167,#2168,#2169,
#2170,#2171,#2172,#2173,#2174,#2175,#2176,#2177,#2178),.UNSPECIFIED.,.F.,.F.,(4,2,2,2,2,2,2,2,2,
2,2,2,2,2,2,2,2,2,2,2,2,2,2,2,2,2,2,2,2,2,2,2,4),(0.,0.0333392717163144,0.0666785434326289,
0.100017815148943,0.133357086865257,0.166696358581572,0.200035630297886,0.2333749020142,
0.266714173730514,0.300053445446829,0.333392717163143,0.366731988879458,0.400071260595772,
0.433410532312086,0.4667498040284,0.500089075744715,0.533428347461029,0.566767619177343,
0.600106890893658,0.633446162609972,0.666785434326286,0.7001247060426,0.733463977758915,
0.766803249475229,0.800142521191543,0.833481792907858,0.866821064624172,0.900160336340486,
0.9334996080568,0.966838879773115,1.00017815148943,1.03351742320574,1.06685669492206),.UNSPECIFIED.);
#2180=EDGE_CURVE('BSEAM915',#2103,#2111,#2179,.T.);
#2181=ORIENTED_EDGE('',*,*,#2104,.T.);
#2182=ORIENTED_EDGE('',*,*,#2112,.T.);
#2183=ORIENTED_EDGE('',*,*,#2180,.T.);
#2184=ORIENTED_EDGE('',*,*,#2180,.F.);
#2185=EDGE_LOOP('',(#2181,#2183,#2182,#2184));
#2186=FACE_BOUND('',#2185,.T.);
#2187=ADVANCED_FACE('F915',(#2186),#2096,.F.);
#2188=CARTESIAN_POINT('',(48.7,0.,-0.8));
#2189=DIRECTION('',(0.,-1.,0.));
#2190=DIRECTION('',(0.,0.,-1.));
#2191=AXIS2_PLACEMENT_3D('',#2188,#2189,#2190);
#2192=CYLINDRICAL_SURFACE('',#2191,1.3208);
#2193=ORIENTED_EDGE('',*,*,#2112,.F.);
#2194=EDGE_LOOP('',(#2193));
#2195=FACE_BOUND('',#2194,.T.);
#2196=CARTESIAN_POINT('',(48.7,0.,-0.8));
#2197=DIRECTION('',(0.,-1.,0.));
#2198=DIRECTION('',(0.,0.,-1.));
#2199=AXIS2_PLACEMENT_3D('',#2196,#2197,#2198);
#2200=CIRCLE('',#2199,1.3208);
#2201=CARTESIAN_POINT('',(48.7,0.,-2.1208));
#2202=VERTEX_POINT('',#2201);
#2203=EDGE_CURVE('E490',#2202,#2202,#2200,.T.);
#2204=ORIENTED_EDGE('',*,*,#2203,.T.);
#2205=EDGE_LOOP('',(#2204));
#2206=FACE_BOUND('',#2205,.T.);
#2207=ADVANCED_FACE('F906',(#2195,#2206),#2192,.F.);
#2208=ORIENTED_EDGE('',*,*,#2203,.F.);
#2209=EDGE_LOOP('',(#2208));
#2210=FACE_BOUND('',#2209,.T.);
#2211=ORIENTED_EDGE('',*,*,#2087,.T.);
#2212=EDGE_LOOP('',(#2211));
#2213=FACE_BOUND('',#2212,.T.);
#2214=ADVANCED_FACE('F878',(#2210,#2213),#23,.T.);
#2215=CARTESIAN_POINT('',(48.7,0.,-0.8));
#2216=DIRECTION('',(0.,-1.,0.));
#2217=DIRECTION('',(0.,0.,-1.));
#2218=AXIS2_PLACEMENT_3D('',#2215,#2216,#2217);
#2219=CYLINDRICAL_SURFACE('',#2218,0.396874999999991);
#2220=ORIENTED_EDGE('',*,*,#1050,.F.);
#2221=EDGE_LOOP('',(#2220));
#2222=FACE_BOUND('',#2221,.T.);
#2223=ORIENTED_EDGE('',*,*,#2104,.F.);
#2224=EDGE_LOOP('',(#2223));
#2225=FACE_BOUND('',#2224,.T.);
#2226=ADVANCED_FACE('F905',(#2222,#2225),#2219,.F.);
#2227=CARTESIAN_POINT('',(26.67,0.,-1.5));
#2228=DIRECTION('',(0.,-1.,0.));
#2229=DIRECTION('',(0.,0.,-1.));
#2230=AXIS2_PLACEMENT_3D('',#2227,#2228,#2229);
#2231=CYLINDRICAL_SURFACE('',#2230,0.396874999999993);
#2232=ORIENTED_EDGE('',*,*,#943,.F.);
#2233=EDGE_LOOP('',(#2232));
#2234=FACE_BOUND('',#2233,.T.);
#2235=ORIENTED_EDGE('',*,*,#1872,.F.);
#2236=EDGE_LOOP('',(#2235));
#2237=FACE_BOUND('',#2236,.T.);
#2238=ADVANCED_FACE('F912',(#2234,#2237),#2231,.F.);
#2239=CARTESIAN_POINT('',(34.33,0.,-1.5));
#2240=DIRECTION('',(0.,-1.,0.));
#2241=DIRECTION('',(0.,0.,-1.));
#2242=AXIS2_PLACEMENT_3D('',#2239,#2240,#2241);
#2243=CYLINDRICAL_SURFACE('',#2242,0.396874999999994);
#2244=ORIENTED_EDGE('',*,*,#1002,.F.);
#2245=EDGE_LOOP('',(#2244));
#2246=FACE_BOUND('',#2245,.T.);
#2247=ORIENTED_EDGE('',*,*,#1764,.F.);
#2248=EDGE_LOOP('',(#2247));
#2249=FACE_BOUND('',#2248,.T.);
#2250=ADVANCED_FACE('F1219',(#2246,#2249),#2243,.F.);
#2251=CARTESIAN_POINT('',(38.33,0.,-1.5));
#2252=DIRECTION('',(0.,-1.,0.));
#2253=DIRECTION('',(0.,0.,-1.));
#2254=AXIS2_PLACEMENT_3D('',#2251,#2252,#2253);
#2255=CYLINDRICAL_SURFACE('',#2254,0.396874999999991);
#2256=ORIENTED_EDGE('',*,*,#991,.F.);
#2257=EDGE_LOOP('',(#2256));
#2258=FACE_BOUND('',#2257,.T.);
#2259=ORIENTED_EDGE('',*,*,#1656,.F.);
#2260=EDGE_LOOP('',(#2259));
#2261=FACE_BOUND('',#2260,.T.);
#2262=ADVANCED_FACE('F1211',(#2258,#2261),#2255,.F.);
#2263=CARTESIAN_POINT('',(34.33,0.75,-1.5));
#2264=DIRECTION('',(0.,-1.,0.));
#2265=DIRECTION('',(0.,0.,-1.));
#2266=AXIS2_PLACEMENT_3D('',#2263,#2264,#2265);
#2267=CYLINDRICAL_SURFACE('',#2266,3.05);
#2268=ORIENTED_EDGE('',*,*,#617,.T.);
#2269=DIRECTION('',(0.,-1.,0.));
#2270=VECTOR('',#2269,1.);
#2271=CARTESIAN_POINT('',(34.33,0.75,-4.55));
#2272=LINE('',#2271,#2270);
#2273=CARTESIAN_POINT('',(34.33,0.75,-4.55));
#2274=VERTEX_POINT('',#2273);
#2275=EDGE_CURVE('E400',#2274,#616,#2272,.T.);
#2276=ORIENTED_EDGE('',*,*,#2275,.F.);
#2277=CARTESIAN_POINT('',(34.33,0.75,-1.5));
#2278=DIRECTION('',(0.,-1.,0.));
#2279=DIRECTION('',(0.,0.,-1.));
#2280=AXIS2_PLACEMENT_3D('',#2277,#2278,#2279);
#2281=CIRCLE('',#2280,3.05);
#2282=CARTESIAN_POINT('',(34.33,0.75,1.55));
#2283=VERTEX_POINT('',#2282);
#2284=EDGE_CURVE('E387',#2283,#2274,#2281,.T.);
#2285=ORIENTED_EDGE('',*,*,#2284,.F.);
#2286=DIRECTION('',(0.,-1.,0.));
#2287=VECTOR('',#2286,1.);
#2288=CARTESIAN_POINT('',(34.33,0.75,1.55));
#2289=LINE('',#2288,#2287);
#2290=EDGE_CURVE('E410',#2283,#614,#2289,.T.);
#2291=ORIENTED_EDGE('',*,*,#2290,.T.);
#2292=EDGE_LOOP('',(#2268,#2276,#2285,#2291));
#2293=FACE_BOUND('',#2292,.T.);
#2294=ADVANCED_FACE('F1203',(#2293),#2267,.F.);
#2295=CARTESIAN_POINT('',(34.33,0.75,1.55));
#2296=DIRECTION('',(0.,0.,1.));
#2297=DIRECTION('',(1.,0.,0.));
#2298=AXIS2_PLACEMENT_3D('',#2295,#2296,#2297);
#2299=PLANE('',#2298);
#2300=ORIENTED_EDGE('',*,*,#625,.T.);
#2301=ORIENTED_EDGE('',*,*,#2290,.F.);
#2302=DIRECTION('',(-1.,0.,0.));
#2303=VECTOR('',#2302,1.);
#2304=CARTESIAN_POINT('',(34.33,0.75,1.55));
#2305=LINE('',#2304,#2303);
#2306=CARTESIAN_POINT('',(38.33,0.75,1.55));
#2307=VERTEX_POINT('',#2306);
#2308=EDGE_CURVE('E397',#2307,#2283,#2305,.T.);
#2309=ORIENTED_EDGE('',*,*,#2308,.F.);
#2310=DIRECTION('',(0.,-1.,0.));
#2311=VECTOR('',#2310,1.);
#2312=CARTESIAN_POINT('',(38.33,0.75,1.55));
#2313=LINE('',#2312,#2311);
#2314=EDGE_CURVE('E413',#2307,#624,#2313,.T.);
#2315=ORIENTED_EDGE('',*,*,#2314,.T.);
#2316=EDGE_LOOP('',(#2300,#2301,#2309,#2315));
#2317=FACE_BOUND('',#2316,.T.);
#2318=ADVANCED_FACE('F1195',(#2317),#2299,.F.);
#2319=CARTESIAN_POINT('',(38.33,0.75,-1.5));
#2320=DIRECTION('',(0.,-1.,0.));
#2321=DIRECTION('',(0.,0.,-1.));
#2322=AXIS2_PLACEMENT_3D('',#2319,#2320,#2321);
#2323=CYLINDRICAL_SURFACE('',#2322,3.05);
#2324=ORIENTED_EDGE('',*,*,#634,.T.);
#2325=ORIENTED_EDGE('',*,*,#2314,.F.);
#2326=CARTESIAN_POINT('',(38.33,0.75,-1.5));
#2327=DIRECTION('',(0.,-1.,0.));
#2328=DIRECTION('',(0.,0.,-1.));
#2329=AXIS2_PLACEMENT_3D('',#2326,#2327,#2328);
#2330=CIRCLE('',#2329,3.05);
#2331=CARTESIAN_POINT('',(38.33,0.75,-4.55));
#2332=VERTEX_POINT('',#2331);
#2333=EDGE_CURVE('E394',#2332,#2307,#2330,.T.);
#2334=ORIENTED_EDGE('',*,*,#2333,.F.);
#2335=DIRECTION('',(0.,-1.,0.));
#2336=VECTOR('',#2335,1.);
#2337=CARTESIAN_POINT('',(38.33,0.75,-4.55));
#2338=LINE('',#2337,#2336);
#2339=EDGE_CURVE('E415',#2332,#633,#2338,.T.);
#2340=ORIENTED_EDGE('',*,*,#2339,.T.);
#2341=EDGE_LOOP('',(#2324,#2325,#2334,#2340));
#2342=FACE_BOUND('',#2341,.T.);
#2343=ADVANCED_FACE('F1187',(#2342),#2323,.F.);
#2344=CARTESIAN_POINT('',(34.33,0.75,-4.55));
#2345=DIRECTION('',(0.,0.,-1.));
#2346=DIRECTION('',(-1.,0.,0.));
#2347=AXIS2_PLACEMENT_3D('',#2344,#2345,#2346);
#2348=PLANE('',#2347);
#2349=ORIENTED_EDGE('',*,*,#640,.T.);
#2350=ORIENTED_EDGE('',*,*,#2339,.F.);
#2351=DIRECTION('',(1.,0.,0.));
#2352=VECTOR('',#2351,1.);
#2353=CARTESIAN_POINT('',(34.33,0.75,-4.55));
#2354=LINE('',#2353,#2352);
#2355=EDGE_CURVE('E390',#2274,#2332,#2354,.T.);
#2356=ORIENTED_EDGE('',*,*,#2355,.F.);
#2357=ORIENTED_EDGE('',*,*,#2275,.T.);
#2358=EDGE_LOOP('',(#2349,#2350,#2356,#2357));
#2359=FACE_BOUND('',#2358,.T.);
#2360=ADVANCED_FACE('F1179',(#2359),#2348,.F.);
#2361=CARTESIAN_POINT('',(34.33,0.75,-1.5));
#2362=DIRECTION('',(0.,-1.,0.));
#2363=DIRECTION('',(0.,0.,-1.));
#2364=AXIS2_PLACEMENT_3D('',#2361,#2362,#2363);
#2365=PLANE('',#2364);
#2366=DIRECTION('',(-1.,0.,0.));
#2367=VECTOR('',#2366,1.);
#2368=CARTESIAN_POINT('',(34.33,0.75,0.25));
#2369=LINE('',#2368,#2367);
#2370=CARTESIAN_POINT('',(38.33,0.75,0.25));
#2371=VERTEX_POINT('',#2370);
#2372=CARTESIAN_POINT('',(34.33,0.75,0.25));
#2373=VERTEX_POINT('',#2372);
#2374=EDGE_CURVE('E364',#2371,#2373,#2369,.T.);
#2375=ORIENTED_EDGE('',*,*,#2374,.F.);
#2376=CARTESIAN_POINT('',(38.33,0.75,-1.5));
#2377=DIRECTION('',(0.,-1.,0.));
#2378=DIRECTION('',(0.,0.,-1.));
#2379=AXIS2_PLACEMENT_3D('',#2376,#2377,#2378);
#2380=CIRCLE('',#2379,1.75);
#2381=CARTESIAN_POINT('',(38.33,0.75,-3.25));
#2382=VERTEX_POINT('',#2381);
#2383=EDGE_CURVE('E361',#2382,#2371,#2380,.T.);
#2384=ORIENTED_EDGE('',*,*,#2383,.F.);
#2385=DIRECTION('',(1.,0.,0.));
#2386=VECTOR('',#2385,1.);
#2387=CARTESIAN_POINT('',(34.33,0.75,-3.25));
#2388=LINE('',#2387,#2386);
#2389=CARTESIAN_POINT('',(34.33,0.75,-3.25));
#2390=VERTEX_POINT('',#2389);
#2391=EDGE_CURVE('E357',#2390,#2382,#2388,.T.);
#2392=ORIENTED_EDGE('',*,*,#2391,.F.);
#2393=CARTESIAN_POINT('',(34.33,0.75,-1.5));
#2394=DIRECTION('',(0.,-1.,0.));
#2395=DIRECTION('',(0.,0.,-1.));
#2396=AXIS2_PLACEMENT_3D('',#2393,#2394,#2395);
#2397=CIRCLE('',#2396,1.75);
#2398=EDGE_CURVE('E354',#2373,#2390,#2397,.T.);
#2399=ORIENTED_EDGE('',*,*,#2398,.F.);
#2400=EDGE_LOOP('',(#2375,#2384,#2392,#2399));
#2401=FACE_BOUND('',#2400,.T.);
#2402=ORIENTED_EDGE('',*,*,#2284,.T.);
#2403=ORIENTED_EDGE('',*,*,#2355,.T.);
#2404=ORIENTED_EDGE('',*,*,#2333,.T.);
#2405=ORIENTED_EDGE('',*,*,#2308,.T.);
#2406=EDGE_LOOP('',(#2402,#2403,#2404,#2405));
#2407=FACE_BOUND('',#2406,.T.);
#2408=ADVANCED_FACE('F1171',(#2401,#2407),#2365,.T.);
#2409=CARTESIAN_POINT('',(34.33,0.75,-1.5));
#2410=DIRECTION('',(0.,-1.,0.));
#2411=DIRECTION('',(0.,0.,-1.));
#2412=AXIS2_PLACEMENT_3D('',#2409,#2410,#2411);
#2413=CYLINDRICAL_SURFACE('',#2412,1.75);
#2414=ORIENTED_EDGE('',*,*,#86,.F.);
#2415=DIRECTION('',(0.,-1.,0.));
#2416=VECTOR('',#2415,1.);
#2417=CARTESIAN_POINT('',(34.33,0.75,0.25));
#2418=LINE('',#2417,#2416);
#2419=EDGE_CURVE('E378',#2373,#76,#2418,.T.);
#2420=ORIENTED_EDGE('',*,*,#2419,.F.);
#2421=ORIENTED_EDGE('',*,*,#2398,.T.);
#2422=DIRECTION('',(0.,-1.,0.));
#2423=VECTOR('',#2422,1.);
#2424=CARTESIAN_POINT('',(34.33,0.75,-3.25));
#2425=LINE('',#2424,#2423);
#2426=EDGE_CURVE('E367',#2390,#85,#2425,.T.);
#2427=ORIENTED_EDGE('',*,*,#2426,.T.);
#2428=EDGE_LOOP('',(#2414,#2420,#2421,#2427));
#2429=FACE_BOUND('',#2428,.T.);
#2430=ADVANCED_FACE('F1163',(#2429),#2413,.T.);
#2431=CARTESIAN_POINT('',(34.33,0.75,0.25));
#2432=DIRECTION('',(0.,0.,1.));
#2433=DIRECTION('',(1.,0.,0.));
#2434=AXIS2_PLACEMENT_3D('',#2431,#2432,#2433);
#2435=PLANE('',#2434);
#2436=ORIENTED_EDGE('',*,*,#77,.F.);
#2437=DIRECTION('',(0.,-1.,0.));
#2438=VECTOR('',#2437,1.);
#2439=CARTESIAN_POINT('',(38.33,0.75,0.25));
#2440=LINE('',#2439,#2438);
#2441=EDGE_CURVE('E381',#2371,#74,#2440,.T.);
#2442=ORIENTED_EDGE('',*,*,#2441,.F.);
#2443=ORIENTED_EDGE('',*,*,#2374,.T.);
#2444=ORIENTED_EDGE('',*,*,#2419,.T.);
#2445=EDGE_LOOP('',(#2436,#2442,#2443,#2444));
#2446=FACE_BOUND('',#2445,.T.);
#2447=ADVANCED_FACE('F1155',(#2446),#2435,.T.);
#2448=CARTESIAN_POINT('',(38.33,0.75,-1.5));
#2449=DIRECTION('',(0.,-1.,0.));
#2450=DIRECTION('',(0.,0.,-1.));
#2451=AXIS2_PLACEMENT_3D('',#2448,#2449,#2450);
#2452=CYLINDRICAL_SURFACE('',#2451,1.75);
#2453=ORIENTED_EDGE('',*,*,#101,.F.);
#2454=DIRECTION('',(0.,-1.,0.));
#2455=VECTOR('',#2454,1.);
#2456=CARTESIAN_POINT('',(38.33,0.75,-3.25));
#2457=LINE('',#2456,#2455);
#2458=EDGE_CURVE('E383',#2382,#93,#2457,.T.);
#2459=ORIENTED_EDGE('',*,*,#2458,.F.);
#2460=ORIENTED_EDGE('',*,*,#2383,.T.);
#2461=ORIENTED_EDGE('',*,*,#2441,.T.);
#2462=EDGE_LOOP('',(#2453,#2459,#2460,#2461));
#2463=FACE_BOUND('',#2462,.T.);
#2464=ADVANCED_FACE('F1147',(#2463),#2452,.T.);
#2465=CARTESIAN_POINT('',(34.33,0.75,-3.25));
#2466=DIRECTION('',(0.,0.,-1.));
#2467=DIRECTION('',(-1.,0.,0.));
#2468=AXIS2_PLACEMENT_3D('',#2465,#2466,#2467);
#2469=PLANE('',#2468);
#2470=ORIENTED_EDGE('',*,*,#94,.F.);
#2471=ORIENTED_EDGE('',*,*,#2426,.F.);
#2472=ORIENTED_EDGE('',*,*,#2391,.T.);
#2473=ORIENTED_EDGE('',*,*,#2458,.T.);
#2474=EDGE_LOOP('',(#2470,#2471,#2472,#2473));
#2475=FACE_BOUND('',#2474,.T.);
#2476=ADVANCED_FACE('F1139',(#2475),#2469,.T.);
#2477=CARTESIAN_POINT('',(26.67,0.75,-1.5));
#2478=DIRECTION('',(0.,-1.,0.));
#2479=DIRECTION('',(0.,0.,-1.));
#2480=AXIS2_PLACEMENT_3D('',#2477,#2478,#2479);
#2481=CYLINDRICAL_SURFACE('',#2480,2.95);
#2482=CARTESIAN_POINT('',(26.67,0.75,-1.5));
#2483=DIRECTION('',(0.,-1.,0.));
#2484=DIRECTION('',(0.,0.,-1.));
#2485=AXIS2_PLACEMENT_3D('',#2482,#2483,#2484);
#2486=CIRCLE('',#2485,2.95);
#2487=CARTESIAN_POINT('',(26.67,0.75,-4.45));
#2488=VERTEX_POINT('',#2487);
#2489=EDGE_CURVE('E348',#2488,#2488,#2486,.T.);
#2490=ORIENTED_EDGE('',*,*,#2489,.F.);
#2491=EDGE_LOOP('',(#2490));
#2492=FACE_BOUND('',#2491,.T.);
#2493=ORIENTED_EDGE('',*,*,#604,.T.);
#2494=EDGE_LOOP('',(#2493));
#2495=FACE_BOUND('',#2494,.T.);
#2496=ADVANCED_FACE('F1131',(#2492,#2495),#2481,.F.);
#2497=CARTESIAN_POINT('',(26.67,0.75,-1.5));
#2498=DIRECTION('',(0.,-1.,0.));
#2499=DIRECTION('',(0.,0.,-1.));
#2500=AXIS2_PLACEMENT_3D('',#2497,#2498,#2499);
#2501=PLANE('',#2500);
#2502=CARTESIAN_POINT('',(26.67,0.75,-1.5));
#2503=DIRECTION('',(0.,-1.,0.));
#2504=DIRECTION('',(0.,0.,-1.));
#2505=AXIS2_PLACEMENT_3D('',#2502,#2503,#2504);
#2506=CIRCLE('',#2505,1.55);
#2507=CARTESIAN_POINT('',(26.67,0.75,-3.04999999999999));
#2508=VERTEX_POINT('',#2507);
#2509=EDGE_CURVE('E342',#2508,#2508,#2506,.T.);
#2510=ORIENTED_EDGE('',*,*,#2509,.F.);
#2511=EDGE_LOOP('',(#2510));
#2512=FACE_BOUND('',#2511,.T.);
#2513=ORIENTED_EDGE('',*,*,#2489,.T.);
#2514=EDGE_LOOP('',(#2513));
#2515=FACE_BOUND('',#2514,.T.);
#2516=ADVANCED_FACE('F1122',(#2512,#2515),#2501,.T.);
#2517=CARTESIAN_POINT('',(26.67,0.75,-1.5));
#2518=DIRECTION('',(0.,-1.,0.));
#2519=DIRECTION('',(0.,0.,-1.));
#2520=AXIS2_PLACEMENT_3D('',#2517,#2518,#2519);
#2521=CYLINDRICAL_SURFACE('',#2520,1.55);
#2522=ORIENTED_EDGE('',*,*,#2509,.T.);
#2523=EDGE_LOOP('',(#2522));
#2524=FACE_BOUND('',#2523,.T.);
#2525=ORIENTED_EDGE('',*,*,#42,.F.);
#2526=EDGE_LOOP('',(#2525));
#2527=FACE_BOUND('',#2526,.T.);
#2528=ADVANCED_FACE('F1114',(#2524,#2527),#2521,.T.);
#2529=CARTESIAN_POINT('',(56.,46.5,-1.));
#2530=DIRECTION('',(0.,1.,0.));
#2531=DIRECTION('',(0.,0.,1.));
#2532=AXIS2_PLACEMENT_3D('',#2529,#2530,#2531);
#2533=CONICAL_SURFACE('',#2532,2.65429999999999,0.785398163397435);
#2534=ORIENTED_EDGE('',*,*,#141,.F.);
#2535=EDGE_LOOP('',(#2534));
#2536=FACE_BOUND('',#2535,.T.);
#2537=ORIENTED_EDGE('',*,*,#1160,.F.);
#2538=EDGE_LOOP('',(#2537));
#2539=FACE_BOUND('',#2538,.T.);
#2540=ADVANCED_FACE('F770',(#2536,#2539),#2533,.F.);
#2541=CARTESIAN_POINT('',(48.,46.5,0.));
#2542=DIRECTION('',(0.,1.,0.));
#2543=DIRECTION('',(0.,0.,1.));
#2544=AXIS2_PLACEMENT_3D('',#2541,#2542,#2543);
#2545=CONICAL_SURFACE('',#2544,3.96874999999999,0.785398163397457);
#2546=ORIENTED_EDGE('',*,*,#1384,.F.);
#2547=ORIENTED_EDGE('',*,*,#297,.F.);
#2548=ORIENTED_EDGE('',*,*,#1370,.F.);
#2549=ORIENTED_EDGE('',*,*,#1091,.F.);
#2550=EDGE_LOOP('',(#2546,#2547,#2548,#2549));
#2551=FACE_BOUND('',#2550,.T.);
#2552=ADVANCED_FACE('F764',(#2551),#2545,.F.);
#2553=CARTESIAN_POINT('',(36.3333333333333,46.5,0.));
#2554=DIRECTION('',(0.,1.,0.));
#2555=DIRECTION('',(0.,0.,1.));
#2556=AXIS2_PLACEMENT_3D('',#2553,#2554,#2555);
#2557=CONICAL_SURFACE('',#2556,3.96874999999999,0.785398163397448);
#2558=ORIENTED_EDGE('',*,*,#152,.F.);
#2559=EDGE_LOOP('',(#2558));
#2560=FACE_BOUND('',#2559,.T.);
#2561=ORIENTED_EDGE('',*,*,#1030,.F.);
#2562=EDGE_LOOP('',(#2561));
#2563=FACE_BOUND('',#2562,.T.);
#2564=ADVANCED_FACE('F769',(#2560,#2563),#2557,.F.);
#2565=CARTESIAN_POINT('',(24.6666666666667,46.5,0.));
#2566=DIRECTION('',(0.,1.,0.));
#2567=DIRECTION('',(0.,0.,1.));
#2568=AXIS2_PLACEMENT_3D('',#2565,#2566,#2567);
#2569=CONICAL_SURFACE('',#2568,3.96874999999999,0.785398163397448);
#2570=ORIENTED_EDGE('',*,*,#163,.F.);
#2571=EDGE_LOOP('',(#2570));
#2572=FACE_BOUND('',#2571,.T.);
#2573=ORIENTED_EDGE('',*,*,#971,.F.);
#2574=EDGE_LOOP('',(#2573));
#2575=FACE_BOUND('',#2574,.T.);
#2576=ADVANCED_FACE('F776',(#2572,#2575),#2569,.F.);
#2577=CARTESIAN_POINT('',(13.,46.5,0.));
#2578=DIRECTION('',(0.,1.,0.));
#2579=DIRECTION('',(0.,0.,1.));
#2580=AXIS2_PLACEMENT_3D('',#2577,#2578,#2579);
#2581=CONICAL_SURFACE('',#2580,3.96874999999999,0.785398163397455);
#2582=ORIENTED_EDGE('',*,*,#1439,.F.);
#2583=ORIENTED_EDGE('',*,*,#277,.F.);
#2584=ORIENTED_EDGE('',*,*,#1425,.F.);
#2585=ORIENTED_EDGE('',*,*,#874,.F.);
#2586=EDGE_LOOP('',(#2582,#2583,#2584,#2585));
#2587=FACE_BOUND('',#2586,.T.);
#2588=ADVANCED_FACE('F779',(#2587),#2581,.F.);
#2589=CARTESIAN_POINT('',(58.88,38.,-6.));
#2590=DIRECTION('',(-1.,0.,0.));
#2591=DIRECTION('',(0.,-1.,0.));
#2592=AXIS2_PLACEMENT_3D('',#2589,#2590,#2591);
#2593=PLANE('',#2592);
#2594=ORIENTED_EDGE('',*,*,#347,.F.);
#2595=DIRECTION('',(0.,0.,1.));
#2596=VECTOR('',#2595,1.);
#2597=CARTESIAN_POINT('',(58.88,36.2,0.));
#2598=LINE('',#2597,#2596);
#2599=CARTESIAN_POINT('',(58.88,36.2,0.));
#2600=VERTEX_POINT('',#2599);
#2601=EDGE_CURVE('E309',#338,#2600,#2598,.T.);
#2602=ORIENTED_EDGE('',*,*,#2601,.T.);
#2603=DIRECTION('',(0.,-1.,0.));
#2604=VECTOR('',#2603,1.);
#2605=CARTESIAN_POINT('',(58.88,38.,0.));
#2606=LINE('',#2605,#2604);
#2607=CARTESIAN_POINT('',(58.88,14.,0.));
#2608=VERTEX_POINT('',#2607);
#2609=EDGE_CURVE('E267',#2600,#2608,#2606,.T.);
#2610=ORIENTED_EDGE('',*,*,#2609,.T.);
#2611=DIRECTION('',(0.,0.,1.));
#2612=VECTOR('',#2611,1.);
#2613=CARTESIAN_POINT('',(58.88,14.,-3.9107632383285));
#2614=LINE('',#2613,#2612);
#2615=EDGE_CURVE('E307',#2608,#346,#2614,.F.);
#2616=ORIENTED_EDGE('',*,*,#2615,.T.);
#2617=EDGE_LOOP('',(#2594,#2602,#2610,#2616));
#2618=FACE_BOUND('',#2617,.T.);
#2619=ADVANCED_FACE('F328',(#2618),#2593,.F.);
#2620=CARTESIAN_POINT('',(62.58,12.2,-6.));
#2621=DIRECTION('',(0.,-1.,0.));
#2622=DIRECTION('',(0.,0.,-1.));
#2623=AXIS2_PLACEMENT_3D('',#2620,#2621,#2622);
#2624=PLANE('',#2623);
#2625=ORIENTED_EDGE('',*,*,#364,.F.);
#2626=DIRECTION('',(0.,0.,1.));
#2627=VECTOR('',#2626,1.);
#2628=CARTESIAN_POINT('',(60.68,12.2,0.));
#2629=LINE('',#2628,#2627);
#2630=CARTESIAN_POINT('',(60.68,12.2,0.));
#2631=VERTEX_POINT('',#2630);
#2632=EDGE_CURVE('E265',#355,#2631,#2629,.T.);
#2633=ORIENTED_EDGE('',*,*,#2632,.T.);
#2634=DIRECTION('',(1.,0.,0.));
#2635=VECTOR('',#2634,1.);
#2636=CARTESIAN_POINT('',(62.58,12.2,0.));
#2637=LINE('',#2636,#2635);
#2638=EDGE_CURVE('E258',#2631,#1246,#2637,.T.);
#2639=ORIENTED_EDGE('',*,*,#2638,.T.);
#2640=ORIENTED_EDGE('',*,*,#1266,.T.);
#2641=EDGE_LOOP('',(#2625,#2633,#2639,#2640));
#2642=FACE_BOUND('',#2641,.T.);
#2643=ADVANCED_FACE('F261',(#2642),#2624,.F.);
#2644=CARTESIAN_POINT('',(62.58,38.,-6.));
#2645=DIRECTION('',(0.,1.,0.));
#2646=DIRECTION('',(0.,0.,1.));
#2647=AXIS2_PLACEMENT_3D('',#2644,#2645,#2646);
#2648=PLANE('',#2647);
#2649=ORIENTED_EDGE('',*,*,#330,.F.);
#2650=DIRECTION('',(0.,0.,1.));
#2651=VECTOR('',#2650,1.);
#2652=CARTESIAN_POINT('',(60.78,38.,0.));
#2653=LINE('',#2652,#2651);
#2654=CARTESIAN_POINT('',(60.78,38.,0.));
#2655=VERTEX_POINT('',#2654);
#2656=EDGE_CURVE('E300',#321,#2655,#2653,.T.);
#2657=ORIENTED_EDGE('',*,*,#2656,.T.);
#2658=DIRECTION('',(-1.,0.,0.));
#2659=VECTOR('',#2658,1.);
#2660=CARTESIAN_POINT('',(62.58,38.,0.));
#2661=LINE('',#2660,#2659);
#2662=CARTESIAN_POINT('',(60.68,38.,0.));
#2663=VERTEX_POINT('',#2662);
#2664=EDGE_CURVE('E276',#2655,#2663,#2661,.T.);
#2665=ORIENTED_EDGE('',*,*,#2664,.T.);
#2666=DIRECTION('',(0.,0.,1.));
#2667=VECTOR('',#2666,1.);
#2668=CARTESIAN_POINT('',(60.68,38.,-3.9107632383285));
#2669=LINE('',#2668,#2667);
#2670=EDGE_CURVE('E287',#2663,#329,#2669,.F.);
#2671=ORIENTED_EDGE('',*,*,#2670,.T.);
#2672=EDGE_LOOP('',(#2649,#2657,#2665,#2671));
#2673=FACE_BOUND('',#2672,.T.);
#2674=ADVANCED_FACE('F332',(#2673),#2648,.F.);
#2675=CARTESIAN_POINT('',(0.,0.,0.));
#2676=DIRECTION('',(0.,0.,-1.));
#2677=DIRECTION('',(-1.,0.,0.));
#2678=AXIS2_PLACEMENT_3D('',#2675,#2676,#2677);
#2679=PLANE('',#2678);
#2680=CARTESIAN_POINT('',(60.815,34.505,0.));
#2681=DIRECTION('',(0.,0.,-1.));
#2682=DIRECTION('',(-1.,0.,0.));
#2683=AXIS2_PLACEMENT_3D('',#2680,#2681,#2682);
#2684=CIRCLE('',#2683,0.799999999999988);
#2685=CARTESIAN_POINT('',(60.015,34.505,0.));
#2686=VERTEX_POINT('',#2685);
#2687=EDGE_CURVE('E1762',#2686,#2686,#2684,.T.);
#2688=ORIENTED_EDGE('',*,*,#2687,.F.);
#2689=EDGE_LOOP('',(#2688));
#2690=FACE_BOUND('',#2689,.T.);
#2691=CARTESIAN_POINT('',(60.815,15.455,0.));
#2692=DIRECTION('',(0.,0.,-1.));
#2693=DIRECTION('',(-1.,0.,0.));
#2694=AXIS2_PLACEMENT_3D('',#2691,#2692,#2693);
#2695=CIRCLE('',#2694,0.799999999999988);
#2696=CARTESIAN_POINT('',(60.015,15.455,0.));
#2697=VERTEX_POINT('',#2696);
#2698=EDGE_CURVE('E1757',#2697,#2697,#2695,.T.);
#2699=ORIENTED_EDGE('',*,*,#2698,.F.);
#2700=EDGE_LOOP('',(#2699));
#2701=FACE_BOUND('',#2700,.T.);
#2702=ORIENTED_EDGE('',*,*,#2609,.F.);
#2703=CARTESIAN_POINT('',(60.68,36.2,0.));
#2704=DIRECTION('',(0.,0.,-1.));
#2705=DIRECTION('',(-1.,0.,0.));
#2706=AXIS2_PLACEMENT_3D('',#2703,#2704,#2705);
#2707=CIRCLE('',#2706,1.8);
#2708=EDGE_CURVE('E313',#2600,#2663,#2707,.T.);
#2709=ORIENTED_EDGE('',*,*,#2708,.T.);
#2710=ORIENTED_EDGE('',*,*,#2664,.F.);
#2711=CARTESIAN_POINT('',(60.78,39.8,0.));
#2712=DIRECTION('',(0.,0.,-1.));
#2713=DIRECTION('',(-1.,0.,0.));
#2714=AXIS2_PLACEMENT_3D('',#2711,#2712,#2713);
#2715=CIRCLE('',#2714,1.8);
#2716=EDGE_CURVE('E273',#2655,#1248,#2715,.F.);
#2717=ORIENTED_EDGE('',*,*,#2716,.T.);
#2718=ORIENTED_EDGE('',*,*,#1249,.F.);
#2719=ORIENTED_EDGE('',*,*,#2638,.F.);
#2720=CARTESIAN_POINT('',(60.68,14.,0.));
#2721=DIRECTION('',(0.,0.,-1.));
#2722=DIRECTION('',(-1.,0.,0.));
#2723=AXIS2_PLACEMENT_3D('',#2720,#2721,#2722);
#2724=CIRCLE('',#2723,1.8);
#2725=EDGE_CURVE('E53',#2631,#2608,#2724,.T.);
#2726=ORIENTED_EDGE('',*,*,#2725,.T.);
#2727=EDGE_LOOP('',(#2702,#2709,#2710,#2717,#2718,#2719,#2726));
#2728=FACE_BOUND('',#2727,.T.);
#2729=ADVANCED_FACE('F271',(#2690,#2701,#2728),#2679,.T.);
#2730=CARTESIAN_POINT('',(60.815,15.455,0.));
#2731=DIRECTION('',(0.,0.,-1.));
#2732=DIRECTION('',(-1.,0.,0.));
#2733=AXIS2_PLACEMENT_3D('',#2730,#2731,#2732);
#2734=CYLINDRICAL_SURFACE('',#2733,0.799999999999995);
#2735=ORIENTED_EDGE('',*,*,#427,.F.);
#2736=EDGE_LOOP('',(#2735));
#2737=FACE_BOUND('',#2736,.T.);
#2738=ORIENTED_EDGE('',*,*,#2698,.T.);
#2739=EDGE_LOOP('',(#2738));
#2740=FACE_BOUND('',#2739,.T.);
#2741=ADVANCED_FACE('F1050',(#2737,#2740),#2734,.F.);
#2742=CARTESIAN_POINT('',(60.815,34.505,0.));
#2743=DIRECTION('',(0.,0.,-1.));
#2744=DIRECTION('',(-1.,0.,0.));
#2745=AXIS2_PLACEMENT_3D('',#2742,#2743,#2744);
#2746=CYLINDRICAL_SURFACE('',#2745,0.799999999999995);
#2747=ORIENTED_EDGE('',*,*,#416,.F.);
#2748=EDGE_LOOP('',(#2747));
#2749=FACE_BOUND('',#2748,.T.);
#2750=ORIENTED_EDGE('',*,*,#2687,.T.);
#2751=EDGE_LOOP('',(#2750));
#2752=FACE_BOUND('',#2751,.T.);
#2753=ADVANCED_FACE('F1045',(#2749,#2752),#2746,.F.);
#2754=CARTESIAN_POINT('',(60.78,39.8,-5.99999999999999));
#2755=DIRECTION('',(0.,0.,-1.));
#2756=DIRECTION('',(-1.,0.,0.));
#2757=AXIS2_PLACEMENT_3D('',#2754,#2755,#2756);
#2758=CYLINDRICAL_SURFACE('',#2757,1.8);
#2759=ORIENTED_EDGE('',*,*,#322,.F.);
#2760=ORIENTED_EDGE('',*,*,#1255,.F.);
#2761=ORIENTED_EDGE('',*,*,#2716,.F.);
#2762=ORIENTED_EDGE('',*,*,#2656,.F.);
#2763=EDGE_LOOP('',(#2759,#2760,#2761,#2762));
#2764=FACE_BOUND('',#2763,.T.);
#2765=ADVANCED_FACE('F785',(#2764),#2758,.T.);
#2766=CARTESIAN_POINT('',(60.68,36.2,-6.));
#2767=DIRECTION('',(0.,0.,-1.));
#2768=DIRECTION('',(-1.,0.,0.));
#2769=AXIS2_PLACEMENT_3D('',#2766,#2767,#2768);
#2770=CYLINDRICAL_SURFACE('',#2769,1.8);
#2771=ORIENTED_EDGE('',*,*,#339,.F.);
#2772=ORIENTED_EDGE('',*,*,#2670,.F.);
#2773=ORIENTED_EDGE('',*,*,#2708,.F.);
#2774=ORIENTED_EDGE('',*,*,#2601,.F.);
#2775=EDGE_LOOP('',(#2771,#2772,#2773,#2774));
#2776=FACE_BOUND('',#2775,.T.);
#2777=ADVANCED_FACE('F329',(#2776),#2770,.F.);
#2778=CARTESIAN_POINT('',(60.68,14.,-6.));
#2779=DIRECTION('',(0.,0.,-1.));
#2780=DIRECTION('',(-1.,0.,0.));
#2781=AXIS2_PLACEMENT_3D('',#2778,#2779,#2780);
#2782=CYLINDRICAL_SURFACE('',#2781,1.8);
#2783=ORIENTED_EDGE('',*,*,#356,.F.);
#2784=ORIENTED_EDGE('',*,*,#2615,.F.);
#2785=ORIENTED_EDGE('',*,*,#2725,.F.);
#2786=ORIENTED_EDGE('',*,*,#2632,.F.);
#2787=EDGE_LOOP('',(#2783,#2784,#2785,#2786));
#2788=FACE_BOUND('',#2787,.T.);
#2789=ADVANCED_FACE('F40',(#2788),#2782,.F.);
#2790=CLOSED_SHELL('',(#46,#105,#128,#301,#403,#472,#512,#552,#574,#596,#729,#757,#930,#958,
#978,#1017,#1037,#1065,#1147,#1167,#1184,#1207,#1235,#1270,#1282,#1294,#1311,#1323,#1340,#1352,
#1396,#1407,#1451,#1462,#1483,#1495,#1516,#1528,#1549,#1561,#1582,#1594,#1603,#1631,#1643,#1739,
#1751,#1847,#1859,#1955,#1967,#1979,#1999,#2019,#2031,#2051,#2071,#2091,#2187,#2207,#2214,#2226,
#2238,#2250,#2262,#2294,#2318,#2343,#2360,#2408,#2430,#2447,#2464,#2476,#2496,#2516,#2528,#2540,
#2552,#2564,#2576,#2588,#2619,#2643,#2674,#2729,#2741,#2753,#2765,#2777,#2789));
#2791=MANIFOLD_SOLID_BREP('B2',#2790);
#2792=ADVANCED_BREP_SHAPE_REPRESENTATION('',(#18,#2791),#14);
#2793=SHAPE_DEFINITION_REPRESENTATION(#9,#2792);
ENDSEC;
END-ISO-10303-21;
